# LEF Technology file generated by TechBuilder version 3.7.0_pr1
# Metal Stack Option = 1P8M_2TM_ALPA2
#
#     Copyright (c) 2017 ARM, Inc.
#
#     ALL RIGHTS RESERVED
#
#     The confidential and proprietary information contained in this file
#     may only be used by a person authorised under and to the extent
#     permitted by a subsisting licensing agreement from ARM Limited.
#
#     This entire notice must be reproduced on all copies of this file
#     and copies of this file may only be made by a person if such person
#     is permitted to do so under the terms of a subsisting license
#     agreement from ARM Limited.

VERSION 5.7 ;
BUSBITCHARS "[]" ;
DIVIDERCHAR "/" ;
CLEARANCEMEASURE EUCLIDEAN ;

UNITS
  DATABASE MICRONS 2000 ;
END UNITS

MANUFACTURINGGRID 0.0010 ;
USEMINSPACING OBS OFF ;

PROPERTYDEFINITIONS
  LAYER LEF58_ENCLOSUREEDGE STRING ;
  LAYER LEF58_ARRAYSPACING STRING ;
  LAYER LEF58_ARRAYSPACING STRING ; 
  LAYER LEF58_SPACING STRING ; 
END PROPERTYDEFINITIONS

LAYER GT
  TYPE MASTERSLICE ;
END GT

LAYER HVT
  TYPE IMPLANT ;
  SPACING 0.18 ;
  WIDTH 0.18 ;
END HVT

LAYER LVT
  TYPE IMPLANT ;
  SPACING 0.18 ;
  WIDTH 0.18 ;
END LVT

LAYER ULVT
  TYPE IMPLANT ;
  SPACING 0.33 ;
  WIDTH 0.33 ;
END ULVT

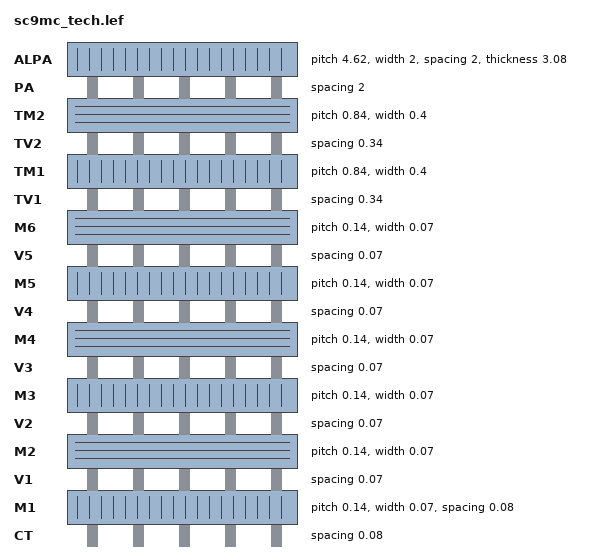
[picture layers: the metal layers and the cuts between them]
LAYER CT
  TYPE CUT ;
  SPACING 0.08 ;
  ENCLOSURE ABOVE 0.0 0.025 ;
  PROPERTY LEF58_ENCLOSUREEDGE "
  ENCLOSUREEDGE ABOVE 0.015 WIDTH 0.12 PARALLEL 0.27 WITHIN 0.081 EXCEPTEXTRACUT ;
  " ;
END CT

LAYER M1
  TYPE ROUTING ;
  DIRECTION VERTICAL ;
  PITCH 0.14 ;
  OFFSET 0.07 ;
  WIDTH 0.07 ;
  MINWIDTH 0.07 ;
  MAXWIDTH 4.5 ;
  AREA 0.0196 ;
  MINENCLOSEDAREA 0.2 ;
  MINSTEP 0.07 MAXEDGES 1 ;
  SPACINGTABLE TWOWIDTHS
    WIDTH 0.000        0.070 0.080 0.120 0.300
    WIDTH 0.224 PRL 0.299 0.080 0.080 0.140 0.300
    WIDTH 0.704 PRL 0.599 0.120 0.140 0.140 0.300
    WIDTH 1.504 PRL 1.499 0.300 0.300 0.300 0.300
    ;
  MINIMUMCUT 2 WIDTH 0.26 FROMABOVE ;
  MINIMUMCUT 3 WIDTH 0.52 FROMABOVE ;
  MINIMUMCUT 4 WIDTH 0.645 FROMABOVE ;
  MINIMUMCUT 2 WIDTH 0.24 WITHIN 0.16 FROMABOVE ;
  MINIMUMCUT 2 WIDTH 0.24 FROMABOVE LENGTH 0.24 WITHIN 1.1 ;
  MINIMUMCUT 2 WIDTH 1.4 FROMABOVE LENGTH 1.4 WITHIN 2.8 ;
  MINIMUMCUT 2 WIDTH 2.1 FROMABOVE LENGTH 7.0 WITHIN 7.1 ;
  ANTENNAMODEL OXIDE1 ;
  ANTENNACUMDIFFAREARATIO PWL (  ( 0.0 5000.0 ) ( 0.1 44050.0 ) ( 0.2 44100.0 ) ( 0.5 44250.0 ) ( 1.0 44500.0 ) ) ;
  DCCURRENTDENSITY AVERAGE 1.2 ;
  PROPERTY LEF58_SPACING "
SPACING .08 ENDOFLINE .09 WITHIN 0.02 PARALLELEDGE .081 WITHIN 0.1 MINLENGTH .07 TWOEDGES ; " ;
MINIMUMDENSITY      20 ;
    MAXIMUMDENSITY      80 ;
    DENSITYCHECKWINDOW 25 25 ;
    DENSITYCHECKSTEP    12.5 ;

END M1

LAYER V1
  TYPE CUT ;
  SPACING 0.07 SAMENET ;

  SPACING 0.1 PARALLELOVERLAP ;
  SPACING 0.09 ;
  PROPERTY LEF58_ARRAYSPACING "ARRAYSPACING  LONGARRAY CUTSPACING 0.09 ARRAYCUTS 3 SPACING 0.1 ;" ;
  ENCLOSURE  0.0 0.03 ;
  ENCLOSURE  0.02 0.01 ;
  ENCLOSURE  0.015 0.015 WIDTH 0.145 ;
  ANTENNAMODEL OXIDE1 ;
  ANTENNAAREARATIO 20.0 ;
  ANTENNACUMDIFFAREARATIO PWL (  ( 0.0 50.0 ) ( 0.1 1020.0 ) ( 0.2 1040.0 ) ( 0.5 1100.0 ) ( 1.0 1200.0 ) ) ;
  DCCURRENTDENSITY AVERAGE 0.07 ;
END V1

LAYER M2
  TYPE ROUTING ;
  DIRECTION HORIZONTAL ;
  PITCH 0.14 ;
  OFFSET 0.07 ;
  WIDTH 0.07 ;
  MINWIDTH 0.07 ;
  MAXWIDTH 4.5 ;
  AREA 0.0196 ;
  MINENCLOSEDAREA 0.2 ;
  MINSTEP 0.07 MAXEDGES 1 ;
  SPACINGTABLE TWOWIDTHS
    WIDTH 0.000        0.070 0.100 0.100 0.120 0.120 0.300
    WIDTH 0.219 PRL 0.299 0.100 0.100 0.100 0.120 0.120 0.300
    WIDTH 0.224 PRL 0.299 0.100 0.100 0.100 0.120 0.140 0.300
    WIDTH 0.699 PRL 0.599 0.120 0.120 0.120 0.120 0.140 0.300
    WIDTH 0.704 PRL 0.599 0.120 0.120 0.140 0.140 0.140 0.300
    WIDTH 1.504 PRL 1.504 0.300 0.300 0.300 0.300 0.300 0.300
    ;
  MINIMUMCUT 2 WIDTH 0.26 FROMBELOW ;
  MINIMUMCUT 3 WIDTH 0.52 FROMBELOW ;
  MINIMUMCUT 4 WIDTH 0.645 FROMBELOW ;
  MINIMUMCUT 2 WIDTH 0.24 WITHIN 0.16 FROMBELOW ;
  MINIMUMCUT 2 WIDTH 0.24 FROMBELOW LENGTH 0.24 WITHIN 1.1 ;
  MINIMUMCUT 2 WIDTH 1.4 FROMBELOW LENGTH 1.4 WITHIN 2.8 ;
  MINIMUMCUT 2 WIDTH 2.1 FROMBELOW LENGTH 7.0 WITHIN 7.1 ;
  MINIMUMCUT 2 WIDTH 0.26 FROMABOVE ;
  MINIMUMCUT 3 WIDTH 0.52 FROMABOVE ;
  MINIMUMCUT 4 WIDTH 0.645 FROMABOVE ;
  MINIMUMCUT 2 WIDTH 0.24 WITHIN 0.16 FROMABOVE ;
  MINIMUMCUT 2 WIDTH 0.24 FROMABOVE LENGTH 0.24 WITHIN 1.1 ;
  MINIMUMCUT 2 WIDTH 1.4 FROMABOVE LENGTH 1.4 WITHIN 2.8 ;
  MINIMUMCUT 2 WIDTH 2.1 FROMABOVE LENGTH 7.0 WITHIN 7.1 ;
  ANTENNAMODEL OXIDE1 ;
  ANTENNACUMDIFFAREARATIO PWL (  ( 0.0 5000.0 ) ( 0.1 44050.0 ) ( 0.2 44100.0 ) ( 0.5 44250.0 ) ( 1.0 44500.0 ) ) ;
  DCCURRENTDENSITY AVERAGE 1.3 ; 
  PROPERTY LEF58_SPACING "SPACING 0.12 ENDOFLINE 0.1 WITHIN 0.03 PARALLELEDGE 0.079 WITHIN 0.095  ENCLOSECUT BELOW 0.05 CUTSPACING 0.12 ;" ; 
  PROPERTY LEF58_SPACING "SPACING 0.1 ENDOFLINE 0.1 WITHIN 0.03 PARALLELEDGE 0.1 WITHIN 0.095 ;" ;
  PROPERTY LEF58_SPACING "SPACING 0.1 ENDOFLINE 0.1 WITHIN 0.03 ;" ;
MINIMUMDENSITY      20 ;
    MAXIMUMDENSITY      80 ;
    DENSITYCHECKWINDOW 25 25 ;
    DENSITYCHECKSTEP    12.5 ;

END M2

LAYER V2
  TYPE CUT ;
  SPACING 0.07 SAMENET ;
  SPACING 0.09 ;
  SPACING 0.1 PARALLELOVERLAP ;

  PROPERTY LEF58_ARRAYSPACING "ARRAYSPACING  LONGARRAY CUTSPACING 0.09 ARRAYCUTS 3 SPACING 0.1 ;" ;
  ENCLOSURE  0.0 0.03 ;
  ENCLOSURE  0.02 0.01 ;
  ENCLOSURE  0.015 0.015 WIDTH 0.145 ;
  ANTENNAMODEL OXIDE1 ;
  ANTENNAAREARATIO 20.0 ;
  ANTENNACUMDIFFAREARATIO PWL (  ( 0.0 50.0 ) ( 0.1 1020.0 ) ( 0.2 1040.0 ) ( 0.5 1100.0 ) ( 1.0 1200.0 ) ) ;
  DCCURRENTDENSITY AVERAGE 0.07 ;
END V2

LAYER M3
  TYPE ROUTING ;
  DIRECTION VERTICAL ;
  PITCH 0.14 ;
  OFFSET 0.07 ;
  WIDTH 0.07 ;
  MINWIDTH 0.07 ;
  MAXWIDTH 4.5 ;
  AREA 0.0196 ;
  MINENCLOSEDAREA 0.2 ;
  MINSTEP 0.07 MAXEDGES 1 ;
  SPACINGTABLE TWOWIDTHS
    WIDTH 0.000        0.070 0.100 0.100 0.120 0.120 0.300
    WIDTH 0.219 PRL 0.299 0.100 0.100 0.100 0.120 0.120 0.300
    WIDTH 0.224 PRL 0.299 0.100 0.100 0.100 0.120 0.140 0.300
    WIDTH 0.699 PRL 0.599 0.120 0.120 0.120 0.120 0.140 0.300
    WIDTH 0.704 PRL 0.599 0.120 0.120 0.140 0.140 0.140 0.300
    WIDTH 1.504 PRL 1.504 0.300 0.300 0.300 0.300 0.300 0.300
    ;
  MINIMUMCUT 2 WIDTH 0.26 FROMBELOW ;
  MINIMUMCUT 3 WIDTH 0.52 FROMBELOW ;
  MINIMUMCUT 4 WIDTH 0.645 FROMBELOW ;
  MINIMUMCUT 2 WIDTH 0.24 WITHIN 0.16 FROMBELOW ;
  MINIMUMCUT 2 WIDTH 0.24 FROMBELOW LENGTH 0.24 WITHIN 1.1 ;
  MINIMUMCUT 2 WIDTH 1.4 FROMBELOW LENGTH 1.4 WITHIN 2.8 ;
  MINIMUMCUT 2 WIDTH 2.1 FROMBELOW LENGTH 7.0 WITHIN 7.1 ;
  MINIMUMCUT 2 WIDTH 0.26 FROMABOVE ;
  MINIMUMCUT 3 WIDTH 0.52 FROMABOVE ;
  MINIMUMCUT 4 WIDTH 0.645 FROMABOVE ;
  MINIMUMCUT 2 WIDTH 0.24 WITHIN 0.16 FROMABOVE ;
  MINIMUMCUT 2 WIDTH 0.24 FROMABOVE LENGTH 0.24 WITHIN 1.1 ;
  MINIMUMCUT 2 WIDTH 1.4 FROMABOVE LENGTH 1.4 WITHIN 2.8 ;
  MINIMUMCUT 2 WIDTH 2.1 FROMABOVE LENGTH 7.0 WITHIN 7.1 ;
  ANTENNAMODEL OXIDE1 ;
  ANTENNACUMDIFFAREARATIO PWL (  ( 0.0 5000.0 ) ( 0.1 44050.0 ) ( 0.2 44100.0 ) ( 0.5 44250.0 ) ( 1.0 44500.0 ) ) ;
  DCCURRENTDENSITY AVERAGE 1.3 ; 
  PROPERTY LEF58_SPACING "SPACING 0.12 ENDOFLINE 0.1 WITHIN 0.03 PARALLELEDGE 0.079 WITHIN 0.095  ENCLOSECUT BELOW 0.05 CUTSPACING 0.12 ;" ; 
  PROPERTY LEF58_SPACING "SPACING 0.1 ENDOFLINE 0.1 WITHIN 0.03 PARALLELEDGE 0.1 WITHIN 0.095 ;" ;
  PROPERTY LEF58_SPACING "SPACING 0.1 ENDOFLINE 0.1 WITHIN 0.03 ;" ;
MINIMUMDENSITY      20 ;
    MAXIMUMDENSITY      80 ;
    DENSITYCHECKWINDOW 25 25 ;
    DENSITYCHECKSTEP    12.5 ;

END M3

LAYER V3
  TYPE CUT ;
  SPACING 0.07 SAMENET ;
  SPACING 0.09 ;
  SPACING 0.1 PARALLELOVERLAP ;

  PROPERTY LEF58_ARRAYSPACING "ARRAYSPACING  LONGARRAY CUTSPACING 0.09 ARRAYCUTS 3 SPACING 0.1 ;" ;
  ENCLOSURE  0.0 0.03 ;
  ENCLOSURE  0.02 0.01 ;
  ENCLOSURE  0.015 0.015 WIDTH 0.145 ;
  ANTENNAMODEL OXIDE1 ;
  ANTENNAAREARATIO 20.0 ;
  ANTENNACUMDIFFAREARATIO PWL (  ( 0.0 50.0 ) ( 0.1 1020.0 ) ( 0.2 1040.0 ) ( 0.5 1100.0 ) ( 1.0 1200.0 ) ) ;
  DCCURRENTDENSITY AVERAGE 0.07 ;
END V3

LAYER M4
  TYPE ROUTING ;
  DIRECTION HORIZONTAL ;
  PITCH 0.14 ;
  OFFSET 0.07 ;
  WIDTH 0.07 ;
  MINWIDTH 0.07 ;
  MAXWIDTH 4.5 ;
  AREA 0.0196 ;
  MINENCLOSEDAREA 0.2 ;
  MINSTEP 0.07 MAXEDGES 1 ;
  SPACINGTABLE TWOWIDTHS
    WIDTH 0.000        0.070 0.100 0.100 0.120 0.120 0.300
    WIDTH 0.219 PRL 0.299 0.100 0.100 0.100 0.120 0.120 0.300
    WIDTH 0.224 PRL 0.299 0.100 0.100 0.100 0.120 0.140 0.300
    WIDTH 0.699 PRL 0.599 0.120 0.120 0.120 0.120 0.140 0.300
    WIDTH 0.704 PRL 0.599 0.120 0.120 0.140 0.140 0.140 0.300
    WIDTH 1.504 PRL 1.504 0.300 0.300 0.300 0.300 0.300 0.300
    ;
  MINIMUMCUT 2 WIDTH 0.26 FROMBELOW ;
  MINIMUMCUT 3 WIDTH 0.52 FROMBELOW ;
  MINIMUMCUT 4 WIDTH 0.645 FROMBELOW ;
  MINIMUMCUT 2 WIDTH 0.24 WITHIN 0.16 FROMBELOW ;
  MINIMUMCUT 2 WIDTH 0.24 FROMBELOW LENGTH 0.24 WITHIN 1.1 ;
  MINIMUMCUT 2 WIDTH 1.4 FROMBELOW LENGTH 1.4 WITHIN 2.8 ;
  MINIMUMCUT 2 WIDTH 2.1 FROMBELOW LENGTH 7.0 WITHIN 7.1 ;
  MINIMUMCUT 2 WIDTH 0.26 FROMABOVE ;
  MINIMUMCUT 3 WIDTH 0.52 FROMABOVE ;
  MINIMUMCUT 4 WIDTH 0.645 FROMABOVE ;
  MINIMUMCUT 2 WIDTH 0.24 WITHIN 0.16 FROMABOVE ;
  MINIMUMCUT 2 WIDTH 0.24 FROMABOVE LENGTH 0.24 WITHIN 1.1 ;
  MINIMUMCUT 2 WIDTH 1.4 FROMABOVE LENGTH 1.4 WITHIN 2.8 ;
  MINIMUMCUT 2 WIDTH 2.1 FROMABOVE LENGTH 7.0 WITHIN 7.1 ;
  ANTENNAMODEL OXIDE1 ;
  ANTENNACUMDIFFAREARATIO PWL (  ( 0.0 5000.0 ) ( 0.1 44050.0 ) ( 0.2 44100.0 ) ( 0.5 44250.0 ) ( 1.0 44500.0 ) ) ;
  DCCURRENTDENSITY AVERAGE 1.3 ; 
  PROPERTY LEF58_SPACING "SPACING 0.12 ENDOFLINE 0.1 WITHIN 0.03 PARALLELEDGE 0.079 WITHIN 0.095  ENCLOSECUT BELOW 0.05 CUTSPACING 0.12 ;" ; 
  PROPERTY LEF58_SPACING "SPACING 0.1 ENDOFLINE 0.1 WITHIN 0.03 PARALLELEDGE 0.1 WITHIN 0.095 ;" ;
  PROPERTY LEF58_SPACING "SPACING 0.1 ENDOFLINE 0.1 WITHIN 0.03 ;" ;
MINIMUMDENSITY      20 ;
    MAXIMUMDENSITY      80 ;
    DENSITYCHECKWINDOW 25 25 ;
    DENSITYCHECKSTEP    12.5 ;

END M4

LAYER V4
  TYPE CUT ;
  SPACING 0.07 SAMENET ;
  SPACING 0.09 ;
  SPACING 0.1 PARALLELOVERLAP ;

  PROPERTY LEF58_ARRAYSPACING "ARRAYSPACING  LONGARRAY CUTSPACING 0.09 ARRAYCUTS 3 SPACING 0.1 ;" ;
  ENCLOSURE  0.0 0.03 ;
  ENCLOSURE  0.02 0.01 ;
  ENCLOSURE  0.015 0.015 WIDTH 0.145 ;
  ANTENNAMODEL OXIDE1 ;
  ANTENNAAREARATIO 20.0 ;
  ANTENNACUMDIFFAREARATIO PWL (  ( 0.0 50.0 ) ( 0.1 1020.0 ) ( 0.2 1040.0 ) ( 0.5 1100.0 ) ( 1.0 1200.0 ) ) ;
  DCCURRENTDENSITY AVERAGE 0.07 ;
END V4

LAYER M5
  TYPE ROUTING ;
  DIRECTION VERTICAL ;
  PITCH 0.14 ;
  OFFSET 0.07 ;
  WIDTH 0.07 ;
  MINWIDTH 0.07 ;
  MAXWIDTH 4.5 ;
  AREA 0.0196 ;
  MINENCLOSEDAREA 0.2 ;
  MINSTEP 0.07 MAXEDGES 1 ;
  SPACINGTABLE TWOWIDTHS
    WIDTH 0.000        0.070 0.100 0.100 0.120 0.120 0.300
    WIDTH 0.219 PRL 0.299 0.100 0.100 0.100 0.120 0.120 0.300
    WIDTH 0.224 PRL 0.299 0.100 0.100 0.100 0.120 0.140 0.300
    WIDTH 0.699 PRL 0.599 0.120 0.120 0.120 0.120 0.140 0.300
    WIDTH 0.704 PRL 0.599 0.120 0.120 0.140 0.140 0.140 0.300
    WIDTH 1.504 PRL 1.504 0.300 0.300 0.300 0.300 0.300 0.300
    ;
  MINIMUMCUT 2 WIDTH 0.26 FROMBELOW ;
  MINIMUMCUT 3 WIDTH 0.52 FROMBELOW ;
  MINIMUMCUT 4 WIDTH 0.645 FROMBELOW ;
  MINIMUMCUT 2 WIDTH 0.24 WITHIN 0.16 FROMBELOW ;
  MINIMUMCUT 2 WIDTH 0.24 FROMBELOW LENGTH 0.24 WITHIN 1.1 ;
  MINIMUMCUT 2 WIDTH 1.4 FROMBELOW LENGTH 1.4 WITHIN 2.8 ;
  MINIMUMCUT 2 WIDTH 2.1 FROMBELOW LENGTH 7.0 WITHIN 7.1 ;
  MINIMUMCUT 2 WIDTH 0.26 FROMABOVE ;
  MINIMUMCUT 3 WIDTH 0.52 FROMABOVE ;
  MINIMUMCUT 4 WIDTH 0.645 FROMABOVE ;
  MINIMUMCUT 2 WIDTH 0.24 WITHIN 0.16 FROMABOVE ;
  MINIMUMCUT 2 WIDTH 0.24 FROMABOVE LENGTH 0.24 WITHIN 1.1 ;
  MINIMUMCUT 2 WIDTH 1.4 FROMABOVE LENGTH 1.4 WITHIN 2.8 ;
  MINIMUMCUT 2 WIDTH 2.1 FROMABOVE LENGTH 7.0 WITHIN 7.1 ;
  ANTENNAMODEL OXIDE1 ;
  ANTENNACUMDIFFAREARATIO PWL (  ( 0.0 5000.0 ) ( 0.1 44050.0 ) ( 0.2 44100.0 ) ( 0.5 44250.0 ) ( 1.0 44500.0 ) ) ;
  DCCURRENTDENSITY AVERAGE 1.3 ; 
  PROPERTY LEF58_SPACING "SPACING 0.12 ENDOFLINE 0.1 WITHIN 0.03 PARALLELEDGE 0.079 WITHIN 0.095  ENCLOSECUT BELOW 0.05 CUTSPACING 0.12 ;" ; 
  PROPERTY LEF58_SPACING "SPACING 0.1 ENDOFLINE 0.1 WITHIN 0.03 PARALLELEDGE 0.1 WITHIN 0.095 ;" ;
  PROPERTY LEF58_SPACING "SPACING 0.1 ENDOFLINE 0.1 WITHIN 0.03 ;" ;
MINIMUMDENSITY      20 ;
    MAXIMUMDENSITY      80 ;
    DENSITYCHECKWINDOW 25 25 ;
    DENSITYCHECKSTEP    12.5 ;

END M5

LAYER V5
  TYPE CUT ;
  SPACING 0.07 SAMENET ;
  SPACING 0.09 ;
  SPACING 0.1 PARALLELOVERLAP ;

  PROPERTY LEF58_ARRAYSPACING "ARRAYSPACING  LONGARRAY CUTSPACING 0.09 ARRAYCUTS 3 SPACING 0.1 ;" ;
  ENCLOSURE  0.0 0.03 ;
  ENCLOSURE  0.02 0.01 ;
  ENCLOSURE  0.015 0.015 WIDTH 0.145 ;
  ANTENNAMODEL OXIDE1 ;
  ANTENNAAREARATIO 20.0 ;
  ANTENNACUMDIFFAREARATIO PWL (  ( 0.0 50.0 ) ( 0.1 1020.0 ) ( 0.2 1040.0 ) ( 0.5 1100.0 ) ( 1.0 1200.0 ) ) ;
  DCCURRENTDENSITY AVERAGE 0.07 ;
END V5

LAYER M6
  TYPE ROUTING ;
  DIRECTION HORIZONTAL ;
  PITCH 0.14 ;
  OFFSET 0.07 ;
  WIDTH 0.07 ;
  MINWIDTH 0.07 ;
  MAXWIDTH 4.5 ;
  AREA 0.0196 ;
  MINENCLOSEDAREA 0.2 ;
  MINSTEP 0.07 MAXEDGES 1 ;
  SPACINGTABLE TWOWIDTHS
    WIDTH 0.000        0.070 0.100 0.100 0.120 0.120 0.300
    WIDTH 0.219 PRL 0.299 0.100 0.100 0.100 0.120 0.120 0.300
    WIDTH 0.224 PRL 0.299 0.100 0.100 0.100 0.120 0.140 0.300
    WIDTH 0.699 PRL 0.599 0.120 0.120 0.120 0.120 0.140 0.300
    WIDTH 0.704 PRL 0.599 0.120 0.120 0.140 0.140 0.140 0.300
    WIDTH 1.504 PRL 1.504 0.300 0.300 0.300 0.300 0.300 0.300
    ;
  MINIMUMCUT 2 WIDTH 0.26 FROMBELOW ;
  MINIMUMCUT 3 WIDTH 0.52 FROMBELOW ;
  MINIMUMCUT 4 WIDTH 0.645 FROMBELOW ;
  MINIMUMCUT 2 WIDTH 0.24 WITHIN 0.16 FROMBELOW ;
  MINIMUMCUT 2 WIDTH 0.24 FROMBELOW LENGTH 0.24 WITHIN 1.1 ;
  MINIMUMCUT 2 WIDTH 1.4 FROMBELOW LENGTH 1.4 WITHIN 2.8 ;
  MINIMUMCUT 2 WIDTH 2.1 FROMBELOW LENGTH 7.0 WITHIN 7.1 ;
  MINIMUMCUT 2 WIDTH 1.8 FROMABOVE ;
  MINIMUMCUT 2 WIDTH 3.0 FROMABOVE LENGTH 10.0 WITHIN 5.0 ;
  ANTENNAMODEL OXIDE1 ;
  ANTENNACUMDIFFAREARATIO PWL (  ( 0.0 5000.0 ) ( 0.1 44050.0 ) ( 0.2 44100.0 ) ( 0.5 44250.0 ) ( 1.0 44500.0 ) ) ;
  DCCURRENTDENSITY AVERAGE 1.3 ; 
  PROPERTY LEF58_SPACING "SPACING 0.12 ENDOFLINE 0.1 WITHIN 0.03 PARALLELEDGE 0.079 WITHIN 0.095  ENCLOSECUT BELOW 0.05 CUTSPACING 0.12 ;" ; 
  PROPERTY LEF58_SPACING "SPACING 0.1 ENDOFLINE 0.1 WITHIN 0.03 PARALLELEDGE 0.1 WITHIN 0.095 ;" ;
  PROPERTY LEF58_SPACING "SPACING 0.1 ENDOFLINE 0.1 WITHIN 0.03 ;" ;
MINIMUMDENSITY      20 ;
    MAXIMUMDENSITY      80 ;
    DENSITYCHECKWINDOW 25 25 ;
    DENSITYCHECKSTEP    12.5 ;

END M6

LAYER TV1
  TYPE CUT ;
  SPACING 0.34 ;

  PROPERTY LEF58_ARRAYSPACING "ARRAYSPACING  LONGARRAY CUTSPACING 0.5 ARRAYCUTS 3 SPACING 0.56 ;" ;
  ENCLOSURE BELOW 0.01 0.05 ;
  ENCLOSURE ABOVE 0.02 0.03 ;
  ANTENNAMODEL OXIDE1 ;
  ANTENNAAREARATIO 20.0 ;
  ANTENNACUMDIFFAREARATIO PWL (  ( 0.0 50.0 ) ( 0.1 1020.0 ) ( 0.2 1040.0 ) ( 0.5 1100.0 ) ( 1.0 1200.0 ) ) ;
  DCCURRENTDENSITY AVERAGE 3.0 ;
END TV1

LAYER TM1
  TYPE ROUTING ;
  DIRECTION VERTICAL ;
  PITCH 0.84 ;
  OFFSET 0.42 ;
  WIDTH 0.4 ;
  MINWIDTH 0.4 ;
  MAXWIDTH 12.0 ;
  AREA 0.56 ;
  MINENCLOSEDAREA 0.78 ;
  MINSTEP 0.4 MAXEDGES 1 ;
  SPACINGTABLE TWOWIDTHS
    WIDTH 0.000        0.400 0.500 0.500
    WIDTH 2.004 PRL 1.504 0.500 0.500 0.500
    WIDTH 4.504 PRL 4.504 0.500 0.500 1.200
    ;
  MINIMUMCUT 2 WIDTH 1.8 FROMBELOW ;
  MINIMUMCUT 2 WIDTH 3.0 FROMBELOW LENGTH 10.0 WITHIN 5.0 ;
  MINIMUMCUT 2 WIDTH 1.8 FROMABOVE ;
  MINIMUMCUT 2 WIDTH 3.0 FROMABOVE LENGTH 10.0 WITHIN 5.0 ;
  ANTENNAMODEL OXIDE1 ;
  ANTENNADIFFAREARATIO PWL (  ( 0.01 55099.84 ) ( 0.05 55499.2 ) ( 0.1 55998.4 ) ( 0.5 59992.0 ) ) ;
  ANTENNACUMAREARATIO 5000.0 ;
  DCCURRENTDENSITY AVERAGE 8.8 ;
MINIMUMDENSITY      20 ;
    MAXIMUMDENSITY      85 ;
    DENSITYCHECKWINDOW 200 200 ;
    DENSITYCHECKSTEP    100 ;

END TM1

LAYER TV2
  TYPE CUT ;
  SPACING 0.34 ;

  PROPERTY LEF58_ARRAYSPACING "ARRAYSPACING  LONGARRAY CUTSPACING 0.5 ARRAYCUTS 3 SPACING 0.56 ;" ;
  ENCLOSURE BELOW 0.02 0.05 ;
  ENCLOSURE ABOVE 0.02 0.05 ;
  ANTENNAMODEL OXIDE1 ;
  ANTENNAAREARATIO 20.0 ;
  ANTENNACUMDIFFAREARATIO PWL (  ( 0.0 50.0 ) ( 0.1 1020.0 ) ( 0.2 1040.0 ) ( 0.5 1100.0 ) ( 1.0 1200.0 ) ) ;
  DCCURRENTDENSITY AVERAGE 3.0 ;
END TV2

LAYER TM2
  TYPE ROUTING ;
  DIRECTION HORIZONTAL ;
  PITCH 0.84 ;
  OFFSET 0.42 ;
  WIDTH 0.4 ;
  MINWIDTH 0.4 ;
  MAXWIDTH 12.0 ;
  AREA 0.56 ;
  MINENCLOSEDAREA 0.78 ;
  MINSTEP 0.4 MAXEDGES 1 ;
  SPACINGTABLE 
    PARALLELRUNLENGTH  0.000 1.504 4.504 
    WIDTH 0.000        0.400 0.400 0.400
    WIDTH 2.004        0.400 0.500 0.500
    WIDTH 4.504        0.400 0.500 1.200
    ;
  MINIMUMCUT 2 WIDTH 1.8 FROMBELOW ;
  MINIMUMCUT 2 WIDTH 3.0 FROMBELOW LENGTH 10.0 WITHIN 5.0 ;
  ANTENNAMODEL OXIDE1 ;
  ANTENNADIFFAREARATIO PWL (  ( 0.01 55099.84 ) ( 0.05 55499.2 ) ( 0.1 55998.4 ) ( 0.5 59992.0 ) ) ;
  ANTENNACUMAREARATIO 5000.0 ;
  DCCURRENTDENSITY AVERAGE 8.8 ;
MINIMUMDENSITY      20 ;
    MAXIMUMDENSITY      85 ;
    DENSITYCHECKWINDOW 200 200 ;
    DENSITYCHECKSTEP    100 ;

END TM2

LAYER PA
  TYPE CUT ;
  SPACING 2.0 ;
  ENCLOSURE  0.5 0.5 ;
  ANTENNAMODEL OXIDE1 ;
  ANTENNADIFFAREARATIO PWL (  ( 0.0 200.0 ) ( 0.1 410.0 ) ( 0.5 450.0 ) ( 1.0 500.0 ) ( 5.0 900.0 ) ) ;
END PA

LAYER ALPA
  TYPE ROUTING ;
  THICKNESS 3.08 ;
  DIRECTION VERTICAL ;
  PITCH 4.62 ;
  OFFSET 2.31 ;
  WIDTH 2.0 ;
  MINWIDTH 2.0 ;
  SPACING 2.0 ;
  ANTENNAMODEL OXIDE1 ;
  ANTENNADIFFSIDEAREARATIO PWL (  ( 0.0 2000.0 ) ( 0.1 30850.0 ) ( 0.2 31700.0 ) ( 0.5 34250.0 ) ( 1.0 38500.0 ) ( 5.0 72500.0 ) ) ;
MINIMUMDENSITY      10 ;
    MAXIMUMDENSITY      70 ;

END ALPA

LAYER OVERLAP
  TYPE OVERLAP ;
END OVERLAP

VIA V1_0_VH DEFAULT
  LAYER M1 ;
    RECT -0.035 -0.065 0.035 0.065 ;
  LAYER M2 ;
    RECT -0.065 -0.035 0.065 0.035 ;
  LAYER V1 ;
    RECT -0.035 -0.035 0.035 0.035 ;
END V1_0_VH

VIA V1_0_HH DEFAULT
  LAYER M1 ;
    RECT -0.065 -0.035 0.065 0.035 ;
  LAYER M2 ;
    RECT -0.065 -0.035 0.065 0.035 ;
  LAYER V1 ;
    RECT -0.035 -0.035 0.035 0.035 ;
END V1_0_HH

VIA V1_0_VV DEFAULT
  LAYER M1 ;
    RECT -0.035 -0.065 0.035 0.065 ;
  LAYER M2 ;
    RECT -0.035 -0.065 0.035 0.065 ;
  LAYER V1 ;
    RECT -0.035 -0.035 0.035 0.035 ;
END V1_0_VV

VIA V1_0_HV DEFAULT
  LAYER M1 ;
    RECT -0.065 -0.035 0.065 0.035 ;
  LAYER M2 ;
    RECT -0.035 -0.065 0.035 0.065 ;
  LAYER V1 ;
    RECT -0.035 -0.035 0.035 0.035 ;
END V1_0_HV

VIA V1_1_VH DEFAULT
  LAYER M1 ;
    RECT -0.035 -0.065 0.035 0.065 ;
  LAYER M2 ;
    RECT -0.055 -0.045 0.055 0.045 ;
  LAYER V1 ;
    RECT -0.035 -0.035 0.035 0.035 ;
END V1_1_VH

VIA V1_1_HH DEFAULT
  LAYER M1 ;
    RECT -0.065 -0.035 0.065 0.035 ;
  LAYER M2 ;
    RECT -0.055 -0.045 0.055 0.045 ;
  LAYER V1 ;
    RECT -0.035 -0.035 0.035 0.035 ;
END V1_1_HH

VIA V1_1_VV DEFAULT
  LAYER M1 ;
    RECT -0.035 -0.065 0.035 0.065 ;
  LAYER M2 ;
    RECT -0.045 -0.055 0.045 0.055 ;
  LAYER V1 ;
    RECT -0.035 -0.035 0.035 0.035 ;
END V1_1_VV

VIA V1_1_HV DEFAULT
  LAYER M1 ;
    RECT -0.065 -0.035 0.065 0.035 ;
  LAYER M2 ;
    RECT -0.045 -0.055 0.045 0.055 ;
  LAYER V1 ;
    RECT -0.035 -0.035 0.035 0.035 ;
END V1_1_HV

VIA V1_2_VX DEFAULT
  LAYER M1 ;
    RECT -0.035 -0.065 0.035 0.065 ;
  LAYER M2 ;
    RECT -0.05 -0.05 0.05 0.05 ;
  LAYER V1 ;
    RECT -0.035 -0.035 0.035 0.035 ;
END V1_2_VX

VIA V1_2_HX DEFAULT
  LAYER M1 ;
    RECT -0.065 -0.035 0.065 0.035 ;
  LAYER M2 ;
    RECT -0.05 -0.05 0.05 0.05 ;
  LAYER V1 ;
    RECT -0.035 -0.035 0.035 0.035 ;
END V1_2_HX

VIA V1_3_VH DEFAULT
  LAYER M1 ;
    RECT -0.045 -0.055 0.045 0.055 ;
  LAYER M2 ;
    RECT -0.065 -0.035 0.065 0.035 ;
  LAYER V1 ;
    RECT -0.035 -0.035 0.035 0.035 ;
END V1_3_VH

VIA V1_3_HH DEFAULT
  LAYER M1 ;
    RECT -0.055 -0.045 0.055 0.045 ;
  LAYER M2 ;
    RECT -0.065 -0.035 0.065 0.035 ;
  LAYER V1 ;
    RECT -0.035 -0.035 0.035 0.035 ;
END V1_3_HH

VIA V1_3_VV DEFAULT
  LAYER M1 ;
    RECT -0.045 -0.055 0.045 0.055 ;
  LAYER M2 ;
    RECT -0.035 -0.065 0.035 0.065 ;
  LAYER V1 ;
    RECT -0.035 -0.035 0.035 0.035 ;
END V1_3_VV

VIA V1_3_HV DEFAULT
  LAYER M1 ;
    RECT -0.055 -0.045 0.055 0.045 ;
  LAYER M2 ;
    RECT -0.035 -0.065 0.035 0.065 ;
  LAYER V1 ;
    RECT -0.035 -0.035 0.035 0.035 ;
END V1_3_HV

VIA V1_4_VH DEFAULT
  LAYER M1 ;
    RECT -0.045 -0.055 0.045 0.055 ;
  LAYER M2 ;
    RECT -0.055 -0.045 0.055 0.045 ;
  LAYER V1 ;
    RECT -0.035 -0.035 0.035 0.035 ;
END V1_4_VH

VIA V1_4_HH DEFAULT
  LAYER M1 ;
    RECT -0.055 -0.045 0.055 0.045 ;
  LAYER M2 ;
    RECT -0.055 -0.045 0.055 0.045 ;
  LAYER V1 ;
    RECT -0.035 -0.035 0.035 0.035 ;
END V1_4_HH

VIA V1_4_VV DEFAULT
  LAYER M1 ;
    RECT -0.045 -0.055 0.045 0.055 ;
  LAYER M2 ;
    RECT -0.045 -0.055 0.045 0.055 ;
  LAYER V1 ;
    RECT -0.035 -0.035 0.035 0.035 ;
END V1_4_VV

VIA V1_4_HV DEFAULT
  LAYER M1 ;
    RECT -0.055 -0.045 0.055 0.045 ;
  LAYER M2 ;
    RECT -0.045 -0.055 0.045 0.055 ;
  LAYER V1 ;
    RECT -0.035 -0.035 0.035 0.035 ;
END V1_4_HV

VIA V1_5_VX DEFAULT
  LAYER M1 ;
    RECT -0.045 -0.055 0.045 0.055 ;
  LAYER M2 ;
    RECT -0.05 -0.05 0.05 0.05 ;
  LAYER V1 ;
    RECT -0.035 -0.035 0.035 0.035 ;
END V1_5_VX

VIA V1_5_HX DEFAULT
  LAYER M1 ;
    RECT -0.055 -0.045 0.055 0.045 ;
  LAYER M2 ;
    RECT -0.05 -0.05 0.05 0.05 ;
  LAYER V1 ;
    RECT -0.035 -0.035 0.035 0.035 ;
END V1_5_HX

VIA V1_6_XH DEFAULT
  LAYER M1 ;
    RECT -0.05 -0.05 0.05 0.05 ;
  LAYER M2 ;
    RECT -0.065 -0.035 0.065 0.035 ;
  LAYER V1 ;
    RECT -0.035 -0.035 0.035 0.035 ;
END V1_6_XH

VIA V1_6_XV DEFAULT
  LAYER M1 ;
    RECT -0.05 -0.05 0.05 0.05 ;
  LAYER M2 ;
    RECT -0.035 -0.065 0.035 0.065 ;
  LAYER V1 ;
    RECT -0.035 -0.035 0.035 0.035 ;
END V1_6_XV

VIA V1_7_XH DEFAULT
  LAYER M1 ;
    RECT -0.05 -0.05 0.05 0.05 ;
  LAYER M2 ;
    RECT -0.055 -0.045 0.055 0.045 ;
  LAYER V1 ;
    RECT -0.035 -0.035 0.035 0.035 ;
END V1_7_XH

VIA V1_7_XV DEFAULT
  LAYER M1 ;
    RECT -0.05 -0.05 0.05 0.05 ;
  LAYER M2 ;
    RECT -0.045 -0.055 0.045 0.055 ;
  LAYER V1 ;
    RECT -0.035 -0.035 0.035 0.035 ;
END V1_7_XV

VIA V1_8_XX DEFAULT
  LAYER M1 ;
    RECT -0.05 -0.05 0.05 0.05 ;
  LAYER M2 ;
    RECT -0.05 -0.05 0.05 0.05 ;
  LAYER V1 ;
    RECT -0.035 -0.035 0.035 0.035 ;
END V1_8_XX

VIA V1_4_X2H_VH DEFAULT
  LAYER M1 ;
    RECT -0.115 -0.055 0.115 0.055 ;
  LAYER M2 ;
    RECT -0.125 -0.045 0.125 0.045 ;
  LAYER V1 ;
    RECT -0.105 -0.035 -0.035 0.035 ;
    RECT 0.035 -0.035 0.105 0.035 ;
END V1_4_X2H_VH

VIA V1_4_X2E_VH DEFAULT
  LAYER M1 ;
    RECT -0.045 -0.055 0.185 0.055 ;
  LAYER M2 ;
    RECT -0.055 -0.045 0.195 0.045 ;
  LAYER V1 ;
    RECT -0.035 -0.035 0.035 0.035 ;
    RECT 0.105 -0.035 0.175 0.035 ;
END V1_4_X2E_VH

VIA V1_4_X2W_VH DEFAULT
  LAYER M1 ;
    RECT -0.185 -0.055 0.045 0.055 ;
  LAYER M2 ;
    RECT -0.195 -0.045 0.055 0.045 ;
  LAYER V1 ;
    RECT -0.035 -0.035 0.035 0.035 ;
    RECT -0.175 -0.035 -0.105 0.035 ;
END V1_4_X2W_VH

VIA V1_4_X2V_VH DEFAULT
  LAYER M1 ;
    RECT -0.045 -0.125 0.045 0.125 ;
  LAYER M2 ;
    RECT -0.055 -0.115 0.055 0.115 ;
  LAYER V1 ;
    RECT -0.035 -0.105 0.035 -0.035 ;
    RECT -0.035 0.035 0.035 0.105 ;
END V1_4_X2V_VH

VIA V1_4_X2N_VH DEFAULT
  LAYER M1 ;
    RECT -0.045 -0.055 0.045 0.195 ;
  LAYER M2 ;
    RECT -0.055 -0.045 0.055 0.185 ;
  LAYER V1 ;
    RECT -0.035 -0.035 0.035 0.035 ;
    RECT -0.035 0.105 0.035 0.175 ;
END V1_4_X2N_VH

VIA V1_4_X2S_VH DEFAULT
  LAYER M1 ;
    RECT -0.045 -0.195 0.045 0.055 ;
  LAYER M2 ;
    RECT -0.055 -0.185 0.055 0.045 ;
  LAYER V1 ;
    RECT -0.035 -0.035 0.035 0.035 ;
    RECT -0.035 -0.175 0.035 -0.105 ;
END V1_4_X2S_VH

VIA V1_4_X3H_VH DEFAULT
  LAYER M1 ;
    RECT -0.185 -0.055 0.185 0.055 ;
  LAYER M2 ;
    RECT -0.195 -0.045 0.195 0.045 ;
  LAYER V1 ;
    RECT -0.175 -0.035 -0.105 0.035 ;
    RECT -0.035 -0.035 0.035 0.035 ;
    RECT 0.105 -0.035 0.175 0.035 ;
END V1_4_X3H_VH

VIA V1_4_X3E_VH DEFAULT
  LAYER M1 ;
    RECT -0.045 -0.055 0.325 0.055 ;
  LAYER M2 ;
    RECT -0.055 -0.045 0.335 0.045 ;
  LAYER V1 ;
    RECT -0.035 -0.035 0.035 0.035 ;
    RECT 0.105 -0.035 0.175 0.035 ;
    RECT 0.245 -0.035 0.315 0.035 ;
END V1_4_X3E_VH

VIA V1_4_X3W_VH DEFAULT
  LAYER M1 ;
    RECT -0.325 -0.055 0.045 0.055 ;
  LAYER M2 ;
    RECT -0.335 -0.045 0.055 0.045 ;
  LAYER V1 ;
    RECT -0.035 -0.035 0.035 0.035 ;
    RECT -0.175 -0.035 -0.105 0.035 ;
    RECT -0.315 -0.035 -0.245 0.035 ;
END V1_4_X3W_VH

VIA V1_4_X3V_VH DEFAULT
  LAYER M1 ;
    RECT -0.045 -0.195 0.045 0.195 ;
  LAYER M2 ;
    RECT -0.055 -0.185 0.055 0.185 ;
  LAYER V1 ;
    RECT -0.035 -0.175 0.035 -0.105 ;
    RECT -0.035 -0.035 0.035 0.035 ;
    RECT -0.035 0.105 0.035 0.175 ;
END V1_4_X3V_VH

VIA V1_4_X3N_VH DEFAULT
  LAYER M1 ;
    RECT -0.045 -0.055 0.045 0.335 ;
  LAYER M2 ;
    RECT -0.055 -0.045 0.055 0.325 ;
  LAYER V1 ;
    RECT -0.035 -0.035 0.035 0.035 ;
    RECT -0.035 0.105 0.035 0.175 ;
    RECT -0.035 0.245 0.035 0.315 ;
END V1_4_X3N_VH

VIA V1_4_X3S_VH DEFAULT
  LAYER M1 ;
    RECT -0.045 -0.335 0.045 0.055 ;
  LAYER M2 ;
    RECT -0.055 -0.325 0.055 0.045 ;
  LAYER V1 ;
    RECT -0.035 -0.035 0.035 0.035 ;
    RECT -0.035 -0.175 0.035 -0.105 ;
    RECT -0.035 -0.315 0.035 -0.245 ;
END V1_4_X3S_VH

VIA V1_4_X4H_VH DEFAULT
  LAYER M1 ;
    RECT -0.115 -0.125 0.115 0.125 ;
  LAYER M2 ;
    RECT -0.125 -0.115 0.125 0.115 ;
  LAYER V1 ;
    RECT -0.105 -0.105 -0.035 -0.035 ;
    RECT 0.035 -0.105 0.105 -0.035 ;
    RECT -0.105 0.035 -0.035 0.105 ;
    RECT 0.035 0.035 0.105 0.105 ;
END V1_4_X4H_VH

VIA V1_4_X4E_VH DEFAULT
  LAYER M1 ;
    RECT -0.045 -0.195 0.185 0.055 ;
  LAYER M2 ;
    RECT -0.055 -0.185 0.195 0.045 ;
  LAYER V1 ;
    RECT -0.035 -0.175 0.035 -0.105 ;
    RECT 0.105 -0.175 0.175 -0.105 ;
    RECT -0.035 -0.035 0.035 0.035 ;
    RECT 0.105 -0.035 0.175 0.035 ;
END V1_4_X4E_VH

VIA V1_4_X4W_VH DEFAULT
  LAYER M1 ;
    RECT -0.185 -0.055 0.045 0.195 ;
  LAYER M2 ;
    RECT -0.195 -0.045 0.055 0.185 ;
  LAYER V1 ;
    RECT -0.175 -0.035 -0.105 0.035 ;
    RECT -0.035 -0.035 0.035 0.035 ;
    RECT -0.175 0.105 -0.105 0.175 ;
    RECT -0.035 0.105 0.035 0.175 ;
END V1_4_X4W_VH

VIA V1_4_X4N_VH DEFAULT
  LAYER M1 ;
    RECT -0.045 -0.055 0.185 0.195 ;
  LAYER M2 ;
    RECT -0.055 -0.045 0.195 0.185 ;
  LAYER V1 ;
    RECT -0.035 -0.035 0.035 0.035 ;
    RECT 0.105 -0.035 0.175 0.035 ;
    RECT -0.035 0.105 0.035 0.175 ;
    RECT 0.105 0.105 0.175 0.175 ;
END V1_4_X4N_VH

VIA V1_4_X4S_VH DEFAULT
  LAYER M1 ;
    RECT -0.185 -0.195 0.045 0.055 ;
  LAYER M2 ;
    RECT -0.195 -0.185 0.055 0.045 ;
  LAYER V1 ;
    RECT -0.175 -0.175 -0.105 -0.105 ;
    RECT -0.035 -0.175 0.035 -0.105 ;
    RECT -0.175 -0.035 -0.105 0.035 ;
    RECT -0.035 -0.035 0.035 0.035 ;
END V1_4_X4S_VH

VIA V1_5_X2H_VX DEFAULT
  LAYER M1 ;
    RECT -0.115 -0.055 0.115 0.055 ;
  LAYER M2 ;
    RECT -0.12 -0.05 0.12 0.05 ;
  LAYER V1 ;
    RECT -0.105 -0.035 -0.035 0.035 ;
    RECT 0.035 -0.035 0.105 0.035 ;
END V1_5_X2H_VX

VIA V1_5_X2E_VX DEFAULT
  LAYER M1 ;
    RECT -0.045 -0.055 0.185 0.055 ;
  LAYER M2 ;
    RECT -0.05 -0.05 0.19 0.05 ;
  LAYER V1 ;
    RECT -0.035 -0.035 0.035 0.035 ;
    RECT 0.105 -0.035 0.175 0.035 ;
END V1_5_X2E_VX

VIA V1_5_X2W_VX DEFAULT
  LAYER M1 ;
    RECT -0.185 -0.055 0.045 0.055 ;
  LAYER M2 ;
    RECT -0.19 -0.05 0.05 0.05 ;
  LAYER V1 ;
    RECT -0.035 -0.035 0.035 0.035 ;
    RECT -0.175 -0.035 -0.105 0.035 ;
END V1_5_X2W_VX

VIA V1_5_X2V_VX DEFAULT
  LAYER M1 ;
    RECT -0.045 -0.125 0.045 0.125 ;
  LAYER M2 ;
    RECT -0.05 -0.12 0.05 0.12 ;
  LAYER V1 ;
    RECT -0.035 -0.105 0.035 -0.035 ;
    RECT -0.035 0.035 0.035 0.105 ;
END V1_5_X2V_VX

VIA V1_5_X2N_VX DEFAULT
  LAYER M1 ;
    RECT -0.045 -0.055 0.045 0.195 ;
  LAYER M2 ;
    RECT -0.05 -0.05 0.05 0.19 ;
  LAYER V1 ;
    RECT -0.035 -0.035 0.035 0.035 ;
    RECT -0.035 0.105 0.035 0.175 ;
END V1_5_X2N_VX

VIA V1_5_X2S_VX DEFAULT
  LAYER M1 ;
    RECT -0.045 -0.195 0.045 0.055 ;
  LAYER M2 ;
    RECT -0.05 -0.19 0.05 0.05 ;
  LAYER V1 ;
    RECT -0.035 -0.035 0.035 0.035 ;
    RECT -0.035 -0.175 0.035 -0.105 ;
END V1_5_X2S_VX

VIA V1_5_X3H_VX DEFAULT
  LAYER M1 ;
    RECT -0.185 -0.055 0.185 0.055 ;
  LAYER M2 ;
    RECT -0.19 -0.05 0.19 0.05 ;
  LAYER V1 ;
    RECT -0.175 -0.035 -0.105 0.035 ;
    RECT -0.035 -0.035 0.035 0.035 ;
    RECT 0.105 -0.035 0.175 0.035 ;
END V1_5_X3H_VX

VIA V1_5_X3E_VX DEFAULT
  LAYER M1 ;
    RECT -0.045 -0.055 0.325 0.055 ;
  LAYER M2 ;
    RECT -0.05 -0.05 0.33 0.05 ;
  LAYER V1 ;
    RECT -0.035 -0.035 0.035 0.035 ;
    RECT 0.105 -0.035 0.175 0.035 ;
    RECT 0.245 -0.035 0.315 0.035 ;
END V1_5_X3E_VX

VIA V1_5_X3W_VX DEFAULT
  LAYER M1 ;
    RECT -0.325 -0.055 0.045 0.055 ;
  LAYER M2 ;
    RECT -0.33 -0.05 0.05 0.05 ;
  LAYER V1 ;
    RECT -0.035 -0.035 0.035 0.035 ;
    RECT -0.175 -0.035 -0.105 0.035 ;
    RECT -0.315 -0.035 -0.245 0.035 ;
END V1_5_X3W_VX

VIA V1_5_X3V_VX DEFAULT
  LAYER M1 ;
    RECT -0.045 -0.195 0.045 0.195 ;
  LAYER M2 ;
    RECT -0.05 -0.19 0.05 0.19 ;
  LAYER V1 ;
    RECT -0.035 -0.175 0.035 -0.105 ;
    RECT -0.035 -0.035 0.035 0.035 ;
    RECT -0.035 0.105 0.035 0.175 ;
END V1_5_X3V_VX

VIA V1_5_X3N_VX DEFAULT
  LAYER M1 ;
    RECT -0.045 -0.055 0.045 0.335 ;
  LAYER M2 ;
    RECT -0.05 -0.05 0.05 0.33 ;
  LAYER V1 ;
    RECT -0.035 -0.035 0.035 0.035 ;
    RECT -0.035 0.105 0.035 0.175 ;
    RECT -0.035 0.245 0.035 0.315 ;
END V1_5_X3N_VX

VIA V1_5_X3S_VX DEFAULT
  LAYER M1 ;
    RECT -0.045 -0.335 0.045 0.055 ;
  LAYER M2 ;
    RECT -0.05 -0.33 0.05 0.05 ;
  LAYER V1 ;
    RECT -0.035 -0.035 0.035 0.035 ;
    RECT -0.035 -0.175 0.035 -0.105 ;
    RECT -0.035 -0.315 0.035 -0.245 ;
END V1_5_X3S_VX

VIA V1_5_X4H_VX DEFAULT
  LAYER M1 ;
    RECT -0.115 -0.125 0.115 0.125 ;
  LAYER M2 ;
    RECT -0.12 -0.12 0.12 0.12 ;
  LAYER V1 ;
    RECT -0.105 -0.105 -0.035 -0.035 ;
    RECT 0.035 -0.105 0.105 -0.035 ;
    RECT -0.105 0.035 -0.035 0.105 ;
    RECT 0.035 0.035 0.105 0.105 ;
END V1_5_X4H_VX

VIA V1_5_X4E_VX DEFAULT
  LAYER M1 ;
    RECT -0.045 -0.195 0.185 0.055 ;
  LAYER M2 ;
    RECT -0.05 -0.19 0.19 0.05 ;
  LAYER V1 ;
    RECT -0.035 -0.175 0.035 -0.105 ;
    RECT 0.105 -0.175 0.175 -0.105 ;
    RECT -0.035 -0.035 0.035 0.035 ;
    RECT 0.105 -0.035 0.175 0.035 ;
END V1_5_X4E_VX

VIA V1_5_X4W_VX DEFAULT
  LAYER M1 ;
    RECT -0.185 -0.055 0.045 0.195 ;
  LAYER M2 ;
    RECT -0.19 -0.05 0.05 0.19 ;
  LAYER V1 ;
    RECT -0.175 -0.035 -0.105 0.035 ;
    RECT -0.035 -0.035 0.035 0.035 ;
    RECT -0.175 0.105 -0.105 0.175 ;
    RECT -0.035 0.105 0.035 0.175 ;
END V1_5_X4W_VX

VIA V1_5_X4N_VX DEFAULT
  LAYER M1 ;
    RECT -0.045 -0.055 0.185 0.195 ;
  LAYER M2 ;
    RECT -0.05 -0.05 0.19 0.19 ;
  LAYER V1 ;
    RECT -0.035 -0.035 0.035 0.035 ;
    RECT 0.105 -0.035 0.175 0.035 ;
    RECT -0.035 0.105 0.035 0.175 ;
    RECT 0.105 0.105 0.175 0.175 ;
END V1_5_X4N_VX

VIA V1_5_X4S_VX DEFAULT
  LAYER M1 ;
    RECT -0.185 -0.195 0.045 0.055 ;
  LAYER M2 ;
    RECT -0.19 -0.19 0.05 0.05 ;
  LAYER V1 ;
    RECT -0.175 -0.175 -0.105 -0.105 ;
    RECT -0.035 -0.175 0.035 -0.105 ;
    RECT -0.175 -0.035 -0.105 0.035 ;
    RECT -0.035 -0.035 0.035 0.035 ;
END V1_5_X4S_VX

VIA V1_7_X2H_XH DEFAULT
  LAYER M1 ;
    RECT -0.12 -0.05 0.12 0.05 ;
  LAYER M2 ;
    RECT -0.125 -0.045 0.125 0.045 ;
  LAYER V1 ;
    RECT -0.105 -0.035 -0.035 0.035 ;
    RECT 0.035 -0.035 0.105 0.035 ;
END V1_7_X2H_XH

VIA V1_7_X2E_XH DEFAULT
  LAYER M1 ;
    RECT -0.05 -0.05 0.19 0.05 ;
  LAYER M2 ;
    RECT -0.055 -0.045 0.195 0.045 ;
  LAYER V1 ;
    RECT -0.035 -0.035 0.035 0.035 ;
    RECT 0.105 -0.035 0.175 0.035 ;
END V1_7_X2E_XH

VIA V1_7_X2W_XH DEFAULT
  LAYER M1 ;
    RECT -0.19 -0.05 0.05 0.05 ;
  LAYER M2 ;
    RECT -0.195 -0.045 0.055 0.045 ;
  LAYER V1 ;
    RECT -0.035 -0.035 0.035 0.035 ;
    RECT -0.175 -0.035 -0.105 0.035 ;
END V1_7_X2W_XH

VIA V1_7_X2V_XH DEFAULT
  LAYER M1 ;
    RECT -0.05 -0.12 0.05 0.12 ;
  LAYER M2 ;
    RECT -0.055 -0.115 0.055 0.115 ;
  LAYER V1 ;
    RECT -0.035 -0.105 0.035 -0.035 ;
    RECT -0.035 0.035 0.035 0.105 ;
END V1_7_X2V_XH

VIA V1_7_X2N_XH DEFAULT
  LAYER M1 ;
    RECT -0.05 -0.05 0.05 0.19 ;
  LAYER M2 ;
    RECT -0.055 -0.045 0.055 0.185 ;
  LAYER V1 ;
    RECT -0.035 -0.035 0.035 0.035 ;
    RECT -0.035 0.105 0.035 0.175 ;
END V1_7_X2N_XH

VIA V1_7_X2S_XH
  LAYER M1 ;
    RECT -0.05 -0.19 0.05 0.05 ;
  LAYER M2 ;
    RECT -0.055 -0.185 0.055 0.045 ;
  LAYER V1 ;
    RECT -0.035 -0.035 0.035 0.035 ;
    RECT -0.035 -0.175 0.035 -0.105 ;
END V1_7_X2S_XH

VIA V1_7_X3H_XH
  LAYER M1 ;
    RECT -0.19 -0.05 0.19 0.05 ;
  LAYER M2 ;
    RECT -0.195 -0.045 0.195 0.045 ;
  LAYER V1 ;
    RECT -0.175 -0.035 -0.105 0.035 ;
    RECT -0.035 -0.035 0.035 0.035 ;
    RECT 0.105 -0.035 0.175 0.035 ;
END V1_7_X3H_XH

VIA V1_7_X3E_XH
  LAYER M1 ;
    RECT -0.05 -0.05 0.33 0.05 ;
  LAYER M2 ;
    RECT -0.055 -0.045 0.335 0.045 ;
  LAYER V1 ;
    RECT -0.035 -0.035 0.035 0.035 ;
    RECT 0.105 -0.035 0.175 0.035 ;
    RECT 0.245 -0.035 0.315 0.035 ;
END V1_7_X3E_XH

VIA V1_7_X3W_XH
  LAYER M1 ;
    RECT -0.33 -0.05 0.05 0.05 ;
  LAYER M2 ;
    RECT -0.335 -0.045 0.055 0.045 ;
  LAYER V1 ;
    RECT -0.035 -0.035 0.035 0.035 ;
    RECT -0.175 -0.035 -0.105 0.035 ;
    RECT -0.315 -0.035 -0.245 0.035 ;
END V1_7_X3W_XH

VIA V1_7_X3V_XH
  LAYER M1 ;
    RECT -0.05 -0.19 0.05 0.19 ;
  LAYER M2 ;
    RECT -0.055 -0.185 0.055 0.185 ;
  LAYER V1 ;
    RECT -0.035 -0.175 0.035 -0.105 ;
    RECT -0.035 -0.035 0.035 0.035 ;
    RECT -0.035 0.105 0.035 0.175 ;
END V1_7_X3V_XH

VIA V1_7_X3N_XH
  LAYER M1 ;
    RECT -0.05 -0.05 0.05 0.33 ;
  LAYER M2 ;
    RECT -0.055 -0.045 0.055 0.325 ;
  LAYER V1 ;
    RECT -0.035 -0.035 0.035 0.035 ;
    RECT -0.035 0.105 0.035 0.175 ;
    RECT -0.035 0.245 0.035 0.315 ;
END V1_7_X3N_XH

VIA V1_7_X3S_XH
  LAYER M1 ;
    RECT -0.05 -0.33 0.05 0.05 ;
  LAYER M2 ;
    RECT -0.055 -0.325 0.055 0.045 ;
  LAYER V1 ;
    RECT -0.035 -0.035 0.035 0.035 ;
    RECT -0.035 -0.175 0.035 -0.105 ;
    RECT -0.035 -0.315 0.035 -0.245 ;
END V1_7_X3S_XH

VIA V1_7_X4H_XH
  LAYER M1 ;
    RECT -0.12 -0.12 0.12 0.12 ;
  LAYER M2 ;
    RECT -0.125 -0.115 0.125 0.115 ;
  LAYER V1 ;
    RECT -0.105 -0.105 -0.035 -0.035 ;
    RECT 0.035 -0.105 0.105 -0.035 ;
    RECT -0.105 0.035 -0.035 0.105 ;
    RECT 0.035 0.035 0.105 0.105 ;
END V1_7_X4H_XH

VIA V1_7_X4E_XH
  LAYER M1 ;
    RECT -0.05 -0.19 0.19 0.05 ;
  LAYER M2 ;
    RECT -0.055 -0.185 0.195 0.045 ;
  LAYER V1 ;
    RECT -0.035 -0.175 0.035 -0.105 ;
    RECT 0.105 -0.175 0.175 -0.105 ;
    RECT -0.035 -0.035 0.035 0.035 ;
    RECT 0.105 -0.035 0.175 0.035 ;
END V1_7_X4E_XH

VIA V1_7_X4W_XH
  LAYER M1 ;
    RECT -0.19 -0.05 0.05 0.19 ;
  LAYER M2 ;
    RECT -0.195 -0.045 0.055 0.185 ;
  LAYER V1 ;
    RECT -0.175 -0.035 -0.105 0.035 ;
    RECT -0.035 -0.035 0.035 0.035 ;
    RECT -0.175 0.105 -0.105 0.175 ;
    RECT -0.035 0.105 0.035 0.175 ;
END V1_7_X4W_XH

VIA V1_7_X4N_XH
  LAYER M1 ;
    RECT -0.05 -0.05 0.19 0.19 ;
  LAYER M2 ;
    RECT -0.055 -0.045 0.195 0.185 ;
  LAYER V1 ;
    RECT -0.035 -0.035 0.035 0.035 ;
    RECT 0.105 -0.035 0.175 0.035 ;
    RECT -0.035 0.105 0.035 0.175 ;
    RECT 0.105 0.105 0.175 0.175 ;
END V1_7_X4N_XH

VIA V1_7_X4S_XH
  LAYER M1 ;
    RECT -0.19 -0.19 0.05 0.05 ;
  LAYER M2 ;
    RECT -0.195 -0.185 0.055 0.045 ;
  LAYER V1 ;
    RECT -0.175 -0.175 -0.105 -0.105 ;
    RECT -0.035 -0.175 0.035 -0.105 ;
    RECT -0.175 -0.035 -0.105 0.035 ;
    RECT -0.035 -0.035 0.035 0.035 ;
END V1_7_X4S_XH

VIA V1_8_X2H_XX
  LAYER M1 ;
    RECT -0.12 -0.05 0.12 0.05 ;
  LAYER M2 ;
    RECT -0.12 -0.05 0.12 0.05 ;
  LAYER V1 ;
    RECT -0.105 -0.035 -0.035 0.035 ;
    RECT 0.035 -0.035 0.105 0.035 ;
END V1_8_X2H_XX

VIA V1_8_X2E_XX
  LAYER M1 ;
    RECT -0.05 -0.05 0.19 0.05 ;
  LAYER M2 ;
    RECT -0.05 -0.05 0.19 0.05 ;
  LAYER V1 ;
    RECT -0.035 -0.035 0.035 0.035 ;
    RECT 0.105 -0.035 0.175 0.035 ;
END V1_8_X2E_XX

VIA V1_8_X2W_XX
  LAYER M1 ;
    RECT -0.19 -0.05 0.05 0.05 ;
  LAYER M2 ;
    RECT -0.19 -0.05 0.05 0.05 ;
  LAYER V1 ;
    RECT -0.035 -0.035 0.035 0.035 ;
    RECT -0.175 -0.035 -0.105 0.035 ;
END V1_8_X2W_XX

VIA V1_8_X2V_XX
  LAYER M1 ;
    RECT -0.05 -0.12 0.05 0.12 ;
  LAYER M2 ;
    RECT -0.05 -0.12 0.05 0.12 ;
  LAYER V1 ;
    RECT -0.035 -0.105 0.035 -0.035 ;
    RECT -0.035 0.035 0.035 0.105 ;
END V1_8_X2V_XX

VIA V1_8_X2N_XX
  LAYER M1 ;
    RECT -0.05 -0.05 0.05 0.19 ;
  LAYER M2 ;
    RECT -0.05 -0.05 0.05 0.19 ;
  LAYER V1 ;
    RECT -0.035 -0.035 0.035 0.035 ;
    RECT -0.035 0.105 0.035 0.175 ;
END V1_8_X2N_XX

VIA V1_8_X2S_XX
  LAYER M1 ;
    RECT -0.05 -0.19 0.05 0.05 ;
  LAYER M2 ;
    RECT -0.05 -0.19 0.05 0.05 ;
  LAYER V1 ;
    RECT -0.035 -0.035 0.035 0.035 ;
    RECT -0.035 -0.175 0.035 -0.105 ;
END V1_8_X2S_XX

VIA V1_8_X3H_XX
  LAYER M1 ;
    RECT -0.19 -0.05 0.19 0.05 ;
  LAYER M2 ;
    RECT -0.19 -0.05 0.19 0.05 ;
  LAYER V1 ;
    RECT -0.175 -0.035 -0.105 0.035 ;
    RECT -0.035 -0.035 0.035 0.035 ;
    RECT 0.105 -0.035 0.175 0.035 ;
END V1_8_X3H_XX

VIA V1_8_X3E_XX
  LAYER M1 ;
    RECT -0.05 -0.05 0.33 0.05 ;
  LAYER M2 ;
    RECT -0.05 -0.05 0.33 0.05 ;
  LAYER V1 ;
    RECT -0.035 -0.035 0.035 0.035 ;
    RECT 0.105 -0.035 0.175 0.035 ;
    RECT 0.245 -0.035 0.315 0.035 ;
END V1_8_X3E_XX

VIA V1_8_X3W_XX
  LAYER M1 ;
    RECT -0.33 -0.05 0.05 0.05 ;
  LAYER M2 ;
    RECT -0.33 -0.05 0.05 0.05 ;
  LAYER V1 ;
    RECT -0.035 -0.035 0.035 0.035 ;
    RECT -0.175 -0.035 -0.105 0.035 ;
    RECT -0.315 -0.035 -0.245 0.035 ;
END V1_8_X3W_XX

VIA V1_8_X3V_XX
  LAYER M1 ;
    RECT -0.05 -0.19 0.05 0.19 ;
  LAYER M2 ;
    RECT -0.05 -0.19 0.05 0.19 ;
  LAYER V1 ;
    RECT -0.035 -0.175 0.035 -0.105 ;
    RECT -0.035 -0.035 0.035 0.035 ;
    RECT -0.035 0.105 0.035 0.175 ;
END V1_8_X3V_XX

VIA V1_8_X3N_XX
  LAYER M1 ;
    RECT -0.05 -0.05 0.05 0.33 ;
  LAYER M2 ;
    RECT -0.05 -0.05 0.05 0.33 ;
  LAYER V1 ;
    RECT -0.035 -0.035 0.035 0.035 ;
    RECT -0.035 0.105 0.035 0.175 ;
    RECT -0.035 0.245 0.035 0.315 ;
END V1_8_X3N_XX

VIA V1_8_X3S_XX
  LAYER M1 ;
    RECT -0.05 -0.33 0.05 0.05 ;
  LAYER M2 ;
    RECT -0.05 -0.33 0.05 0.05 ;
  LAYER V1 ;
    RECT -0.035 -0.035 0.035 0.035 ;
    RECT -0.035 -0.175 0.035 -0.105 ;
    RECT -0.035 -0.315 0.035 -0.245 ;
END V1_8_X3S_XX

VIA V1_8_X4H_XX
  LAYER M1 ;
    RECT -0.12 -0.12 0.12 0.12 ;
  LAYER M2 ;
    RECT -0.12 -0.12 0.12 0.12 ;
  LAYER V1 ;
    RECT -0.105 -0.105 -0.035 -0.035 ;
    RECT 0.035 -0.105 0.105 -0.035 ;
    RECT -0.105 0.035 -0.035 0.105 ;
    RECT 0.035 0.035 0.105 0.105 ;
END V1_8_X4H_XX

VIA V1_8_X4E_XX
  LAYER M1 ;
    RECT -0.05 -0.19 0.19 0.05 ;
  LAYER M2 ;
    RECT -0.05 -0.19 0.19 0.05 ;
  LAYER V1 ;
    RECT -0.035 -0.175 0.035 -0.105 ;
    RECT 0.105 -0.175 0.175 -0.105 ;
    RECT -0.035 -0.035 0.035 0.035 ;
    RECT 0.105 -0.035 0.175 0.035 ;
END V1_8_X4E_XX

VIA V1_8_X4W_XX
  LAYER M1 ;
    RECT -0.19 -0.05 0.05 0.19 ;
  LAYER M2 ;
    RECT -0.19 -0.05 0.05 0.19 ;
  LAYER V1 ;
    RECT -0.175 -0.035 -0.105 0.035 ;
    RECT -0.035 -0.035 0.035 0.035 ;
    RECT -0.175 0.105 -0.105 0.175 ;
    RECT -0.035 0.105 0.035 0.175 ;
END V1_8_X4W_XX

VIA V1_8_X4N_XX
  LAYER M1 ;
    RECT -0.05 -0.05 0.19 0.19 ;
  LAYER M2 ;
    RECT -0.05 -0.05 0.19 0.19 ;
  LAYER V1 ;
    RECT -0.035 -0.035 0.035 0.035 ;
    RECT 0.105 -0.035 0.175 0.035 ;
    RECT -0.035 0.105 0.035 0.175 ;
    RECT 0.105 0.105 0.175 0.175 ;
END V1_8_X4N_XX

VIA V1_8_X4S_XX
  LAYER M1 ;
    RECT -0.19 -0.19 0.05 0.05 ;
  LAYER M2 ;
    RECT -0.19 -0.19 0.05 0.05 ;
  LAYER V1 ;
    RECT -0.175 -0.175 -0.105 -0.105 ;
    RECT -0.035 -0.175 0.035 -0.105 ;
    RECT -0.175 -0.035 -0.105 0.035 ;
    RECT -0.035 -0.035 0.035 0.035 ;
END V1_8_X4S_XX

VIA V2_0_HV DEFAULT
  LAYER M2 ;
    RECT -0.065 -0.035 0.065 0.035 ;
  LAYER M3 ;
    RECT -0.035 -0.065 0.035 0.065 ;
  LAYER V2 ;
    RECT -0.035 -0.035 0.035 0.035 ;
END V2_0_HV

VIA V2_0_HV_S1 DEFAULT
  LAYER M2 ;
    RECT -0.065 -0.035 0.215 0.035 ;
  LAYER M3 ;
    RECT -0.035 -0.065 0.035 0.065 ;
  LAYER V2 ;
    RECT -0.035 -0.035 0.035 0.035 ;
END V2_0_HV_S1

VIA V2_0_HV_S2 DEFAULT
  LAYER M2 ;
    RECT -0.215 -0.035 0.065 0.035 ;
  LAYER M3 ;
    RECT -0.035 -0.065 0.035 0.065 ;
  LAYER V2 ;
    RECT -0.035 -0.035 0.035 0.035 ;
END V2_0_HV_S2

VIA V2_0_VV DEFAULT
  LAYER M2 ;
    RECT -0.035 -0.065 0.035 0.065 ;
  LAYER M3 ;
    RECT -0.035 -0.065 0.035 0.065 ;
  LAYER V2 ;
    RECT -0.035 -0.035 0.035 0.035 ;
END V2_0_VV

VIA V2_0_HH DEFAULT
  LAYER M2 ;
    RECT -0.065 -0.035 0.065 0.035 ;
  LAYER M3 ;
    RECT -0.065 -0.035 0.065 0.035 ;
  LAYER V2 ;
    RECT -0.035 -0.035 0.035 0.035 ;
END V2_0_HH

VIA V2_0_VH DEFAULT
  LAYER M2 ;
    RECT -0.035 -0.065 0.035 0.065 ;
  LAYER M3 ;
    RECT -0.065 -0.035 0.065 0.035 ;
  LAYER V2 ;
    RECT -0.035 -0.035 0.035 0.035 ;
END V2_0_VH

VIA V2_1_HV DEFAULT
  LAYER M2 ;
    RECT -0.065 -0.035 0.065 0.035 ;
  LAYER M3 ;
    RECT -0.045 -0.055 0.045 0.055 ;
  LAYER V2 ;
    RECT -0.035 -0.035 0.035 0.035 ;
END V2_1_HV

VIA V2_1_HV_S1 DEFAULT
  LAYER M2 ;
    RECT -0.065 -0.035 0.215 0.035 ;
  LAYER M3 ;
    RECT -0.045 -0.055 0.045 0.055 ;
  LAYER V2 ;
    RECT -0.035 -0.035 0.035 0.035 ;
END V2_1_HV_S1

VIA V2_1_HV_S2 DEFAULT
  LAYER M2 ;
    RECT -0.215 -0.035 0.065 0.035 ;
  LAYER M3 ;
    RECT -0.045 -0.055 0.045 0.055 ;
  LAYER V2 ;
    RECT -0.035 -0.035 0.035 0.035 ;
END V2_1_HV_S2

VIA V2_1_VV DEFAULT
  LAYER M2 ;
    RECT -0.035 -0.065 0.035 0.065 ;
  LAYER M3 ;
    RECT -0.045 -0.055 0.045 0.055 ;
  LAYER V2 ;
    RECT -0.035 -0.035 0.035 0.035 ;
END V2_1_VV

VIA V2_1_HH DEFAULT
  LAYER M2 ;
    RECT -0.065 -0.035 0.065 0.035 ;
  LAYER M3 ;
    RECT -0.055 -0.045 0.055 0.045 ;
  LAYER V2 ;
    RECT -0.035 -0.035 0.035 0.035 ;
END V2_1_HH

VIA V2_1_VH DEFAULT
  LAYER M2 ;
    RECT -0.035 -0.065 0.035 0.065 ;
  LAYER M3 ;
    RECT -0.055 -0.045 0.055 0.045 ;
  LAYER V2 ;
    RECT -0.035 -0.035 0.035 0.035 ;
END V2_1_VH

VIA V2_2_HX DEFAULT
  LAYER M2 ;
    RECT -0.065 -0.035 0.065 0.035 ;
  LAYER M3 ;
    RECT -0.05 -0.05 0.05 0.05 ;
  LAYER V2 ;
    RECT -0.035 -0.035 0.035 0.035 ;
END V2_2_HX

VIA V2_2_HX_S1 DEFAULT
  LAYER M2 ;
    RECT -0.065 -0.035 0.215 0.035 ;
  LAYER M3 ;
    RECT -0.05 -0.05 0.05 0.05 ;
  LAYER V2 ;
    RECT -0.035 -0.035 0.035 0.035 ;
END V2_2_HX_S1

VIA V2_2_HX_S2 DEFAULT
  LAYER M2 ;
    RECT -0.215 -0.035 0.065 0.035 ;
  LAYER M3 ;
    RECT -0.05 -0.05 0.05 0.05 ;
  LAYER V2 ;
    RECT -0.035 -0.035 0.035 0.035 ;
END V2_2_HX_S2

VIA V2_2_VX DEFAULT
  LAYER M2 ;
    RECT -0.035 -0.065 0.035 0.065 ;
  LAYER M3 ;
    RECT -0.05 -0.05 0.05 0.05 ;
  LAYER V2 ;
    RECT -0.035 -0.035 0.035 0.035 ;
END V2_2_VX

VIA V2_3_HV DEFAULT
  LAYER M2 ;
    RECT -0.055 -0.045 0.055 0.045 ;
  LAYER M3 ;
    RECT -0.035 -0.065 0.035 0.065 ;
  LAYER V2 ;
    RECT -0.035 -0.035 0.035 0.035 ;
END V2_3_HV

VIA V2_3_HV_S1 DEFAULT
  LAYER M2 ;
    RECT -0.055 -0.045 0.163 0.045 ;
  LAYER M3 ;
    RECT -0.035 -0.065 0.035 0.065 ;
  LAYER V2 ;
    RECT -0.035 -0.035 0.035 0.035 ;
END V2_3_HV_S1

VIA V2_3_HV_S2 DEFAULT
  LAYER M2 ;
    RECT -0.163 -0.045 0.055 0.045 ;
  LAYER M3 ;
    RECT -0.035 -0.065 0.035 0.065 ;
  LAYER V2 ;
    RECT -0.035 -0.035 0.035 0.035 ;
END V2_3_HV_S2

VIA V2_3_VV DEFAULT
  LAYER M2 ;
    RECT -0.045 -0.055 0.045 0.055 ;
  LAYER M3 ;
    RECT -0.035 -0.065 0.035 0.065 ;
  LAYER V2 ;
    RECT -0.035 -0.035 0.035 0.035 ;
END V2_3_VV

VIA V2_3_HH DEFAULT
  LAYER M2 ;
    RECT -0.055 -0.045 0.055 0.045 ;
  LAYER M3 ;
    RECT -0.065 -0.035 0.065 0.035 ;
  LAYER V2 ;
    RECT -0.035 -0.035 0.035 0.035 ;
END V2_3_HH

VIA V2_3_VH DEFAULT
  LAYER M2 ;
    RECT -0.045 -0.055 0.045 0.055 ;
  LAYER M3 ;
    RECT -0.065 -0.035 0.065 0.035 ;
  LAYER V2 ;
    RECT -0.035 -0.035 0.035 0.035 ;
END V2_3_VH

VIA V2_4_HV DEFAULT
  LAYER M2 ;
    RECT -0.055 -0.045 0.055 0.045 ;
  LAYER M3 ;
    RECT -0.045 -0.055 0.045 0.055 ;
  LAYER V2 ;
    RECT -0.035 -0.035 0.035 0.035 ;
END V2_4_HV

VIA V2_4_HV_S1 DEFAULT
  LAYER M2 ;
    RECT -0.055 -0.045 0.163 0.045 ;
  LAYER M3 ;
    RECT -0.045 -0.055 0.045 0.055 ;
  LAYER V2 ;
    RECT -0.035 -0.035 0.035 0.035 ;
END V2_4_HV_S1

VIA V2_4_HV_S2 DEFAULT
  LAYER M2 ;
    RECT -0.163 -0.045 0.055 0.045 ;
  LAYER M3 ;
    RECT -0.045 -0.055 0.045 0.055 ;
  LAYER V2 ;
    RECT -0.035 -0.035 0.035 0.035 ;
END V2_4_HV_S2

VIA V2_4_VV DEFAULT
  LAYER M2 ;
    RECT -0.045 -0.055 0.045 0.055 ;
  LAYER M3 ;
    RECT -0.045 -0.055 0.045 0.055 ;
  LAYER V2 ;
    RECT -0.035 -0.035 0.035 0.035 ;
END V2_4_VV

VIA V2_4_HH DEFAULT
  LAYER M2 ;
    RECT -0.055 -0.045 0.055 0.045 ;
  LAYER M3 ;
    RECT -0.055 -0.045 0.055 0.045 ;
  LAYER V2 ;
    RECT -0.035 -0.035 0.035 0.035 ;
END V2_4_HH

VIA V2_4_VH DEFAULT
  LAYER M2 ;
    RECT -0.045 -0.055 0.045 0.055 ;
  LAYER M3 ;
    RECT -0.055 -0.045 0.055 0.045 ;
  LAYER V2 ;
    RECT -0.035 -0.035 0.035 0.035 ;
END V2_4_VH

VIA V2_5_HX DEFAULT
  LAYER M2 ;
    RECT -0.055 -0.045 0.055 0.045 ;
  LAYER M3 ;
    RECT -0.05 -0.05 0.05 0.05 ;
  LAYER V2 ;
    RECT -0.035 -0.035 0.035 0.035 ;
END V2_5_HX

VIA V2_5_HX_S1 DEFAULT
  LAYER M2 ;
    RECT -0.055 -0.045 0.163 0.045 ;
  LAYER M3 ;
    RECT -0.05 -0.05 0.05 0.05 ;
  LAYER V2 ;
    RECT -0.035 -0.035 0.035 0.035 ;
END V2_5_HX_S1

VIA V2_5_HX_S2 DEFAULT
  LAYER M2 ;
    RECT -0.163 -0.045 0.055 0.045 ;
  LAYER M3 ;
    RECT -0.05 -0.05 0.05 0.05 ;
  LAYER V2 ;
    RECT -0.035 -0.035 0.035 0.035 ;
END V2_5_HX_S2

VIA V2_5_VX DEFAULT
  LAYER M2 ;
    RECT -0.045 -0.055 0.045 0.055 ;
  LAYER M3 ;
    RECT -0.05 -0.05 0.05 0.05 ;
  LAYER V2 ;
    RECT -0.035 -0.035 0.035 0.035 ;
END V2_5_VX

VIA V2_6_XV DEFAULT
  LAYER M2 ;
    RECT -0.05 -0.05 0.05 0.05 ;
  LAYER M3 ;
    RECT -0.035 -0.065 0.035 0.065 ;
  LAYER V2 ;
    RECT -0.035 -0.035 0.035 0.035 ;
END V2_6_XV

VIA V2_6_XV_S1 DEFAULT
  LAYER M2 ;
    RECT -0.05 -0.05 0.146 0.05 ;
  LAYER M3 ;
    RECT -0.035 -0.065 0.035 0.065 ;
  LAYER V2 ;
    RECT -0.035 -0.035 0.035 0.035 ;
END V2_6_XV_S1

VIA V2_6_XV_S2 DEFAULT
  LAYER M2 ;
    RECT -0.146 -0.05 0.05 0.05 ;
  LAYER M3 ;
    RECT -0.035 -0.065 0.035 0.065 ;
  LAYER V2 ;
    RECT -0.035 -0.035 0.035 0.035 ;
END V2_6_XV_S2

VIA V2_6_XH DEFAULT
  LAYER M2 ;
    RECT -0.05 -0.05 0.05 0.05 ;
  LAYER M3 ;
    RECT -0.065 -0.035 0.065 0.035 ;
  LAYER V2 ;
    RECT -0.035 -0.035 0.035 0.035 ;
END V2_6_XH

VIA V2_7_XV DEFAULT
  LAYER M2 ;
    RECT -0.05 -0.05 0.05 0.05 ;
  LAYER M3 ;
    RECT -0.045 -0.055 0.045 0.055 ;
  LAYER V2 ;
    RECT -0.035 -0.035 0.035 0.035 ;
END V2_7_XV

VIA V2_7_XV_S1 DEFAULT
  LAYER M2 ;
    RECT -0.05 -0.05 0.146 0.05 ;
  LAYER M3 ;
    RECT -0.045 -0.055 0.045 0.055 ;
  LAYER V2 ;
    RECT -0.035 -0.035 0.035 0.035 ;
END V2_7_XV_S1

VIA V2_7_XV_S2 DEFAULT
  LAYER M2 ;
    RECT -0.146 -0.05 0.05 0.05 ;
  LAYER M3 ;
    RECT -0.045 -0.055 0.045 0.055 ;
  LAYER V2 ;
    RECT -0.035 -0.035 0.035 0.035 ;
END V2_7_XV_S2

VIA V2_7_XH DEFAULT
  LAYER M2 ;
    RECT -0.05 -0.05 0.05 0.05 ;
  LAYER M3 ;
    RECT -0.055 -0.045 0.055 0.045 ;
  LAYER V2 ;
    RECT -0.035 -0.035 0.035 0.035 ;
END V2_7_XH

VIA V2_8_XX DEFAULT
  LAYER M2 ;
    RECT -0.05 -0.05 0.05 0.05 ;
  LAYER M3 ;
    RECT -0.05 -0.05 0.05 0.05 ;
  LAYER V2 ;
    RECT -0.035 -0.035 0.035 0.035 ;
END V2_8_XX

VIA V2_8_XX_S1 DEFAULT
  LAYER M2 ;
    RECT -0.05 -0.05 0.146 0.05 ;
  LAYER M3 ;
    RECT -0.05 -0.05 0.05 0.05 ;
  LAYER V2 ;
    RECT -0.035 -0.035 0.035 0.035 ;
END V2_8_XX_S1

VIA V2_8_XX_S2 DEFAULT
  LAYER M2 ;
    RECT -0.146 -0.05 0.05 0.05 ;
  LAYER M3 ;
    RECT -0.05 -0.05 0.05 0.05 ;
  LAYER V2 ;
    RECT -0.035 -0.035 0.035 0.035 ;
END V2_8_XX_S2

VIA V2_4_X2H_HV DEFAULT
  LAYER M2 ;
    RECT -0.125 -0.045 0.125 0.045 ;
  LAYER M3 ;
    RECT -0.115 -0.055 0.115 0.055 ;
  LAYER V2 ;
    RECT -0.105 -0.035 -0.035 0.035 ;
    RECT 0.035 -0.035 0.105 0.035 ;
END V2_4_X2H_HV

VIA V2_4_X2E_HV DEFAULT
  LAYER M2 ;
    RECT -0.055 -0.045 0.195 0.045 ;
  LAYER M3 ;
    RECT -0.045 -0.055 0.185 0.055 ;
  LAYER V2 ;
    RECT -0.035 -0.035 0.035 0.035 ;
    RECT 0.105 -0.035 0.175 0.035 ;
END V2_4_X2E_HV

VIA V2_4_X2W_HV DEFAULT
  LAYER M2 ;
    RECT -0.195 -0.045 0.055 0.045 ;
  LAYER M3 ;
    RECT -0.185 -0.055 0.045 0.055 ;
  LAYER V2 ;
    RECT -0.035 -0.035 0.035 0.035 ;
    RECT -0.175 -0.035 -0.105 0.035 ;
END V2_4_X2W_HV

VIA V2_4_X2V_HV DEFAULT
  LAYER M2 ;
    RECT -0.055 -0.115 0.055 0.115 ;
  LAYER M3 ;
    RECT -0.045 -0.125 0.045 0.125 ;
  LAYER V2 ;
    RECT -0.035 -0.105 0.035 -0.035 ;
    RECT -0.035 0.035 0.035 0.105 ;
END V2_4_X2V_HV

VIA V2_4_X2N_HV DEFAULT
  LAYER M2 ;
    RECT -0.055 -0.045 0.055 0.185 ;
  LAYER M3 ;
    RECT -0.045 -0.055 0.045 0.195 ;
  LAYER V2 ;
    RECT -0.035 -0.035 0.035 0.035 ;
    RECT -0.035 0.105 0.035 0.175 ;
END V2_4_X2N_HV

VIA V2_4_X2S_HV DEFAULT
  LAYER M2 ;
    RECT -0.055 -0.185 0.055 0.045 ;
  LAYER M3 ;
    RECT -0.045 -0.195 0.045 0.055 ;
  LAYER V2 ;
    RECT -0.035 -0.035 0.035 0.035 ;
    RECT -0.035 -0.175 0.035 -0.105 ;
END V2_4_X2S_HV

VIA V2_4_X3H_HV DEFAULT
  LAYER M2 ;
    RECT -0.195 -0.045 0.195 0.045 ;
  LAYER M3 ;
    RECT -0.185 -0.055 0.185 0.055 ;
  LAYER V2 ;
    RECT -0.175 -0.035 -0.105 0.035 ;
    RECT -0.035 -0.035 0.035 0.035 ;
    RECT 0.105 -0.035 0.175 0.035 ;
END V2_4_X3H_HV

VIA V2_4_X3E_HV DEFAULT
  LAYER M2 ;
    RECT -0.055 -0.045 0.335 0.045 ;
  LAYER M3 ;
    RECT -0.045 -0.055 0.325 0.055 ;
  LAYER V2 ;
    RECT -0.035 -0.035 0.035 0.035 ;
    RECT 0.105 -0.035 0.175 0.035 ;
    RECT 0.245 -0.035 0.315 0.035 ;
END V2_4_X3E_HV

VIA V2_4_X3W_HV DEFAULT
  LAYER M2 ;
    RECT -0.335 -0.045 0.055 0.045 ;
  LAYER M3 ;
    RECT -0.325 -0.055 0.045 0.055 ;
  LAYER V2 ;
    RECT -0.035 -0.035 0.035 0.035 ;
    RECT -0.175 -0.035 -0.105 0.035 ;
    RECT -0.315 -0.035 -0.245 0.035 ;
END V2_4_X3W_HV

VIA V2_4_X3V_HV DEFAULT
  LAYER M2 ;
    RECT -0.055 -0.185 0.055 0.185 ;
  LAYER M3 ;
    RECT -0.045 -0.195 0.045 0.195 ;
  LAYER V2 ;
    RECT -0.035 -0.175 0.035 -0.105 ;
    RECT -0.035 -0.035 0.035 0.035 ;
    RECT -0.035 0.105 0.035 0.175 ;
END V2_4_X3V_HV

VIA V2_4_X3N_HV DEFAULT
  LAYER M2 ;
    RECT -0.055 -0.045 0.055 0.325 ;
  LAYER M3 ;
    RECT -0.045 -0.055 0.045 0.335 ;
  LAYER V2 ;
    RECT -0.035 -0.035 0.035 0.035 ;
    RECT -0.035 0.105 0.035 0.175 ;
    RECT -0.035 0.245 0.035 0.315 ;
END V2_4_X3N_HV

VIA V2_4_X3S_HV DEFAULT
  LAYER M2 ;
    RECT -0.055 -0.325 0.055 0.045 ;
  LAYER M3 ;
    RECT -0.045 -0.335 0.045 0.055 ;
  LAYER V2 ;
    RECT -0.035 -0.035 0.035 0.035 ;
    RECT -0.035 -0.175 0.035 -0.105 ;
    RECT -0.035 -0.315 0.035 -0.245 ;
END V2_4_X3S_HV

VIA V2_4_X4H_HV DEFAULT
  LAYER M2 ;
    RECT -0.125 -0.115 0.125 0.115 ;
  LAYER M3 ;
    RECT -0.115 -0.125 0.115 0.125 ;
  LAYER V2 ;
    RECT -0.105 -0.105 -0.035 -0.035 ;
    RECT 0.035 -0.105 0.105 -0.035 ;
    RECT -0.105 0.035 -0.035 0.105 ;
    RECT 0.035 0.035 0.105 0.105 ;
END V2_4_X4H_HV

VIA V2_4_X4E_HV DEFAULT
  LAYER M2 ;
    RECT -0.055 -0.185 0.195 0.045 ;
  LAYER M3 ;
    RECT -0.045 -0.195 0.185 0.055 ;
  LAYER V2 ;
    RECT -0.035 -0.175 0.035 -0.105 ;
    RECT 0.105 -0.175 0.175 -0.105 ;
    RECT -0.035 -0.035 0.035 0.035 ;
    RECT 0.105 -0.035 0.175 0.035 ;
END V2_4_X4E_HV

VIA V2_4_X4W_HV DEFAULT
  LAYER M2 ;
    RECT -0.195 -0.045 0.055 0.185 ;
  LAYER M3 ;
    RECT -0.185 -0.055 0.045 0.195 ;
  LAYER V2 ;
    RECT -0.175 -0.035 -0.105 0.035 ;
    RECT -0.035 -0.035 0.035 0.035 ;
    RECT -0.175 0.105 -0.105 0.175 ;
    RECT -0.035 0.105 0.035 0.175 ;
END V2_4_X4W_HV

VIA V2_4_X4N_HV DEFAULT
  LAYER M2 ;
    RECT -0.055 -0.045 0.195 0.185 ;
  LAYER M3 ;
    RECT -0.045 -0.055 0.185 0.195 ;
  LAYER V2 ;
    RECT -0.035 -0.035 0.035 0.035 ;
    RECT 0.105 -0.035 0.175 0.035 ;
    RECT -0.035 0.105 0.035 0.175 ;
    RECT 0.105 0.105 0.175 0.175 ;
END V2_4_X4N_HV

VIA V2_4_X4S_HV DEFAULT
  LAYER M2 ;
    RECT -0.195 -0.185 0.055 0.045 ;
  LAYER M3 ;
    RECT -0.185 -0.195 0.045 0.055 ;
  LAYER V2 ;
    RECT -0.175 -0.175 -0.105 -0.105 ;
    RECT -0.035 -0.175 0.035 -0.105 ;
    RECT -0.175 -0.035 -0.105 0.035 ;
    RECT -0.035 -0.035 0.035 0.035 ;
END V2_4_X4S_HV

VIA V2_5_X2H_HX DEFAULT
  LAYER M2 ;
    RECT -0.125 -0.045 0.125 0.045 ;
  LAYER M3 ;
    RECT -0.12 -0.05 0.12 0.05 ;
  LAYER V2 ;
    RECT -0.105 -0.035 -0.035 0.035 ;
    RECT 0.035 -0.035 0.105 0.035 ;
END V2_5_X2H_HX

VIA V2_5_X2E_HX DEFAULT
  LAYER M2 ;
    RECT -0.055 -0.045 0.195 0.045 ;
  LAYER M3 ;
    RECT -0.05 -0.05 0.19 0.05 ;
  LAYER V2 ;
    RECT -0.035 -0.035 0.035 0.035 ;
    RECT 0.105 -0.035 0.175 0.035 ;
END V2_5_X2E_HX

VIA V2_5_X2W_HX DEFAULT
  LAYER M2 ;
    RECT -0.195 -0.045 0.055 0.045 ;
  LAYER M3 ;
    RECT -0.19 -0.05 0.05 0.05 ;
  LAYER V2 ;
    RECT -0.035 -0.035 0.035 0.035 ;
    RECT -0.175 -0.035 -0.105 0.035 ;
END V2_5_X2W_HX

VIA V2_5_X2V_HX DEFAULT
  LAYER M2 ;
    RECT -0.055 -0.115 0.055 0.115 ;
  LAYER M3 ;
    RECT -0.05 -0.12 0.05 0.12 ;
  LAYER V2 ;
    RECT -0.035 -0.105 0.035 -0.035 ;
    RECT -0.035 0.035 0.035 0.105 ;
END V2_5_X2V_HX

VIA V2_5_X2N_HX
  LAYER M2 ;
    RECT -0.055 -0.045 0.055 0.185 ;
  LAYER M3 ;
    RECT -0.05 -0.05 0.05 0.19 ;
  LAYER V2 ;
    RECT -0.035 -0.035 0.035 0.035 ;
    RECT -0.035 0.105 0.035 0.175 ;
END V2_5_X2N_HX

VIA V2_5_X2S_HX
  LAYER M2 ;
    RECT -0.055 -0.185 0.055 0.045 ;
  LAYER M3 ;
    RECT -0.05 -0.19 0.05 0.05 ;
  LAYER V2 ;
    RECT -0.035 -0.035 0.035 0.035 ;
    RECT -0.035 -0.175 0.035 -0.105 ;
END V2_5_X2S_HX

VIA V2_5_X3H_HX
  LAYER M2 ;
    RECT -0.195 -0.045 0.195 0.045 ;
  LAYER M3 ;
    RECT -0.19 -0.05 0.19 0.05 ;
  LAYER V2 ;
    RECT -0.175 -0.035 -0.105 0.035 ;
    RECT -0.035 -0.035 0.035 0.035 ;
    RECT 0.105 -0.035 0.175 0.035 ;
END V2_5_X3H_HX

VIA V2_5_X3E_HX
  LAYER M2 ;
    RECT -0.055 -0.045 0.335 0.045 ;
  LAYER M3 ;
    RECT -0.05 -0.05 0.33 0.05 ;
  LAYER V2 ;
    RECT -0.035 -0.035 0.035 0.035 ;
    RECT 0.105 -0.035 0.175 0.035 ;
    RECT 0.245 -0.035 0.315 0.035 ;
END V2_5_X3E_HX

VIA V2_5_X3W_HX
  LAYER M2 ;
    RECT -0.335 -0.045 0.055 0.045 ;
  LAYER M3 ;
    RECT -0.33 -0.05 0.05 0.05 ;
  LAYER V2 ;
    RECT -0.035 -0.035 0.035 0.035 ;
    RECT -0.175 -0.035 -0.105 0.035 ;
    RECT -0.315 -0.035 -0.245 0.035 ;
END V2_5_X3W_HX

VIA V2_5_X3V_HX
  LAYER M2 ;
    RECT -0.055 -0.185 0.055 0.185 ;
  LAYER M3 ;
    RECT -0.05 -0.19 0.05 0.19 ;
  LAYER V2 ;
    RECT -0.035 -0.175 0.035 -0.105 ;
    RECT -0.035 -0.035 0.035 0.035 ;
    RECT -0.035 0.105 0.035 0.175 ;
END V2_5_X3V_HX

VIA V2_5_X3N_HX
  LAYER M2 ;
    RECT -0.055 -0.045 0.055 0.325 ;
  LAYER M3 ;
    RECT -0.05 -0.05 0.05 0.33 ;
  LAYER V2 ;
    RECT -0.035 -0.035 0.035 0.035 ;
    RECT -0.035 0.105 0.035 0.175 ;
    RECT -0.035 0.245 0.035 0.315 ;
END V2_5_X3N_HX

VIA V2_5_X3S_HX
  LAYER M2 ;
    RECT -0.055 -0.325 0.055 0.045 ;
  LAYER M3 ;
    RECT -0.05 -0.33 0.05 0.05 ;
  LAYER V2 ;
    RECT -0.035 -0.035 0.035 0.035 ;
    RECT -0.035 -0.175 0.035 -0.105 ;
    RECT -0.035 -0.315 0.035 -0.245 ;
END V2_5_X3S_HX

VIA V2_5_X4H_HX
  LAYER M2 ;
    RECT -0.125 -0.115 0.125 0.115 ;
  LAYER M3 ;
    RECT -0.12 -0.12 0.12 0.12 ;
  LAYER V2 ;
    RECT -0.105 -0.105 -0.035 -0.035 ;
    RECT 0.035 -0.105 0.105 -0.035 ;
    RECT -0.105 0.035 -0.035 0.105 ;
    RECT 0.035 0.035 0.105 0.105 ;
END V2_5_X4H_HX

VIA V2_5_X4E_HX
  LAYER M2 ;
    RECT -0.055 -0.185 0.195 0.045 ;
  LAYER M3 ;
    RECT -0.05 -0.19 0.19 0.05 ;
  LAYER V2 ;
    RECT -0.035 -0.175 0.035 -0.105 ;
    RECT 0.105 -0.175 0.175 -0.105 ;
    RECT -0.035 -0.035 0.035 0.035 ;
    RECT 0.105 -0.035 0.175 0.035 ;
END V2_5_X4E_HX

VIA V2_5_X4W_HX
  LAYER M2 ;
    RECT -0.195 -0.045 0.055 0.185 ;
  LAYER M3 ;
    RECT -0.19 -0.05 0.05 0.19 ;
  LAYER V2 ;
    RECT -0.175 -0.035 -0.105 0.035 ;
    RECT -0.035 -0.035 0.035 0.035 ;
    RECT -0.175 0.105 -0.105 0.175 ;
    RECT -0.035 0.105 0.035 0.175 ;
END V2_5_X4W_HX

VIA V2_5_X4N_HX
  LAYER M2 ;
    RECT -0.055 -0.045 0.195 0.185 ;
  LAYER M3 ;
    RECT -0.05 -0.05 0.19 0.19 ;
  LAYER V2 ;
    RECT -0.035 -0.035 0.035 0.035 ;
    RECT 0.105 -0.035 0.175 0.035 ;
    RECT -0.035 0.105 0.035 0.175 ;
    RECT 0.105 0.105 0.175 0.175 ;
END V2_5_X4N_HX

VIA V2_5_X4S_HX
  LAYER M2 ;
    RECT -0.195 -0.185 0.055 0.045 ;
  LAYER M3 ;
    RECT -0.19 -0.19 0.05 0.05 ;
  LAYER V2 ;
    RECT -0.175 -0.175 -0.105 -0.105 ;
    RECT -0.035 -0.175 0.035 -0.105 ;
    RECT -0.175 -0.035 -0.105 0.035 ;
    RECT -0.035 -0.035 0.035 0.035 ;
END V2_5_X4S_HX

VIA V2_7_X2H_XV
  LAYER M2 ;
    RECT -0.12 -0.05 0.12 0.05 ;
  LAYER M3 ;
    RECT -0.115 -0.055 0.115 0.055 ;
  LAYER V2 ;
    RECT -0.105 -0.035 -0.035 0.035 ;
    RECT 0.035 -0.035 0.105 0.035 ;
END V2_7_X2H_XV

VIA V2_7_X2E_XV
  LAYER M2 ;
    RECT -0.05 -0.05 0.19 0.05 ;
  LAYER M3 ;
    RECT -0.045 -0.055 0.185 0.055 ;
  LAYER V2 ;
    RECT -0.035 -0.035 0.035 0.035 ;
    RECT 0.105 -0.035 0.175 0.035 ;
END V2_7_X2E_XV

VIA V2_7_X2W_XV
  LAYER M2 ;
    RECT -0.19 -0.05 0.05 0.05 ;
  LAYER M3 ;
    RECT -0.185 -0.055 0.045 0.055 ;
  LAYER V2 ;
    RECT -0.035 -0.035 0.035 0.035 ;
    RECT -0.175 -0.035 -0.105 0.035 ;
END V2_7_X2W_XV

VIA V2_7_X2V_XV
  LAYER M2 ;
    RECT -0.05 -0.12 0.05 0.12 ;
  LAYER M3 ;
    RECT -0.045 -0.125 0.045 0.125 ;
  LAYER V2 ;
    RECT -0.035 -0.105 0.035 -0.035 ;
    RECT -0.035 0.035 0.035 0.105 ;
END V2_7_X2V_XV

VIA V2_7_X2N_XV
  LAYER M2 ;
    RECT -0.05 -0.05 0.05 0.19 ;
  LAYER M3 ;
    RECT -0.045 -0.055 0.045 0.195 ;
  LAYER V2 ;
    RECT -0.035 -0.035 0.035 0.035 ;
    RECT -0.035 0.105 0.035 0.175 ;
END V2_7_X2N_XV

VIA V2_7_X2S_XV
  LAYER M2 ;
    RECT -0.05 -0.19 0.05 0.05 ;
  LAYER M3 ;
    RECT -0.045 -0.195 0.045 0.055 ;
  LAYER V2 ;
    RECT -0.035 -0.035 0.035 0.035 ;
    RECT -0.035 -0.175 0.035 -0.105 ;
END V2_7_X2S_XV

VIA V2_7_X3H_XV
  LAYER M2 ;
    RECT -0.19 -0.05 0.19 0.05 ;
  LAYER M3 ;
    RECT -0.185 -0.055 0.185 0.055 ;
  LAYER V2 ;
    RECT -0.175 -0.035 -0.105 0.035 ;
    RECT -0.035 -0.035 0.035 0.035 ;
    RECT 0.105 -0.035 0.175 0.035 ;
END V2_7_X3H_XV

VIA V2_7_X3E_XV
  LAYER M2 ;
    RECT -0.05 -0.05 0.33 0.05 ;
  LAYER M3 ;
    RECT -0.045 -0.055 0.325 0.055 ;
  LAYER V2 ;
    RECT -0.035 -0.035 0.035 0.035 ;
    RECT 0.105 -0.035 0.175 0.035 ;
    RECT 0.245 -0.035 0.315 0.035 ;
END V2_7_X3E_XV

VIA V2_7_X3W_XV
  LAYER M2 ;
    RECT -0.33 -0.05 0.05 0.05 ;
  LAYER M3 ;
    RECT -0.325 -0.055 0.045 0.055 ;
  LAYER V2 ;
    RECT -0.035 -0.035 0.035 0.035 ;
    RECT -0.175 -0.035 -0.105 0.035 ;
    RECT -0.315 -0.035 -0.245 0.035 ;
END V2_7_X3W_XV

VIA V2_7_X3V_XV
  LAYER M2 ;
    RECT -0.05 -0.19 0.05 0.19 ;
  LAYER M3 ;
    RECT -0.045 -0.195 0.045 0.195 ;
  LAYER V2 ;
    RECT -0.035 -0.175 0.035 -0.105 ;
    RECT -0.035 -0.035 0.035 0.035 ;
    RECT -0.035 0.105 0.035 0.175 ;
END V2_7_X3V_XV

VIA V2_7_X3N_XV
  LAYER M2 ;
    RECT -0.05 -0.05 0.05 0.33 ;
  LAYER M3 ;
    RECT -0.045 -0.055 0.045 0.335 ;
  LAYER V2 ;
    RECT -0.035 -0.035 0.035 0.035 ;
    RECT -0.035 0.105 0.035 0.175 ;
    RECT -0.035 0.245 0.035 0.315 ;
END V2_7_X3N_XV

VIA V2_7_X3S_XV
  LAYER M2 ;
    RECT -0.05 -0.33 0.05 0.05 ;
  LAYER M3 ;
    RECT -0.045 -0.335 0.045 0.055 ;
  LAYER V2 ;
    RECT -0.035 -0.035 0.035 0.035 ;
    RECT -0.035 -0.175 0.035 -0.105 ;
    RECT -0.035 -0.315 0.035 -0.245 ;
END V2_7_X3S_XV

VIA V2_7_X4H_XV
  LAYER M2 ;
    RECT -0.12 -0.12 0.12 0.12 ;
  LAYER M3 ;
    RECT -0.115 -0.125 0.115 0.125 ;
  LAYER V2 ;
    RECT -0.105 -0.105 -0.035 -0.035 ;
    RECT 0.035 -0.105 0.105 -0.035 ;
    RECT -0.105 0.035 -0.035 0.105 ;
    RECT 0.035 0.035 0.105 0.105 ;
END V2_7_X4H_XV

VIA V2_7_X4E_XV
  LAYER M2 ;
    RECT -0.05 -0.19 0.19 0.05 ;
  LAYER M3 ;
    RECT -0.045 -0.195 0.185 0.055 ;
  LAYER V2 ;
    RECT -0.035 -0.175 0.035 -0.105 ;
    RECT 0.105 -0.175 0.175 -0.105 ;
    RECT -0.035 -0.035 0.035 0.035 ;
    RECT 0.105 -0.035 0.175 0.035 ;
END V2_7_X4E_XV

VIA V2_7_X4W_XV
  LAYER M2 ;
    RECT -0.19 -0.05 0.05 0.19 ;
  LAYER M3 ;
    RECT -0.185 -0.055 0.045 0.195 ;
  LAYER V2 ;
    RECT -0.175 -0.035 -0.105 0.035 ;
    RECT -0.035 -0.035 0.035 0.035 ;
    RECT -0.175 0.105 -0.105 0.175 ;
    RECT -0.035 0.105 0.035 0.175 ;
END V2_7_X4W_XV

VIA V2_7_X4N_XV
  LAYER M2 ;
    RECT -0.05 -0.05 0.19 0.19 ;
  LAYER M3 ;
    RECT -0.045 -0.055 0.185 0.195 ;
  LAYER V2 ;
    RECT -0.035 -0.035 0.035 0.035 ;
    RECT 0.105 -0.035 0.175 0.035 ;
    RECT -0.035 0.105 0.035 0.175 ;
    RECT 0.105 0.105 0.175 0.175 ;
END V2_7_X4N_XV

VIA V2_7_X4S_XV
  LAYER M2 ;
    RECT -0.19 -0.19 0.05 0.05 ;
  LAYER M3 ;
    RECT -0.185 -0.195 0.045 0.055 ;
  LAYER V2 ;
    RECT -0.175 -0.175 -0.105 -0.105 ;
    RECT -0.035 -0.175 0.035 -0.105 ;
    RECT -0.175 -0.035 -0.105 0.035 ;
    RECT -0.035 -0.035 0.035 0.035 ;
END V2_7_X4S_XV

VIA V2_8_X2H_XX
  LAYER M2 ;
    RECT -0.12 -0.05 0.12 0.05 ;
  LAYER M3 ;
    RECT -0.12 -0.05 0.12 0.05 ;
  LAYER V2 ;
    RECT -0.105 -0.035 -0.035 0.035 ;
    RECT 0.035 -0.035 0.105 0.035 ;
END V2_8_X2H_XX

VIA V2_8_X2E_XX
  LAYER M2 ;
    RECT -0.05 -0.05 0.19 0.05 ;
  LAYER M3 ;
    RECT -0.05 -0.05 0.19 0.05 ;
  LAYER V2 ;
    RECT -0.035 -0.035 0.035 0.035 ;
    RECT 0.105 -0.035 0.175 0.035 ;
END V2_8_X2E_XX

VIA V2_8_X2W_XX
  LAYER M2 ;
    RECT -0.19 -0.05 0.05 0.05 ;
  LAYER M3 ;
    RECT -0.19 -0.05 0.05 0.05 ;
  LAYER V2 ;
    RECT -0.035 -0.035 0.035 0.035 ;
    RECT -0.175 -0.035 -0.105 0.035 ;
END V2_8_X2W_XX

VIA V2_8_X2V_XX
  LAYER M2 ;
    RECT -0.05 -0.12 0.05 0.12 ;
  LAYER M3 ;
    RECT -0.05 -0.12 0.05 0.12 ;
  LAYER V2 ;
    RECT -0.035 -0.105 0.035 -0.035 ;
    RECT -0.035 0.035 0.035 0.105 ;
END V2_8_X2V_XX

VIA V2_8_X2N_XX
  LAYER M2 ;
    RECT -0.05 -0.05 0.05 0.19 ;
  LAYER M3 ;
    RECT -0.05 -0.05 0.05 0.19 ;
  LAYER V2 ;
    RECT -0.035 -0.035 0.035 0.035 ;
    RECT -0.035 0.105 0.035 0.175 ;
END V2_8_X2N_XX

VIA V2_8_X2S_XX
  LAYER M2 ;
    RECT -0.05 -0.19 0.05 0.05 ;
  LAYER M3 ;
    RECT -0.05 -0.19 0.05 0.05 ;
  LAYER V2 ;
    RECT -0.035 -0.035 0.035 0.035 ;
    RECT -0.035 -0.175 0.035 -0.105 ;
END V2_8_X2S_XX

VIA V2_8_X3H_XX
  LAYER M2 ;
    RECT -0.19 -0.05 0.19 0.05 ;
  LAYER M3 ;
    RECT -0.19 -0.05 0.19 0.05 ;
  LAYER V2 ;
    RECT -0.175 -0.035 -0.105 0.035 ;
    RECT -0.035 -0.035 0.035 0.035 ;
    RECT 0.105 -0.035 0.175 0.035 ;
END V2_8_X3H_XX

VIA V2_8_X3E_XX
  LAYER M2 ;
    RECT -0.05 -0.05 0.33 0.05 ;
  LAYER M3 ;
    RECT -0.05 -0.05 0.33 0.05 ;
  LAYER V2 ;
    RECT -0.035 -0.035 0.035 0.035 ;
    RECT 0.105 -0.035 0.175 0.035 ;
    RECT 0.245 -0.035 0.315 0.035 ;
END V2_8_X3E_XX

VIA V2_8_X3W_XX
  LAYER M2 ;
    RECT -0.33 -0.05 0.05 0.05 ;
  LAYER M3 ;
    RECT -0.33 -0.05 0.05 0.05 ;
  LAYER V2 ;
    RECT -0.035 -0.035 0.035 0.035 ;
    RECT -0.175 -0.035 -0.105 0.035 ;
    RECT -0.315 -0.035 -0.245 0.035 ;
END V2_8_X3W_XX

VIA V2_8_X3V_XX
  LAYER M2 ;
    RECT -0.05 -0.19 0.05 0.19 ;
  LAYER M3 ;
    RECT -0.05 -0.19 0.05 0.19 ;
  LAYER V2 ;
    RECT -0.035 -0.175 0.035 -0.105 ;
    RECT -0.035 -0.035 0.035 0.035 ;
    RECT -0.035 0.105 0.035 0.175 ;
END V2_8_X3V_XX

VIA V2_8_X3N_XX
  LAYER M2 ;
    RECT -0.05 -0.05 0.05 0.33 ;
  LAYER M3 ;
    RECT -0.05 -0.05 0.05 0.33 ;
  LAYER V2 ;
    RECT -0.035 -0.035 0.035 0.035 ;
    RECT -0.035 0.105 0.035 0.175 ;
    RECT -0.035 0.245 0.035 0.315 ;
END V2_8_X3N_XX

VIA V2_8_X3S_XX
  LAYER M2 ;
    RECT -0.05 -0.33 0.05 0.05 ;
  LAYER M3 ;
    RECT -0.05 -0.33 0.05 0.05 ;
  LAYER V2 ;
    RECT -0.035 -0.035 0.035 0.035 ;
    RECT -0.035 -0.175 0.035 -0.105 ;
    RECT -0.035 -0.315 0.035 -0.245 ;
END V2_8_X3S_XX

VIA V2_8_X4H_XX
  LAYER M2 ;
    RECT -0.12 -0.12 0.12 0.12 ;
  LAYER M3 ;
    RECT -0.12 -0.12 0.12 0.12 ;
  LAYER V2 ;
    RECT -0.105 -0.105 -0.035 -0.035 ;
    RECT 0.035 -0.105 0.105 -0.035 ;
    RECT -0.105 0.035 -0.035 0.105 ;
    RECT 0.035 0.035 0.105 0.105 ;
END V2_8_X4H_XX

VIA V2_8_X4E_XX
  LAYER M2 ;
    RECT -0.05 -0.19 0.19 0.05 ;
  LAYER M3 ;
    RECT -0.05 -0.19 0.19 0.05 ;
  LAYER V2 ;
    RECT -0.035 -0.175 0.035 -0.105 ;
    RECT 0.105 -0.175 0.175 -0.105 ;
    RECT -0.035 -0.035 0.035 0.035 ;
    RECT 0.105 -0.035 0.175 0.035 ;
END V2_8_X4E_XX

VIA V2_8_X4W_XX
  LAYER M2 ;
    RECT -0.19 -0.05 0.05 0.19 ;
  LAYER M3 ;
    RECT -0.19 -0.05 0.05 0.19 ;
  LAYER V2 ;
    RECT -0.175 -0.035 -0.105 0.035 ;
    RECT -0.035 -0.035 0.035 0.035 ;
    RECT -0.175 0.105 -0.105 0.175 ;
    RECT -0.035 0.105 0.035 0.175 ;
END V2_8_X4W_XX

VIA V2_8_X4N_XX
  LAYER M2 ;
    RECT -0.05 -0.05 0.19 0.19 ;
  LAYER M3 ;
    RECT -0.05 -0.05 0.19 0.19 ;
  LAYER V2 ;
    RECT -0.035 -0.035 0.035 0.035 ;
    RECT 0.105 -0.035 0.175 0.035 ;
    RECT -0.035 0.105 0.035 0.175 ;
    RECT 0.105 0.105 0.175 0.175 ;
END V2_8_X4N_XX

VIA V2_8_X4S_XX
  LAYER M2 ;
    RECT -0.19 -0.19 0.05 0.05 ;
  LAYER M3 ;
    RECT -0.19 -0.19 0.05 0.05 ;
  LAYER V2 ;
    RECT -0.175 -0.175 -0.105 -0.105 ;
    RECT -0.035 -0.175 0.035 -0.105 ;
    RECT -0.175 -0.035 -0.105 0.035 ;
    RECT -0.035 -0.035 0.035 0.035 ;
END V2_8_X4S_XX

VIA V3_0_VH DEFAULT
  LAYER M3 ;
    RECT -0.035 -0.065 0.035 0.065 ;
  LAYER M4 ;
    RECT -0.065 -0.035 0.065 0.035 ;
  LAYER V3 ;
    RECT -0.035 -0.035 0.035 0.035 ;
END V3_0_VH

VIA V3_0_VH_S1 DEFAULT
  LAYER M3 ;
    RECT -0.035 -0.065 0.035 0.215 ;
  LAYER M4 ;
    RECT -0.065 -0.035 0.065 0.035 ;
  LAYER V3 ;
    RECT -0.035 -0.035 0.035 0.035 ;
END V3_0_VH_S1

VIA V3_0_VH_S2 DEFAULT
  LAYER M3 ;
    RECT -0.035 -0.215 0.035 0.065 ;
  LAYER M4 ;
    RECT -0.065 -0.035 0.065 0.035 ;
  LAYER V3 ;
    RECT -0.035 -0.035 0.035 0.035 ;
END V3_0_VH_S2

VIA V3_0_HH DEFAULT
  LAYER M3 ;
    RECT -0.065 -0.035 0.065 0.035 ;
  LAYER M4 ;
    RECT -0.065 -0.035 0.065 0.035 ;
  LAYER V3 ;
    RECT -0.035 -0.035 0.035 0.035 ;
END V3_0_HH

VIA V3_0_VV DEFAULT
  LAYER M3 ;
    RECT -0.035 -0.065 0.035 0.065 ;
  LAYER M4 ;
    RECT -0.035 -0.065 0.035 0.065 ;
  LAYER V3 ;
    RECT -0.035 -0.035 0.035 0.035 ;
END V3_0_VV

VIA V3_0_HV DEFAULT
  LAYER M3 ;
    RECT -0.065 -0.035 0.065 0.035 ;
  LAYER M4 ;
    RECT -0.035 -0.065 0.035 0.065 ;
  LAYER V3 ;
    RECT -0.035 -0.035 0.035 0.035 ;
END V3_0_HV

VIA V3_1_VH DEFAULT
  LAYER M3 ;
    RECT -0.035 -0.065 0.035 0.065 ;
  LAYER M4 ;
    RECT -0.055 -0.045 0.055 0.045 ;
  LAYER V3 ;
    RECT -0.035 -0.035 0.035 0.035 ;
END V3_1_VH

VIA V3_1_VH_S1 DEFAULT
  LAYER M3 ;
    RECT -0.035 -0.065 0.035 0.215 ;
  LAYER M4 ;
    RECT -0.055 -0.045 0.055 0.045 ;
  LAYER V3 ;
    RECT -0.035 -0.035 0.035 0.035 ;
END V3_1_VH_S1

VIA V3_1_VH_S2 DEFAULT
  LAYER M3 ;
    RECT -0.035 -0.215 0.035 0.065 ;
  LAYER M4 ;
    RECT -0.055 -0.045 0.055 0.045 ;
  LAYER V3 ;
    RECT -0.035 -0.035 0.035 0.035 ;
END V3_1_VH_S2

VIA V3_1_HH DEFAULT
  LAYER M3 ;
    RECT -0.065 -0.035 0.065 0.035 ;
  LAYER M4 ;
    RECT -0.055 -0.045 0.055 0.045 ;
  LAYER V3 ;
    RECT -0.035 -0.035 0.035 0.035 ;
END V3_1_HH

VIA V3_1_VV DEFAULT
  LAYER M3 ;
    RECT -0.035 -0.065 0.035 0.065 ;
  LAYER M4 ;
    RECT -0.045 -0.055 0.045 0.055 ;
  LAYER V3 ;
    RECT -0.035 -0.035 0.035 0.035 ;
END V3_1_VV

VIA V3_1_HV DEFAULT
  LAYER M3 ;
    RECT -0.065 -0.035 0.065 0.035 ;
  LAYER M4 ;
    RECT -0.045 -0.055 0.045 0.055 ;
  LAYER V3 ;
    RECT -0.035 -0.035 0.035 0.035 ;
END V3_1_HV

VIA V3_2_VX DEFAULT
  LAYER M3 ;
    RECT -0.035 -0.065 0.035 0.065 ;
  LAYER M4 ;
    RECT -0.05 -0.05 0.05 0.05 ;
  LAYER V3 ;
    RECT -0.035 -0.035 0.035 0.035 ;
END V3_2_VX

VIA V3_2_VX_S1 DEFAULT
  LAYER M3 ;
    RECT -0.035 -0.065 0.035 0.215 ;
  LAYER M4 ;
    RECT -0.05 -0.05 0.05 0.05 ;
  LAYER V3 ;
    RECT -0.035 -0.035 0.035 0.035 ;
END V3_2_VX_S1

VIA V3_2_VX_S2 DEFAULT
  LAYER M3 ;
    RECT -0.035 -0.215 0.035 0.065 ;
  LAYER M4 ;
    RECT -0.05 -0.05 0.05 0.05 ;
  LAYER V3 ;
    RECT -0.035 -0.035 0.035 0.035 ;
END V3_2_VX_S2

VIA V3_2_HX DEFAULT
  LAYER M3 ;
    RECT -0.065 -0.035 0.065 0.035 ;
  LAYER M4 ;
    RECT -0.05 -0.05 0.05 0.05 ;
  LAYER V3 ;
    RECT -0.035 -0.035 0.035 0.035 ;
END V3_2_HX

VIA V3_3_VH DEFAULT
  LAYER M3 ;
    RECT -0.045 -0.055 0.045 0.055 ;
  LAYER M4 ;
    RECT -0.065 -0.035 0.065 0.035 ;
  LAYER V3 ;
    RECT -0.035 -0.035 0.035 0.035 ;
END V3_3_VH

VIA V3_3_VH_S1 DEFAULT
  LAYER M3 ;
    RECT -0.045 -0.055 0.045 0.163 ;
  LAYER M4 ;
    RECT -0.065 -0.035 0.065 0.035 ;
  LAYER V3 ;
    RECT -0.035 -0.035 0.035 0.035 ;
END V3_3_VH_S1

VIA V3_3_VH_S2 DEFAULT
  LAYER M3 ;
    RECT -0.045 -0.163 0.045 0.055 ;
  LAYER M4 ;
    RECT -0.065 -0.035 0.065 0.035 ;
  LAYER V3 ;
    RECT -0.035 -0.035 0.035 0.035 ;
END V3_3_VH_S2

VIA V3_3_HH DEFAULT
  LAYER M3 ;
    RECT -0.055 -0.045 0.055 0.045 ;
  LAYER M4 ;
    RECT -0.065 -0.035 0.065 0.035 ;
  LAYER V3 ;
    RECT -0.035 -0.035 0.035 0.035 ;
END V3_3_HH

VIA V3_3_VV DEFAULT
  LAYER M3 ;
    RECT -0.045 -0.055 0.045 0.055 ;
  LAYER M4 ;
    RECT -0.035 -0.065 0.035 0.065 ;
  LAYER V3 ;
    RECT -0.035 -0.035 0.035 0.035 ;
END V3_3_VV

VIA V3_3_HV DEFAULT
  LAYER M3 ;
    RECT -0.055 -0.045 0.055 0.045 ;
  LAYER M4 ;
    RECT -0.035 -0.065 0.035 0.065 ;
  LAYER V3 ;
    RECT -0.035 -0.035 0.035 0.035 ;
END V3_3_HV

VIA V3_4_VH DEFAULT
  LAYER M3 ;
    RECT -0.045 -0.055 0.045 0.055 ;
  LAYER M4 ;
    RECT -0.055 -0.045 0.055 0.045 ;
  LAYER V3 ;
    RECT -0.035 -0.035 0.035 0.035 ;
END V3_4_VH

VIA V3_4_VH_S1 DEFAULT
  LAYER M3 ;
    RECT -0.045 -0.055 0.045 0.163 ;
  LAYER M4 ;
    RECT -0.055 -0.045 0.055 0.045 ;
  LAYER V3 ;
    RECT -0.035 -0.035 0.035 0.035 ;
END V3_4_VH_S1

VIA V3_4_VH_S2 DEFAULT
  LAYER M3 ;
    RECT -0.045 -0.163 0.045 0.055 ;
  LAYER M4 ;
    RECT -0.055 -0.045 0.055 0.045 ;
  LAYER V3 ;
    RECT -0.035 -0.035 0.035 0.035 ;
END V3_4_VH_S2

VIA V3_4_HH DEFAULT
  LAYER M3 ;
    RECT -0.055 -0.045 0.055 0.045 ;
  LAYER M4 ;
    RECT -0.055 -0.045 0.055 0.045 ;
  LAYER V3 ;
    RECT -0.035 -0.035 0.035 0.035 ;
END V3_4_HH

VIA V3_4_VV DEFAULT
  LAYER M3 ;
    RECT -0.045 -0.055 0.045 0.055 ;
  LAYER M4 ;
    RECT -0.045 -0.055 0.045 0.055 ;
  LAYER V3 ;
    RECT -0.035 -0.035 0.035 0.035 ;
END V3_4_VV

VIA V3_4_HV DEFAULT
  LAYER M3 ;
    RECT -0.055 -0.045 0.055 0.045 ;
  LAYER M4 ;
    RECT -0.045 -0.055 0.045 0.055 ;
  LAYER V3 ;
    RECT -0.035 -0.035 0.035 0.035 ;
END V3_4_HV

VIA V3_5_VX DEFAULT
  LAYER M3 ;
    RECT -0.045 -0.055 0.045 0.055 ;
  LAYER M4 ;
    RECT -0.05 -0.05 0.05 0.05 ;
  LAYER V3 ;
    RECT -0.035 -0.035 0.035 0.035 ;
END V3_5_VX

VIA V3_5_VX_S1 DEFAULT
  LAYER M3 ;
    RECT -0.045 -0.055 0.045 0.163 ;
  LAYER M4 ;
    RECT -0.05 -0.05 0.05 0.05 ;
  LAYER V3 ;
    RECT -0.035 -0.035 0.035 0.035 ;
END V3_5_VX_S1

VIA V3_5_VX_S2 DEFAULT
  LAYER M3 ;
    RECT -0.045 -0.163 0.045 0.055 ;
  LAYER M4 ;
    RECT -0.05 -0.05 0.05 0.05 ;
  LAYER V3 ;
    RECT -0.035 -0.035 0.035 0.035 ;
END V3_5_VX_S2

VIA V3_5_HX DEFAULT
  LAYER M3 ;
    RECT -0.055 -0.045 0.055 0.045 ;
  LAYER M4 ;
    RECT -0.05 -0.05 0.05 0.05 ;
  LAYER V3 ;
    RECT -0.035 -0.035 0.035 0.035 ;
END V3_5_HX

VIA V3_6_XH DEFAULT
  LAYER M3 ;
    RECT -0.05 -0.05 0.05 0.05 ;
  LAYER M4 ;
    RECT -0.065 -0.035 0.065 0.035 ;
  LAYER V3 ;
    RECT -0.035 -0.035 0.035 0.035 ;
END V3_6_XH

VIA V3_6_XH_S1 DEFAULT
  LAYER M3 ;
    RECT -0.05 -0.05 0.05 0.146 ;
  LAYER M4 ;
    RECT -0.065 -0.035 0.065 0.035 ;
  LAYER V3 ;
    RECT -0.035 -0.035 0.035 0.035 ;
END V3_6_XH_S1

VIA V3_6_XH_S2 DEFAULT
  LAYER M3 ;
    RECT -0.05 -0.146 0.05 0.05 ;
  LAYER M4 ;
    RECT -0.065 -0.035 0.065 0.035 ;
  LAYER V3 ;
    RECT -0.035 -0.035 0.035 0.035 ;
END V3_6_XH_S2

VIA V3_6_XV DEFAULT
  LAYER M3 ;
    RECT -0.05 -0.05 0.05 0.05 ;
  LAYER M4 ;
    RECT -0.035 -0.065 0.035 0.065 ;
  LAYER V3 ;
    RECT -0.035 -0.035 0.035 0.035 ;
END V3_6_XV

VIA V3_7_XH DEFAULT
  LAYER M3 ;
    RECT -0.05 -0.05 0.05 0.05 ;
  LAYER M4 ;
    RECT -0.055 -0.045 0.055 0.045 ;
  LAYER V3 ;
    RECT -0.035 -0.035 0.035 0.035 ;
END V3_7_XH

VIA V3_7_XH_S1 DEFAULT
  LAYER M3 ;
    RECT -0.05 -0.05 0.05 0.146 ;
  LAYER M4 ;
    RECT -0.055 -0.045 0.055 0.045 ;
  LAYER V3 ;
    RECT -0.035 -0.035 0.035 0.035 ;
END V3_7_XH_S1

VIA V3_7_XH_S2 DEFAULT
  LAYER M3 ;
    RECT -0.05 -0.146 0.05 0.05 ;
  LAYER M4 ;
    RECT -0.055 -0.045 0.055 0.045 ;
  LAYER V3 ;
    RECT -0.035 -0.035 0.035 0.035 ;
END V3_7_XH_S2

VIA V3_7_XV DEFAULT
  LAYER M3 ;
    RECT -0.05 -0.05 0.05 0.05 ;
  LAYER M4 ;
    RECT -0.045 -0.055 0.045 0.055 ;
  LAYER V3 ;
    RECT -0.035 -0.035 0.035 0.035 ;
END V3_7_XV

VIA V3_8_XX DEFAULT
  LAYER M3 ;
    RECT -0.05 -0.05 0.05 0.05 ;
  LAYER M4 ;
    RECT -0.05 -0.05 0.05 0.05 ;
  LAYER V3 ;
    RECT -0.035 -0.035 0.035 0.035 ;
END V3_8_XX

VIA V3_8_XX_S1 DEFAULT
  LAYER M3 ;
    RECT -0.05 -0.05 0.05 0.146 ;
  LAYER M4 ;
    RECT -0.05 -0.05 0.05 0.05 ;
  LAYER V3 ;
    RECT -0.035 -0.035 0.035 0.035 ;
END V3_8_XX_S1

VIA V3_8_XX_S2 DEFAULT
  LAYER M3 ;
    RECT -0.05 -0.146 0.05 0.05 ;
  LAYER M4 ;
    RECT -0.05 -0.05 0.05 0.05 ;
  LAYER V3 ;
    RECT -0.035 -0.035 0.035 0.035 ;
END V3_8_XX_S2

VIA V3_4_X2H_VH DEFAULT
  LAYER M3 ;
    RECT -0.115 -0.055 0.115 0.055 ;
  LAYER M4 ;
    RECT -0.125 -0.045 0.125 0.045 ;
  LAYER V3 ;
    RECT -0.105 -0.035 -0.035 0.035 ;
    RECT 0.035 -0.035 0.105 0.035 ;
END V3_4_X2H_VH

VIA V3_4_X2E_VH DEFAULT
  LAYER M3 ;
    RECT -0.045 -0.055 0.185 0.055 ;
  LAYER M4 ;
    RECT -0.055 -0.045 0.195 0.045 ;
  LAYER V3 ;
    RECT -0.035 -0.035 0.035 0.035 ;
    RECT 0.105 -0.035 0.175 0.035 ;
END V3_4_X2E_VH

VIA V3_4_X2W_VH DEFAULT
  LAYER M3 ;
    RECT -0.185 -0.055 0.045 0.055 ;
  LAYER M4 ;
    RECT -0.195 -0.045 0.055 0.045 ;
  LAYER V3 ;
    RECT -0.035 -0.035 0.035 0.035 ;
    RECT -0.175 -0.035 -0.105 0.035 ;
END V3_4_X2W_VH

VIA V3_4_X2V_VH DEFAULT
  LAYER M3 ;
    RECT -0.045 -0.125 0.045 0.125 ;
  LAYER M4 ;
    RECT -0.055 -0.115 0.055 0.115 ;
  LAYER V3 ;
    RECT -0.035 -0.105 0.035 -0.035 ;
    RECT -0.035 0.035 0.035 0.105 ;
END V3_4_X2V_VH

VIA V3_4_X2N_VH DEFAULT
  LAYER M3 ;
    RECT -0.045 -0.055 0.045 0.195 ;
  LAYER M4 ;
    RECT -0.055 -0.045 0.055 0.185 ;
  LAYER V3 ;
    RECT -0.035 -0.035 0.035 0.035 ;
    RECT -0.035 0.105 0.035 0.175 ;
END V3_4_X2N_VH

VIA V3_4_X2S_VH DEFAULT
  LAYER M3 ;
    RECT -0.045 -0.195 0.045 0.055 ;
  LAYER M4 ;
    RECT -0.055 -0.185 0.055 0.045 ;
  LAYER V3 ;
    RECT -0.035 -0.035 0.035 0.035 ;
    RECT -0.035 -0.175 0.035 -0.105 ;
END V3_4_X2S_VH

VIA V3_4_X3H_VH DEFAULT
  LAYER M3 ;
    RECT -0.185 -0.055 0.185 0.055 ;
  LAYER M4 ;
    RECT -0.195 -0.045 0.195 0.045 ;
  LAYER V3 ;
    RECT -0.175 -0.035 -0.105 0.035 ;
    RECT -0.035 -0.035 0.035 0.035 ;
    RECT 0.105 -0.035 0.175 0.035 ;
END V3_4_X3H_VH

VIA V3_4_X3E_VH DEFAULT
  LAYER M3 ;
    RECT -0.045 -0.055 0.325 0.055 ;
  LAYER M4 ;
    RECT -0.055 -0.045 0.335 0.045 ;
  LAYER V3 ;
    RECT -0.035 -0.035 0.035 0.035 ;
    RECT 0.105 -0.035 0.175 0.035 ;
    RECT 0.245 -0.035 0.315 0.035 ;
END V3_4_X3E_VH

VIA V3_4_X3W_VH DEFAULT
  LAYER M3 ;
    RECT -0.325 -0.055 0.045 0.055 ;
  LAYER M4 ;
    RECT -0.335 -0.045 0.055 0.045 ;
  LAYER V3 ;
    RECT -0.035 -0.035 0.035 0.035 ;
    RECT -0.175 -0.035 -0.105 0.035 ;
    RECT -0.315 -0.035 -0.245 0.035 ;
END V3_4_X3W_VH

VIA V3_4_X3V_VH DEFAULT
  LAYER M3 ;
    RECT -0.045 -0.195 0.045 0.195 ;
  LAYER M4 ;
    RECT -0.055 -0.185 0.055 0.185 ;
  LAYER V3 ;
    RECT -0.035 -0.175 0.035 -0.105 ;
    RECT -0.035 -0.035 0.035 0.035 ;
    RECT -0.035 0.105 0.035 0.175 ;
END V3_4_X3V_VH

VIA V3_4_X3N_VH DEFAULT
  LAYER M3 ;
    RECT -0.045 -0.055 0.045 0.335 ;
  LAYER M4 ;
    RECT -0.055 -0.045 0.055 0.325 ;
  LAYER V3 ;
    RECT -0.035 -0.035 0.035 0.035 ;
    RECT -0.035 0.105 0.035 0.175 ;
    RECT -0.035 0.245 0.035 0.315 ;
END V3_4_X3N_VH

VIA V3_4_X3S_VH DEFAULT
  LAYER M3 ;
    RECT -0.045 -0.335 0.045 0.055 ;
  LAYER M4 ;
    RECT -0.055 -0.325 0.055 0.045 ;
  LAYER V3 ;
    RECT -0.035 -0.035 0.035 0.035 ;
    RECT -0.035 -0.175 0.035 -0.105 ;
    RECT -0.035 -0.315 0.035 -0.245 ;
END V3_4_X3S_VH

VIA V3_4_X4H_VH DEFAULT
  LAYER M3 ;
    RECT -0.115 -0.125 0.115 0.125 ;
  LAYER M4 ;
    RECT -0.125 -0.115 0.125 0.115 ;
  LAYER V3 ;
    RECT -0.105 -0.105 -0.035 -0.035 ;
    RECT 0.035 -0.105 0.105 -0.035 ;
    RECT -0.105 0.035 -0.035 0.105 ;
    RECT 0.035 0.035 0.105 0.105 ;
END V3_4_X4H_VH

VIA V3_4_X4E_VH DEFAULT
  LAYER M3 ;
    RECT -0.045 -0.195 0.185 0.055 ;
  LAYER M4 ;
    RECT -0.055 -0.185 0.195 0.045 ;
  LAYER V3 ;
    RECT -0.035 -0.175 0.035 -0.105 ;
    RECT 0.105 -0.175 0.175 -0.105 ;
    RECT -0.035 -0.035 0.035 0.035 ;
    RECT 0.105 -0.035 0.175 0.035 ;
END V3_4_X4E_VH

VIA V3_4_X4W_VH DEFAULT
  LAYER M3 ;
    RECT -0.185 -0.055 0.045 0.195 ;
  LAYER M4 ;
    RECT -0.195 -0.045 0.055 0.185 ;
  LAYER V3 ;
    RECT -0.175 -0.035 -0.105 0.035 ;
    RECT -0.035 -0.035 0.035 0.035 ;
    RECT -0.175 0.105 -0.105 0.175 ;
    RECT -0.035 0.105 0.035 0.175 ;
END V3_4_X4W_VH

VIA V3_4_X4N_VH DEFAULT
  LAYER M3 ;
    RECT -0.045 -0.055 0.185 0.195 ;
  LAYER M4 ;
    RECT -0.055 -0.045 0.195 0.185 ;
  LAYER V3 ;
    RECT -0.035 -0.035 0.035 0.035 ;
    RECT 0.105 -0.035 0.175 0.035 ;
    RECT -0.035 0.105 0.035 0.175 ;
    RECT 0.105 0.105 0.175 0.175 ;
END V3_4_X4N_VH

VIA V3_4_X4S_VH DEFAULT
  LAYER M3 ;
    RECT -0.185 -0.195 0.045 0.055 ;
  LAYER M4 ;
    RECT -0.195 -0.185 0.055 0.045 ;
  LAYER V3 ;
    RECT -0.175 -0.175 -0.105 -0.105 ;
    RECT -0.035 -0.175 0.035 -0.105 ;
    RECT -0.175 -0.035 -0.105 0.035 ;
    RECT -0.035 -0.035 0.035 0.035 ;
END V3_4_X4S_VH

VIA V3_5_X2H_VX DEFAULT
  LAYER M3 ;
    RECT -0.115 -0.055 0.115 0.055 ;
  LAYER M4 ;
    RECT -0.12 -0.05 0.12 0.05 ;
  LAYER V3 ;
    RECT -0.105 -0.035 -0.035 0.035 ;
    RECT 0.035 -0.035 0.105 0.035 ;
END V3_5_X2H_VX

VIA V3_5_X2E_VX DEFAULT
  LAYER M3 ;
    RECT -0.045 -0.055 0.185 0.055 ;
  LAYER M4 ;
    RECT -0.05 -0.05 0.19 0.05 ;
  LAYER V3 ;
    RECT -0.035 -0.035 0.035 0.035 ;
    RECT 0.105 -0.035 0.175 0.035 ;
END V3_5_X2E_VX

VIA V3_5_X2W_VX DEFAULT
  LAYER M3 ;
    RECT -0.185 -0.055 0.045 0.055 ;
  LAYER M4 ;
    RECT -0.19 -0.05 0.05 0.05 ;
  LAYER V3 ;
    RECT -0.035 -0.035 0.035 0.035 ;
    RECT -0.175 -0.035 -0.105 0.035 ;
END V3_5_X2W_VX

VIA V3_5_X2V_VX DEFAULT
  LAYER M3 ;
    RECT -0.045 -0.125 0.045 0.125 ;
  LAYER M4 ;
    RECT -0.05 -0.12 0.05 0.12 ;
  LAYER V3 ;
    RECT -0.035 -0.105 0.035 -0.035 ;
    RECT -0.035 0.035 0.035 0.105 ;
END V3_5_X2V_VX

VIA V3_5_X2N_VX
  LAYER M3 ;
    RECT -0.045 -0.055 0.045 0.195 ;
  LAYER M4 ;
    RECT -0.05 -0.05 0.05 0.19 ;
  LAYER V3 ;
    RECT -0.035 -0.035 0.035 0.035 ;
    RECT -0.035 0.105 0.035 0.175 ;
END V3_5_X2N_VX

VIA V3_5_X2S_VX
  LAYER M3 ;
    RECT -0.045 -0.195 0.045 0.055 ;
  LAYER M4 ;
    RECT -0.05 -0.19 0.05 0.05 ;
  LAYER V3 ;
    RECT -0.035 -0.035 0.035 0.035 ;
    RECT -0.035 -0.175 0.035 -0.105 ;
END V3_5_X2S_VX

VIA V3_5_X3H_VX
  LAYER M3 ;
    RECT -0.185 -0.055 0.185 0.055 ;
  LAYER M4 ;
    RECT -0.19 -0.05 0.19 0.05 ;
  LAYER V3 ;
    RECT -0.175 -0.035 -0.105 0.035 ;
    RECT -0.035 -0.035 0.035 0.035 ;
    RECT 0.105 -0.035 0.175 0.035 ;
END V3_5_X3H_VX

VIA V3_5_X3E_VX
  LAYER M3 ;
    RECT -0.045 -0.055 0.325 0.055 ;
  LAYER M4 ;
    RECT -0.05 -0.05 0.33 0.05 ;
  LAYER V3 ;
    RECT -0.035 -0.035 0.035 0.035 ;
    RECT 0.105 -0.035 0.175 0.035 ;
    RECT 0.245 -0.035 0.315 0.035 ;
END V3_5_X3E_VX

VIA V3_5_X3W_VX
  LAYER M3 ;
    RECT -0.325 -0.055 0.045 0.055 ;
  LAYER M4 ;
    RECT -0.33 -0.05 0.05 0.05 ;
  LAYER V3 ;
    RECT -0.035 -0.035 0.035 0.035 ;
    RECT -0.175 -0.035 -0.105 0.035 ;
    RECT -0.315 -0.035 -0.245 0.035 ;
END V3_5_X3W_VX

VIA V3_5_X3V_VX
  LAYER M3 ;
    RECT -0.045 -0.195 0.045 0.195 ;
  LAYER M4 ;
    RECT -0.05 -0.19 0.05 0.19 ;
  LAYER V3 ;
    RECT -0.035 -0.175 0.035 -0.105 ;
    RECT -0.035 -0.035 0.035 0.035 ;
    RECT -0.035 0.105 0.035 0.175 ;
END V3_5_X3V_VX

VIA V3_5_X3N_VX
  LAYER M3 ;
    RECT -0.045 -0.055 0.045 0.335 ;
  LAYER M4 ;
    RECT -0.05 -0.05 0.05 0.33 ;
  LAYER V3 ;
    RECT -0.035 -0.035 0.035 0.035 ;
    RECT -0.035 0.105 0.035 0.175 ;
    RECT -0.035 0.245 0.035 0.315 ;
END V3_5_X3N_VX

VIA V3_5_X3S_VX
  LAYER M3 ;
    RECT -0.045 -0.335 0.045 0.055 ;
  LAYER M4 ;
    RECT -0.05 -0.33 0.05 0.05 ;
  LAYER V3 ;
    RECT -0.035 -0.035 0.035 0.035 ;
    RECT -0.035 -0.175 0.035 -0.105 ;
    RECT -0.035 -0.315 0.035 -0.245 ;
END V3_5_X3S_VX

VIA V3_5_X4H_VX
  LAYER M3 ;
    RECT -0.115 -0.125 0.115 0.125 ;
  LAYER M4 ;
    RECT -0.12 -0.12 0.12 0.12 ;
  LAYER V3 ;
    RECT -0.105 -0.105 -0.035 -0.035 ;
    RECT 0.035 -0.105 0.105 -0.035 ;
    RECT -0.105 0.035 -0.035 0.105 ;
    RECT 0.035 0.035 0.105 0.105 ;
END V3_5_X4H_VX

VIA V3_5_X4E_VX
  LAYER M3 ;
    RECT -0.045 -0.195 0.185 0.055 ;
  LAYER M4 ;
    RECT -0.05 -0.19 0.19 0.05 ;
  LAYER V3 ;
    RECT -0.035 -0.175 0.035 -0.105 ;
    RECT 0.105 -0.175 0.175 -0.105 ;
    RECT -0.035 -0.035 0.035 0.035 ;
    RECT 0.105 -0.035 0.175 0.035 ;
END V3_5_X4E_VX

VIA V3_5_X4W_VX
  LAYER M3 ;
    RECT -0.185 -0.055 0.045 0.195 ;
  LAYER M4 ;
    RECT -0.19 -0.05 0.05 0.19 ;
  LAYER V3 ;
    RECT -0.175 -0.035 -0.105 0.035 ;
    RECT -0.035 -0.035 0.035 0.035 ;
    RECT -0.175 0.105 -0.105 0.175 ;
    RECT -0.035 0.105 0.035 0.175 ;
END V3_5_X4W_VX

VIA V3_5_X4N_VX
  LAYER M3 ;
    RECT -0.045 -0.055 0.185 0.195 ;
  LAYER M4 ;
    RECT -0.05 -0.05 0.19 0.19 ;
  LAYER V3 ;
    RECT -0.035 -0.035 0.035 0.035 ;
    RECT 0.105 -0.035 0.175 0.035 ;
    RECT -0.035 0.105 0.035 0.175 ;
    RECT 0.105 0.105 0.175 0.175 ;
END V3_5_X4N_VX

VIA V3_5_X4S_VX
  LAYER M3 ;
    RECT -0.185 -0.195 0.045 0.055 ;
  LAYER M4 ;
    RECT -0.19 -0.19 0.05 0.05 ;
  LAYER V3 ;
    RECT -0.175 -0.175 -0.105 -0.105 ;
    RECT -0.035 -0.175 0.035 -0.105 ;
    RECT -0.175 -0.035 -0.105 0.035 ;
    RECT -0.035 -0.035 0.035 0.035 ;
END V3_5_X4S_VX

VIA V3_7_X2H_XH
  LAYER M3 ;
    RECT -0.12 -0.05 0.12 0.05 ;
  LAYER M4 ;
    RECT -0.125 -0.045 0.125 0.045 ;
  LAYER V3 ;
    RECT -0.105 -0.035 -0.035 0.035 ;
    RECT 0.035 -0.035 0.105 0.035 ;
END V3_7_X2H_XH

VIA V3_7_X2E_XH
  LAYER M3 ;
    RECT -0.05 -0.05 0.19 0.05 ;
  LAYER M4 ;
    RECT -0.055 -0.045 0.195 0.045 ;
  LAYER V3 ;
    RECT -0.035 -0.035 0.035 0.035 ;
    RECT 0.105 -0.035 0.175 0.035 ;
END V3_7_X2E_XH

VIA V3_7_X2W_XH
  LAYER M3 ;
    RECT -0.19 -0.05 0.05 0.05 ;
  LAYER M4 ;
    RECT -0.195 -0.045 0.055 0.045 ;
  LAYER V3 ;
    RECT -0.035 -0.035 0.035 0.035 ;
    RECT -0.175 -0.035 -0.105 0.035 ;
END V3_7_X2W_XH

VIA V3_7_X2V_XH
  LAYER M3 ;
    RECT -0.05 -0.12 0.05 0.12 ;
  LAYER M4 ;
    RECT -0.055 -0.115 0.055 0.115 ;
  LAYER V3 ;
    RECT -0.035 -0.105 0.035 -0.035 ;
    RECT -0.035 0.035 0.035 0.105 ;
END V3_7_X2V_XH

VIA V3_7_X2N_XH
  LAYER M3 ;
    RECT -0.05 -0.05 0.05 0.19 ;
  LAYER M4 ;
    RECT -0.055 -0.045 0.055 0.185 ;
  LAYER V3 ;
    RECT -0.035 -0.035 0.035 0.035 ;
    RECT -0.035 0.105 0.035 0.175 ;
END V3_7_X2N_XH

VIA V3_7_X2S_XH
  LAYER M3 ;
    RECT -0.05 -0.19 0.05 0.05 ;
  LAYER M4 ;
    RECT -0.055 -0.185 0.055 0.045 ;
  LAYER V3 ;
    RECT -0.035 -0.035 0.035 0.035 ;
    RECT -0.035 -0.175 0.035 -0.105 ;
END V3_7_X2S_XH

VIA V3_7_X3H_XH
  LAYER M3 ;
    RECT -0.19 -0.05 0.19 0.05 ;
  LAYER M4 ;
    RECT -0.195 -0.045 0.195 0.045 ;
  LAYER V3 ;
    RECT -0.175 -0.035 -0.105 0.035 ;
    RECT -0.035 -0.035 0.035 0.035 ;
    RECT 0.105 -0.035 0.175 0.035 ;
END V3_7_X3H_XH

VIA V3_7_X3E_XH
  LAYER M3 ;
    RECT -0.05 -0.05 0.33 0.05 ;
  LAYER M4 ;
    RECT -0.055 -0.045 0.335 0.045 ;
  LAYER V3 ;
    RECT -0.035 -0.035 0.035 0.035 ;
    RECT 0.105 -0.035 0.175 0.035 ;
    RECT 0.245 -0.035 0.315 0.035 ;
END V3_7_X3E_XH

VIA V3_7_X3W_XH
  LAYER M3 ;
    RECT -0.33 -0.05 0.05 0.05 ;
  LAYER M4 ;
    RECT -0.335 -0.045 0.055 0.045 ;
  LAYER V3 ;
    RECT -0.035 -0.035 0.035 0.035 ;
    RECT -0.175 -0.035 -0.105 0.035 ;
    RECT -0.315 -0.035 -0.245 0.035 ;
END V3_7_X3W_XH

VIA V3_7_X3V_XH
  LAYER M3 ;
    RECT -0.05 -0.19 0.05 0.19 ;
  LAYER M4 ;
    RECT -0.055 -0.185 0.055 0.185 ;
  LAYER V3 ;
    RECT -0.035 -0.175 0.035 -0.105 ;
    RECT -0.035 -0.035 0.035 0.035 ;
    RECT -0.035 0.105 0.035 0.175 ;
END V3_7_X3V_XH

VIA V3_7_X3N_XH
  LAYER M3 ;
    RECT -0.05 -0.05 0.05 0.33 ;
  LAYER M4 ;
    RECT -0.055 -0.045 0.055 0.325 ;
  LAYER V3 ;
    RECT -0.035 -0.035 0.035 0.035 ;
    RECT -0.035 0.105 0.035 0.175 ;
    RECT -0.035 0.245 0.035 0.315 ;
END V3_7_X3N_XH

VIA V3_7_X3S_XH
  LAYER M3 ;
    RECT -0.05 -0.33 0.05 0.05 ;
  LAYER M4 ;
    RECT -0.055 -0.325 0.055 0.045 ;
  LAYER V3 ;
    RECT -0.035 -0.035 0.035 0.035 ;
    RECT -0.035 -0.175 0.035 -0.105 ;
    RECT -0.035 -0.315 0.035 -0.245 ;
END V3_7_X3S_XH

VIA V3_7_X4H_XH
  LAYER M3 ;
    RECT -0.12 -0.12 0.12 0.12 ;
  LAYER M4 ;
    RECT -0.125 -0.115 0.125 0.115 ;
  LAYER V3 ;
    RECT -0.105 -0.105 -0.035 -0.035 ;
    RECT 0.035 -0.105 0.105 -0.035 ;
    RECT -0.105 0.035 -0.035 0.105 ;
    RECT 0.035 0.035 0.105 0.105 ;
END V3_7_X4H_XH

VIA V3_7_X4E_XH
  LAYER M3 ;
    RECT -0.05 -0.19 0.19 0.05 ;
  LAYER M4 ;
    RECT -0.055 -0.185 0.195 0.045 ;
  LAYER V3 ;
    RECT -0.035 -0.175 0.035 -0.105 ;
    RECT 0.105 -0.175 0.175 -0.105 ;
    RECT -0.035 -0.035 0.035 0.035 ;
    RECT 0.105 -0.035 0.175 0.035 ;
END V3_7_X4E_XH

VIA V3_7_X4W_XH
  LAYER M3 ;
    RECT -0.19 -0.05 0.05 0.19 ;
  LAYER M4 ;
    RECT -0.195 -0.045 0.055 0.185 ;
  LAYER V3 ;
    RECT -0.175 -0.035 -0.105 0.035 ;
    RECT -0.035 -0.035 0.035 0.035 ;
    RECT -0.175 0.105 -0.105 0.175 ;
    RECT -0.035 0.105 0.035 0.175 ;
END V3_7_X4W_XH

VIA V3_7_X4N_XH
  LAYER M3 ;
    RECT -0.05 -0.05 0.19 0.19 ;
  LAYER M4 ;
    RECT -0.055 -0.045 0.195 0.185 ;
  LAYER V3 ;
    RECT -0.035 -0.035 0.035 0.035 ;
    RECT 0.105 -0.035 0.175 0.035 ;
    RECT -0.035 0.105 0.035 0.175 ;
    RECT 0.105 0.105 0.175 0.175 ;
END V3_7_X4N_XH

VIA V3_7_X4S_XH
  LAYER M3 ;
    RECT -0.19 -0.19 0.05 0.05 ;
  LAYER M4 ;
    RECT -0.195 -0.185 0.055 0.045 ;
  LAYER V3 ;
    RECT -0.175 -0.175 -0.105 -0.105 ;
    RECT -0.035 -0.175 0.035 -0.105 ;
    RECT -0.175 -0.035 -0.105 0.035 ;
    RECT -0.035 -0.035 0.035 0.035 ;
END V3_7_X4S_XH

VIA V3_8_X2H_XX
  LAYER M3 ;
    RECT -0.12 -0.05 0.12 0.05 ;
  LAYER M4 ;
    RECT -0.12 -0.05 0.12 0.05 ;
  LAYER V3 ;
    RECT -0.105 -0.035 -0.035 0.035 ;
    RECT 0.035 -0.035 0.105 0.035 ;
END V3_8_X2H_XX

VIA V3_8_X2E_XX
  LAYER M3 ;
    RECT -0.05 -0.05 0.19 0.05 ;
  LAYER M4 ;
    RECT -0.05 -0.05 0.19 0.05 ;
  LAYER V3 ;
    RECT -0.035 -0.035 0.035 0.035 ;
    RECT 0.105 -0.035 0.175 0.035 ;
END V3_8_X2E_XX

VIA V3_8_X2W_XX
  LAYER M3 ;
    RECT -0.19 -0.05 0.05 0.05 ;
  LAYER M4 ;
    RECT -0.19 -0.05 0.05 0.05 ;
  LAYER V3 ;
    RECT -0.035 -0.035 0.035 0.035 ;
    RECT -0.175 -0.035 -0.105 0.035 ;
END V3_8_X2W_XX

VIA V3_8_X2V_XX
  LAYER M3 ;
    RECT -0.05 -0.12 0.05 0.12 ;
  LAYER M4 ;
    RECT -0.05 -0.12 0.05 0.12 ;
  LAYER V3 ;
    RECT -0.035 -0.105 0.035 -0.035 ;
    RECT -0.035 0.035 0.035 0.105 ;
END V3_8_X2V_XX

VIA V3_8_X2N_XX
  LAYER M3 ;
    RECT -0.05 -0.05 0.05 0.19 ;
  LAYER M4 ;
    RECT -0.05 -0.05 0.05 0.19 ;
  LAYER V3 ;
    RECT -0.035 -0.035 0.035 0.035 ;
    RECT -0.035 0.105 0.035 0.175 ;
END V3_8_X2N_XX

VIA V3_8_X2S_XX
  LAYER M3 ;
    RECT -0.05 -0.19 0.05 0.05 ;
  LAYER M4 ;
    RECT -0.05 -0.19 0.05 0.05 ;
  LAYER V3 ;
    RECT -0.035 -0.035 0.035 0.035 ;
    RECT -0.035 -0.175 0.035 -0.105 ;
END V3_8_X2S_XX

VIA V3_8_X3H_XX
  LAYER M3 ;
    RECT -0.19 -0.05 0.19 0.05 ;
  LAYER M4 ;
    RECT -0.19 -0.05 0.19 0.05 ;
  LAYER V3 ;
    RECT -0.175 -0.035 -0.105 0.035 ;
    RECT -0.035 -0.035 0.035 0.035 ;
    RECT 0.105 -0.035 0.175 0.035 ;
END V3_8_X3H_XX

VIA V3_8_X3E_XX
  LAYER M3 ;
    RECT -0.05 -0.05 0.33 0.05 ;
  LAYER M4 ;
    RECT -0.05 -0.05 0.33 0.05 ;
  LAYER V3 ;
    RECT -0.035 -0.035 0.035 0.035 ;
    RECT 0.105 -0.035 0.175 0.035 ;
    RECT 0.245 -0.035 0.315 0.035 ;
END V3_8_X3E_XX

VIA V3_8_X3W_XX
  LAYER M3 ;
    RECT -0.33 -0.05 0.05 0.05 ;
  LAYER M4 ;
    RECT -0.33 -0.05 0.05 0.05 ;
  LAYER V3 ;
    RECT -0.035 -0.035 0.035 0.035 ;
    RECT -0.175 -0.035 -0.105 0.035 ;
    RECT -0.315 -0.035 -0.245 0.035 ;
END V3_8_X3W_XX

VIA V3_8_X3V_XX
  LAYER M3 ;
    RECT -0.05 -0.19 0.05 0.19 ;
  LAYER M4 ;
    RECT -0.05 -0.19 0.05 0.19 ;
  LAYER V3 ;
    RECT -0.035 -0.175 0.035 -0.105 ;
    RECT -0.035 -0.035 0.035 0.035 ;
    RECT -0.035 0.105 0.035 0.175 ;
END V3_8_X3V_XX

VIA V3_8_X3N_XX
  LAYER M3 ;
    RECT -0.05 -0.05 0.05 0.33 ;
  LAYER M4 ;
    RECT -0.05 -0.05 0.05 0.33 ;
  LAYER V3 ;
    RECT -0.035 -0.035 0.035 0.035 ;
    RECT -0.035 0.105 0.035 0.175 ;
    RECT -0.035 0.245 0.035 0.315 ;
END V3_8_X3N_XX

VIA V3_8_X3S_XX
  LAYER M3 ;
    RECT -0.05 -0.33 0.05 0.05 ;
  LAYER M4 ;
    RECT -0.05 -0.33 0.05 0.05 ;
  LAYER V3 ;
    RECT -0.035 -0.035 0.035 0.035 ;
    RECT -0.035 -0.175 0.035 -0.105 ;
    RECT -0.035 -0.315 0.035 -0.245 ;
END V3_8_X3S_XX

VIA V3_8_X4H_XX
  LAYER M3 ;
    RECT -0.12 -0.12 0.12 0.12 ;
  LAYER M4 ;
    RECT -0.12 -0.12 0.12 0.12 ;
  LAYER V3 ;
    RECT -0.105 -0.105 -0.035 -0.035 ;
    RECT 0.035 -0.105 0.105 -0.035 ;
    RECT -0.105 0.035 -0.035 0.105 ;
    RECT 0.035 0.035 0.105 0.105 ;
END V3_8_X4H_XX

VIA V3_8_X4E_XX
  LAYER M3 ;
    RECT -0.05 -0.19 0.19 0.05 ;
  LAYER M4 ;
    RECT -0.05 -0.19 0.19 0.05 ;
  LAYER V3 ;
    RECT -0.035 -0.175 0.035 -0.105 ;
    RECT 0.105 -0.175 0.175 -0.105 ;
    RECT -0.035 -0.035 0.035 0.035 ;
    RECT 0.105 -0.035 0.175 0.035 ;
END V3_8_X4E_XX

VIA V3_8_X4W_XX
  LAYER M3 ;
    RECT -0.19 -0.05 0.05 0.19 ;
  LAYER M4 ;
    RECT -0.19 -0.05 0.05 0.19 ;
  LAYER V3 ;
    RECT -0.175 -0.035 -0.105 0.035 ;
    RECT -0.035 -0.035 0.035 0.035 ;
    RECT -0.175 0.105 -0.105 0.175 ;
    RECT -0.035 0.105 0.035 0.175 ;
END V3_8_X4W_XX

VIA V3_8_X4N_XX
  LAYER M3 ;
    RECT -0.05 -0.05 0.19 0.19 ;
  LAYER M4 ;
    RECT -0.05 -0.05 0.19 0.19 ;
  LAYER V3 ;
    RECT -0.035 -0.035 0.035 0.035 ;
    RECT 0.105 -0.035 0.175 0.035 ;
    RECT -0.035 0.105 0.035 0.175 ;
    RECT 0.105 0.105 0.175 0.175 ;
END V3_8_X4N_XX

VIA V3_8_X4S_XX
  LAYER M3 ;
    RECT -0.19 -0.19 0.05 0.05 ;
  LAYER M4 ;
    RECT -0.19 -0.19 0.05 0.05 ;
  LAYER V3 ;
    RECT -0.175 -0.175 -0.105 -0.105 ;
    RECT -0.035 -0.175 0.035 -0.105 ;
    RECT -0.175 -0.035 -0.105 0.035 ;
    RECT -0.035 -0.035 0.035 0.035 ;
END V3_8_X4S_XX

VIA V4_0_HV DEFAULT
  LAYER M4 ;
    RECT -0.065 -0.035 0.065 0.035 ;
  LAYER M5 ;
    RECT -0.035 -0.065 0.035 0.065 ;
  LAYER V4 ;
    RECT -0.035 -0.035 0.035 0.035 ;
END V4_0_HV

VIA V4_0_HV_S1 DEFAULT
  LAYER M4 ;
    RECT -0.065 -0.035 0.215 0.035 ;
  LAYER M5 ;
    RECT -0.035 -0.065 0.035 0.065 ;
  LAYER V4 ;
    RECT -0.035 -0.035 0.035 0.035 ;
END V4_0_HV_S1

VIA V4_0_HV_S2 DEFAULT
  LAYER M4 ;
    RECT -0.215 -0.035 0.065 0.035 ;
  LAYER M5 ;
    RECT -0.035 -0.065 0.035 0.065 ;
  LAYER V4 ;
    RECT -0.035 -0.035 0.035 0.035 ;
END V4_0_HV_S2

VIA V4_0_VV DEFAULT
  LAYER M4 ;
    RECT -0.035 -0.065 0.035 0.065 ;
  LAYER M5 ;
    RECT -0.035 -0.065 0.035 0.065 ;
  LAYER V4 ;
    RECT -0.035 -0.035 0.035 0.035 ;
END V4_0_VV

VIA V4_0_HH DEFAULT
  LAYER M4 ;
    RECT -0.065 -0.035 0.065 0.035 ;
  LAYER M5 ;
    RECT -0.065 -0.035 0.065 0.035 ;
  LAYER V4 ;
    RECT -0.035 -0.035 0.035 0.035 ;
END V4_0_HH

VIA V4_0_VH DEFAULT
  LAYER M4 ;
    RECT -0.035 -0.065 0.035 0.065 ;
  LAYER M5 ;
    RECT -0.065 -0.035 0.065 0.035 ;
  LAYER V4 ;
    RECT -0.035 -0.035 0.035 0.035 ;
END V4_0_VH

VIA V4_1_HV DEFAULT
  LAYER M4 ;
    RECT -0.065 -0.035 0.065 0.035 ;
  LAYER M5 ;
    RECT -0.045 -0.055 0.045 0.055 ;
  LAYER V4 ;
    RECT -0.035 -0.035 0.035 0.035 ;
END V4_1_HV

VIA V4_1_HV_S1 DEFAULT
  LAYER M4 ;
    RECT -0.065 -0.035 0.215 0.035 ;
  LAYER M5 ;
    RECT -0.045 -0.055 0.045 0.055 ;
  LAYER V4 ;
    RECT -0.035 -0.035 0.035 0.035 ;
END V4_1_HV_S1

VIA V4_1_HV_S2 DEFAULT
  LAYER M4 ;
    RECT -0.215 -0.035 0.065 0.035 ;
  LAYER M5 ;
    RECT -0.045 -0.055 0.045 0.055 ;
  LAYER V4 ;
    RECT -0.035 -0.035 0.035 0.035 ;
END V4_1_HV_S2

VIA V4_1_VV DEFAULT
  LAYER M4 ;
    RECT -0.035 -0.065 0.035 0.065 ;
  LAYER M5 ;
    RECT -0.045 -0.055 0.045 0.055 ;
  LAYER V4 ;
    RECT -0.035 -0.035 0.035 0.035 ;
END V4_1_VV

VIA V4_1_HH DEFAULT
  LAYER M4 ;
    RECT -0.065 -0.035 0.065 0.035 ;
  LAYER M5 ;
    RECT -0.055 -0.045 0.055 0.045 ;
  LAYER V4 ;
    RECT -0.035 -0.035 0.035 0.035 ;
END V4_1_HH

VIA V4_1_VH DEFAULT
  LAYER M4 ;
    RECT -0.035 -0.065 0.035 0.065 ;
  LAYER M5 ;
    RECT -0.055 -0.045 0.055 0.045 ;
  LAYER V4 ;
    RECT -0.035 -0.035 0.035 0.035 ;
END V4_1_VH

VIA V4_2_HX DEFAULT
  LAYER M4 ;
    RECT -0.065 -0.035 0.065 0.035 ;
  LAYER M5 ;
    RECT -0.05 -0.05 0.05 0.05 ;
  LAYER V4 ;
    RECT -0.035 -0.035 0.035 0.035 ;
END V4_2_HX

VIA V4_2_HX_S1 DEFAULT
  LAYER M4 ;
    RECT -0.065 -0.035 0.215 0.035 ;
  LAYER M5 ;
    RECT -0.05 -0.05 0.05 0.05 ;
  LAYER V4 ;
    RECT -0.035 -0.035 0.035 0.035 ;
END V4_2_HX_S1

VIA V4_2_HX_S2 DEFAULT
  LAYER M4 ;
    RECT -0.215 -0.035 0.065 0.035 ;
  LAYER M5 ;
    RECT -0.05 -0.05 0.05 0.05 ;
  LAYER V4 ;
    RECT -0.035 -0.035 0.035 0.035 ;
END V4_2_HX_S2

VIA V4_2_VX DEFAULT
  LAYER M4 ;
    RECT -0.035 -0.065 0.035 0.065 ;
  LAYER M5 ;
    RECT -0.05 -0.05 0.05 0.05 ;
  LAYER V4 ;
    RECT -0.035 -0.035 0.035 0.035 ;
END V4_2_VX

VIA V4_3_HV DEFAULT
  LAYER M4 ;
    RECT -0.055 -0.045 0.055 0.045 ;
  LAYER M5 ;
    RECT -0.035 -0.065 0.035 0.065 ;
  LAYER V4 ;
    RECT -0.035 -0.035 0.035 0.035 ;
END V4_3_HV

VIA V4_3_HV_S1 DEFAULT
  LAYER M4 ;
    RECT -0.055 -0.045 0.163 0.045 ;
  LAYER M5 ;
    RECT -0.035 -0.065 0.035 0.065 ;
  LAYER V4 ;
    RECT -0.035 -0.035 0.035 0.035 ;
END V4_3_HV_S1

VIA V4_3_HV_S2 DEFAULT
  LAYER M4 ;
    RECT -0.163 -0.045 0.055 0.045 ;
  LAYER M5 ;
    RECT -0.035 -0.065 0.035 0.065 ;
  LAYER V4 ;
    RECT -0.035 -0.035 0.035 0.035 ;
END V4_3_HV_S2

VIA V4_3_VV DEFAULT
  LAYER M4 ;
    RECT -0.045 -0.055 0.045 0.055 ;
  LAYER M5 ;
    RECT -0.035 -0.065 0.035 0.065 ;
  LAYER V4 ;
    RECT -0.035 -0.035 0.035 0.035 ;
END V4_3_VV

VIA V4_3_HH DEFAULT
  LAYER M4 ;
    RECT -0.055 -0.045 0.055 0.045 ;
  LAYER M5 ;
    RECT -0.065 -0.035 0.065 0.035 ;
  LAYER V4 ;
    RECT -0.035 -0.035 0.035 0.035 ;
END V4_3_HH

VIA V4_3_VH DEFAULT
  LAYER M4 ;
    RECT -0.045 -0.055 0.045 0.055 ;
  LAYER M5 ;
    RECT -0.065 -0.035 0.065 0.035 ;
  LAYER V4 ;
    RECT -0.035 -0.035 0.035 0.035 ;
END V4_3_VH

VIA V4_4_HV DEFAULT
  LAYER M4 ;
    RECT -0.055 -0.045 0.055 0.045 ;
  LAYER M5 ;
    RECT -0.045 -0.055 0.045 0.055 ;
  LAYER V4 ;
    RECT -0.035 -0.035 0.035 0.035 ;
END V4_4_HV

VIA V4_4_HV_S1 DEFAULT
  LAYER M4 ;
    RECT -0.055 -0.045 0.163 0.045 ;
  LAYER M5 ;
    RECT -0.045 -0.055 0.045 0.055 ;
  LAYER V4 ;
    RECT -0.035 -0.035 0.035 0.035 ;
END V4_4_HV_S1

VIA V4_4_HV_S2 DEFAULT
  LAYER M4 ;
    RECT -0.163 -0.045 0.055 0.045 ;
  LAYER M5 ;
    RECT -0.045 -0.055 0.045 0.055 ;
  LAYER V4 ;
    RECT -0.035 -0.035 0.035 0.035 ;
END V4_4_HV_S2

VIA V4_4_VV DEFAULT
  LAYER M4 ;
    RECT -0.045 -0.055 0.045 0.055 ;
  LAYER M5 ;
    RECT -0.045 -0.055 0.045 0.055 ;
  LAYER V4 ;
    RECT -0.035 -0.035 0.035 0.035 ;
END V4_4_VV

VIA V4_4_HH DEFAULT
  LAYER M4 ;
    RECT -0.055 -0.045 0.055 0.045 ;
  LAYER M5 ;
    RECT -0.055 -0.045 0.055 0.045 ;
  LAYER V4 ;
    RECT -0.035 -0.035 0.035 0.035 ;
END V4_4_HH

VIA V4_4_VH DEFAULT
  LAYER M4 ;
    RECT -0.045 -0.055 0.045 0.055 ;
  LAYER M5 ;
    RECT -0.055 -0.045 0.055 0.045 ;
  LAYER V4 ;
    RECT -0.035 -0.035 0.035 0.035 ;
END V4_4_VH

VIA V4_5_HX DEFAULT
  LAYER M4 ;
    RECT -0.055 -0.045 0.055 0.045 ;
  LAYER M5 ;
    RECT -0.05 -0.05 0.05 0.05 ;
  LAYER V4 ;
    RECT -0.035 -0.035 0.035 0.035 ;
END V4_5_HX

VIA V4_5_HX_S1 DEFAULT
  LAYER M4 ;
    RECT -0.055 -0.045 0.163 0.045 ;
  LAYER M5 ;
    RECT -0.05 -0.05 0.05 0.05 ;
  LAYER V4 ;
    RECT -0.035 -0.035 0.035 0.035 ;
END V4_5_HX_S1

VIA V4_5_HX_S2 DEFAULT
  LAYER M4 ;
    RECT -0.163 -0.045 0.055 0.045 ;
  LAYER M5 ;
    RECT -0.05 -0.05 0.05 0.05 ;
  LAYER V4 ;
    RECT -0.035 -0.035 0.035 0.035 ;
END V4_5_HX_S2

VIA V4_5_VX DEFAULT
  LAYER M4 ;
    RECT -0.045 -0.055 0.045 0.055 ;
  LAYER M5 ;
    RECT -0.05 -0.05 0.05 0.05 ;
  LAYER V4 ;
    RECT -0.035 -0.035 0.035 0.035 ;
END V4_5_VX

VIA V4_6_XV DEFAULT
  LAYER M4 ;
    RECT -0.05 -0.05 0.05 0.05 ;
  LAYER M5 ;
    RECT -0.035 -0.065 0.035 0.065 ;
  LAYER V4 ;
    RECT -0.035 -0.035 0.035 0.035 ;
END V4_6_XV

VIA V4_6_XV_S1 DEFAULT
  LAYER M4 ;
    RECT -0.05 -0.05 0.146 0.05 ;
  LAYER M5 ;
    RECT -0.035 -0.065 0.035 0.065 ;
  LAYER V4 ;
    RECT -0.035 -0.035 0.035 0.035 ;
END V4_6_XV_S1

VIA V4_6_XV_S2 DEFAULT
  LAYER M4 ;
    RECT -0.146 -0.05 0.05 0.05 ;
  LAYER M5 ;
    RECT -0.035 -0.065 0.035 0.065 ;
  LAYER V4 ;
    RECT -0.035 -0.035 0.035 0.035 ;
END V4_6_XV_S2

VIA V4_6_XH DEFAULT
  LAYER M4 ;
    RECT -0.05 -0.05 0.05 0.05 ;
  LAYER M5 ;
    RECT -0.065 -0.035 0.065 0.035 ;
  LAYER V4 ;
    RECT -0.035 -0.035 0.035 0.035 ;
END V4_6_XH

VIA V4_7_XV DEFAULT
  LAYER M4 ;
    RECT -0.05 -0.05 0.05 0.05 ;
  LAYER M5 ;
    RECT -0.045 -0.055 0.045 0.055 ;
  LAYER V4 ;
    RECT -0.035 -0.035 0.035 0.035 ;
END V4_7_XV

VIA V4_7_XV_S1 DEFAULT
  LAYER M4 ;
    RECT -0.05 -0.05 0.146 0.05 ;
  LAYER M5 ;
    RECT -0.045 -0.055 0.045 0.055 ;
  LAYER V4 ;
    RECT -0.035 -0.035 0.035 0.035 ;
END V4_7_XV_S1

VIA V4_7_XV_S2 DEFAULT
  LAYER M4 ;
    RECT -0.146 -0.05 0.05 0.05 ;
  LAYER M5 ;
    RECT -0.045 -0.055 0.045 0.055 ;
  LAYER V4 ;
    RECT -0.035 -0.035 0.035 0.035 ;
END V4_7_XV_S2

VIA V4_7_XH DEFAULT
  LAYER M4 ;
    RECT -0.05 -0.05 0.05 0.05 ;
  LAYER M5 ;
    RECT -0.055 -0.045 0.055 0.045 ;
  LAYER V4 ;
    RECT -0.035 -0.035 0.035 0.035 ;
END V4_7_XH

VIA V4_8_XX DEFAULT
  LAYER M4 ;
    RECT -0.05 -0.05 0.05 0.05 ;
  LAYER M5 ;
    RECT -0.05 -0.05 0.05 0.05 ;
  LAYER V4 ;
    RECT -0.035 -0.035 0.035 0.035 ;
END V4_8_XX

VIA V4_8_XX_S1 DEFAULT
  LAYER M4 ;
    RECT -0.05 -0.05 0.146 0.05 ;
  LAYER M5 ;
    RECT -0.05 -0.05 0.05 0.05 ;
  LAYER V4 ;
    RECT -0.035 -0.035 0.035 0.035 ;
END V4_8_XX_S1

VIA V4_8_XX_S2 DEFAULT
  LAYER M4 ;
    RECT -0.146 -0.05 0.05 0.05 ;
  LAYER M5 ;
    RECT -0.05 -0.05 0.05 0.05 ;
  LAYER V4 ;
    RECT -0.035 -0.035 0.035 0.035 ;
END V4_8_XX_S2

VIA V4_4_X2H_HV DEFAULT
  LAYER M4 ;
    RECT -0.125 -0.045 0.125 0.045 ;
  LAYER M5 ;
    RECT -0.115 -0.055 0.115 0.055 ;
  LAYER V4 ;
    RECT -0.105 -0.035 -0.035 0.035 ;
    RECT 0.035 -0.035 0.105 0.035 ;
END V4_4_X2H_HV

VIA V4_4_X2E_HV DEFAULT
  LAYER M4 ;
    RECT -0.055 -0.045 0.195 0.045 ;
  LAYER M5 ;
    RECT -0.045 -0.055 0.185 0.055 ;
  LAYER V4 ;
    RECT -0.035 -0.035 0.035 0.035 ;
    RECT 0.105 -0.035 0.175 0.035 ;
END V4_4_X2E_HV

VIA V4_4_X2W_HV DEFAULT
  LAYER M4 ;
    RECT -0.195 -0.045 0.055 0.045 ;
  LAYER M5 ;
    RECT -0.185 -0.055 0.045 0.055 ;
  LAYER V4 ;
    RECT -0.035 -0.035 0.035 0.035 ;
    RECT -0.175 -0.035 -0.105 0.035 ;
END V4_4_X2W_HV

VIA V4_4_X2V_HV DEFAULT
  LAYER M4 ;
    RECT -0.055 -0.115 0.055 0.115 ;
  LAYER M5 ;
    RECT -0.045 -0.125 0.045 0.125 ;
  LAYER V4 ;
    RECT -0.035 -0.105 0.035 -0.035 ;
    RECT -0.035 0.035 0.035 0.105 ;
END V4_4_X2V_HV

VIA V4_4_X2N_HV DEFAULT
  LAYER M4 ;
    RECT -0.055 -0.045 0.055 0.185 ;
  LAYER M5 ;
    RECT -0.045 -0.055 0.045 0.195 ;
  LAYER V4 ;
    RECT -0.035 -0.035 0.035 0.035 ;
    RECT -0.035 0.105 0.035 0.175 ;
END V4_4_X2N_HV

VIA V4_4_X2S_HV DEFAULT
  LAYER M4 ;
    RECT -0.055 -0.185 0.055 0.045 ;
  LAYER M5 ;
    RECT -0.045 -0.195 0.045 0.055 ;
  LAYER V4 ;
    RECT -0.035 -0.035 0.035 0.035 ;
    RECT -0.035 -0.175 0.035 -0.105 ;
END V4_4_X2S_HV

VIA V4_4_X3H_HV DEFAULT
  LAYER M4 ;
    RECT -0.195 -0.045 0.195 0.045 ;
  LAYER M5 ;
    RECT -0.185 -0.055 0.185 0.055 ;
  LAYER V4 ;
    RECT -0.175 -0.035 -0.105 0.035 ;
    RECT -0.035 -0.035 0.035 0.035 ;
    RECT 0.105 -0.035 0.175 0.035 ;
END V4_4_X3H_HV

VIA V4_4_X3E_HV DEFAULT
  LAYER M4 ;
    RECT -0.055 -0.045 0.335 0.045 ;
  LAYER M5 ;
    RECT -0.045 -0.055 0.325 0.055 ;
  LAYER V4 ;
    RECT -0.035 -0.035 0.035 0.035 ;
    RECT 0.105 -0.035 0.175 0.035 ;
    RECT 0.245 -0.035 0.315 0.035 ;
END V4_4_X3E_HV

VIA V4_4_X3W_HV DEFAULT
  LAYER M4 ;
    RECT -0.335 -0.045 0.055 0.045 ;
  LAYER M5 ;
    RECT -0.325 -0.055 0.045 0.055 ;
  LAYER V4 ;
    RECT -0.035 -0.035 0.035 0.035 ;
    RECT -0.175 -0.035 -0.105 0.035 ;
    RECT -0.315 -0.035 -0.245 0.035 ;
END V4_4_X3W_HV

VIA V4_4_X3V_HV DEFAULT
  LAYER M4 ;
    RECT -0.055 -0.185 0.055 0.185 ;
  LAYER M5 ;
    RECT -0.045 -0.195 0.045 0.195 ;
  LAYER V4 ;
    RECT -0.035 -0.175 0.035 -0.105 ;
    RECT -0.035 -0.035 0.035 0.035 ;
    RECT -0.035 0.105 0.035 0.175 ;
END V4_4_X3V_HV

VIA V4_4_X3N_HV DEFAULT
  LAYER M4 ;
    RECT -0.055 -0.045 0.055 0.325 ;
  LAYER M5 ;
    RECT -0.045 -0.055 0.045 0.335 ;
  LAYER V4 ;
    RECT -0.035 -0.035 0.035 0.035 ;
    RECT -0.035 0.105 0.035 0.175 ;
    RECT -0.035 0.245 0.035 0.315 ;
END V4_4_X3N_HV

VIA V4_4_X3S_HV DEFAULT
  LAYER M4 ;
    RECT -0.055 -0.325 0.055 0.045 ;
  LAYER M5 ;
    RECT -0.045 -0.335 0.045 0.055 ;
  LAYER V4 ;
    RECT -0.035 -0.035 0.035 0.035 ;
    RECT -0.035 -0.175 0.035 -0.105 ;
    RECT -0.035 -0.315 0.035 -0.245 ;
END V4_4_X3S_HV

VIA V4_4_X4H_HV DEFAULT
  LAYER M4 ;
    RECT -0.125 -0.115 0.125 0.115 ;
  LAYER M5 ;
    RECT -0.115 -0.125 0.115 0.125 ;
  LAYER V4 ;
    RECT -0.105 -0.105 -0.035 -0.035 ;
    RECT 0.035 -0.105 0.105 -0.035 ;
    RECT -0.105 0.035 -0.035 0.105 ;
    RECT 0.035 0.035 0.105 0.105 ;
END V4_4_X4H_HV

VIA V4_4_X4E_HV DEFAULT
  LAYER M4 ;
    RECT -0.055 -0.185 0.195 0.045 ;
  LAYER M5 ;
    RECT -0.045 -0.195 0.185 0.055 ;
  LAYER V4 ;
    RECT -0.035 -0.175 0.035 -0.105 ;
    RECT 0.105 -0.175 0.175 -0.105 ;
    RECT -0.035 -0.035 0.035 0.035 ;
    RECT 0.105 -0.035 0.175 0.035 ;
END V4_4_X4E_HV

VIA V4_4_X4W_HV DEFAULT
  LAYER M4 ;
    RECT -0.195 -0.045 0.055 0.185 ;
  LAYER M5 ;
    RECT -0.185 -0.055 0.045 0.195 ;
  LAYER V4 ;
    RECT -0.175 -0.035 -0.105 0.035 ;
    RECT -0.035 -0.035 0.035 0.035 ;
    RECT -0.175 0.105 -0.105 0.175 ;
    RECT -0.035 0.105 0.035 0.175 ;
END V4_4_X4W_HV

VIA V4_4_X4N_HV DEFAULT
  LAYER M4 ;
    RECT -0.055 -0.045 0.195 0.185 ;
  LAYER M5 ;
    RECT -0.045 -0.055 0.185 0.195 ;
  LAYER V4 ;
    RECT -0.035 -0.035 0.035 0.035 ;
    RECT 0.105 -0.035 0.175 0.035 ;
    RECT -0.035 0.105 0.035 0.175 ;
    RECT 0.105 0.105 0.175 0.175 ;
END V4_4_X4N_HV

VIA V4_4_X4S_HV DEFAULT
  LAYER M4 ;
    RECT -0.195 -0.185 0.055 0.045 ;
  LAYER M5 ;
    RECT -0.185 -0.195 0.045 0.055 ;
  LAYER V4 ;
    RECT -0.175 -0.175 -0.105 -0.105 ;
    RECT -0.035 -0.175 0.035 -0.105 ;
    RECT -0.175 -0.035 -0.105 0.035 ;
    RECT -0.035 -0.035 0.035 0.035 ;
END V4_4_X4S_HV

VIA V4_5_X2H_HX DEFAULT
  LAYER M4 ;
    RECT -0.125 -0.045 0.125 0.045 ;
  LAYER M5 ;
    RECT -0.12 -0.05 0.12 0.05 ;
  LAYER V4 ;
    RECT -0.105 -0.035 -0.035 0.035 ;
    RECT 0.035 -0.035 0.105 0.035 ;
END V4_5_X2H_HX

VIA V4_5_X2E_HX DEFAULT
  LAYER M4 ;
    RECT -0.055 -0.045 0.195 0.045 ;
  LAYER M5 ;
    RECT -0.05 -0.05 0.19 0.05 ;
  LAYER V4 ;
    RECT -0.035 -0.035 0.035 0.035 ;
    RECT 0.105 -0.035 0.175 0.035 ;
END V4_5_X2E_HX

VIA V4_5_X2W_HX DEFAULT
  LAYER M4 ;
    RECT -0.195 -0.045 0.055 0.045 ;
  LAYER M5 ;
    RECT -0.19 -0.05 0.05 0.05 ;
  LAYER V4 ;
    RECT -0.035 -0.035 0.035 0.035 ;
    RECT -0.175 -0.035 -0.105 0.035 ;
END V4_5_X2W_HX

VIA V4_5_X2V_HX DEFAULT
  LAYER M4 ;
    RECT -0.055 -0.115 0.055 0.115 ;
  LAYER M5 ;
    RECT -0.05 -0.12 0.05 0.12 ;
  LAYER V4 ;
    RECT -0.035 -0.105 0.035 -0.035 ;
    RECT -0.035 0.035 0.035 0.105 ;
END V4_5_X2V_HX

VIA V4_5_X2N_HX
  LAYER M4 ;
    RECT -0.055 -0.045 0.055 0.185 ;
  LAYER M5 ;
    RECT -0.05 -0.05 0.05 0.19 ;
  LAYER V4 ;
    RECT -0.035 -0.035 0.035 0.035 ;
    RECT -0.035 0.105 0.035 0.175 ;
END V4_5_X2N_HX

VIA V4_5_X2S_HX
  LAYER M4 ;
    RECT -0.055 -0.185 0.055 0.045 ;
  LAYER M5 ;
    RECT -0.05 -0.19 0.05 0.05 ;
  LAYER V4 ;
    RECT -0.035 -0.035 0.035 0.035 ;
    RECT -0.035 -0.175 0.035 -0.105 ;
END V4_5_X2S_HX

VIA V4_5_X3H_HX
  LAYER M4 ;
    RECT -0.195 -0.045 0.195 0.045 ;
  LAYER M5 ;
    RECT -0.19 -0.05 0.19 0.05 ;
  LAYER V4 ;
    RECT -0.175 -0.035 -0.105 0.035 ;
    RECT -0.035 -0.035 0.035 0.035 ;
    RECT 0.105 -0.035 0.175 0.035 ;
END V4_5_X3H_HX

VIA V4_5_X3E_HX
  LAYER M4 ;
    RECT -0.055 -0.045 0.335 0.045 ;
  LAYER M5 ;
    RECT -0.05 -0.05 0.33 0.05 ;
  LAYER V4 ;
    RECT -0.035 -0.035 0.035 0.035 ;
    RECT 0.105 -0.035 0.175 0.035 ;
    RECT 0.245 -0.035 0.315 0.035 ;
END V4_5_X3E_HX

VIA V4_5_X3W_HX
  LAYER M4 ;
    RECT -0.335 -0.045 0.055 0.045 ;
  LAYER M5 ;
    RECT -0.33 -0.05 0.05 0.05 ;
  LAYER V4 ;
    RECT -0.035 -0.035 0.035 0.035 ;
    RECT -0.175 -0.035 -0.105 0.035 ;
    RECT -0.315 -0.035 -0.245 0.035 ;
END V4_5_X3W_HX

VIA V4_5_X3V_HX
  LAYER M4 ;
    RECT -0.055 -0.185 0.055 0.185 ;
  LAYER M5 ;
    RECT -0.05 -0.19 0.05 0.19 ;
  LAYER V4 ;
    RECT -0.035 -0.175 0.035 -0.105 ;
    RECT -0.035 -0.035 0.035 0.035 ;
    RECT -0.035 0.105 0.035 0.175 ;
END V4_5_X3V_HX

VIA V4_5_X3N_HX
  LAYER M4 ;
    RECT -0.055 -0.045 0.055 0.325 ;
  LAYER M5 ;
    RECT -0.05 -0.05 0.05 0.33 ;
  LAYER V4 ;
    RECT -0.035 -0.035 0.035 0.035 ;
    RECT -0.035 0.105 0.035 0.175 ;
    RECT -0.035 0.245 0.035 0.315 ;
END V4_5_X3N_HX

VIA V4_5_X3S_HX
  LAYER M4 ;
    RECT -0.055 -0.325 0.055 0.045 ;
  LAYER M5 ;
    RECT -0.05 -0.33 0.05 0.05 ;
  LAYER V4 ;
    RECT -0.035 -0.035 0.035 0.035 ;
    RECT -0.035 -0.175 0.035 -0.105 ;
    RECT -0.035 -0.315 0.035 -0.245 ;
END V4_5_X3S_HX

VIA V4_5_X4H_HX
  LAYER M4 ;
    RECT -0.125 -0.115 0.125 0.115 ;
  LAYER M5 ;
    RECT -0.12 -0.12 0.12 0.12 ;
  LAYER V4 ;
    RECT -0.105 -0.105 -0.035 -0.035 ;
    RECT 0.035 -0.105 0.105 -0.035 ;
    RECT -0.105 0.035 -0.035 0.105 ;
    RECT 0.035 0.035 0.105 0.105 ;
END V4_5_X4H_HX

VIA V4_5_X4E_HX
  LAYER M4 ;
    RECT -0.055 -0.185 0.195 0.045 ;
  LAYER M5 ;
    RECT -0.05 -0.19 0.19 0.05 ;
  LAYER V4 ;
    RECT -0.035 -0.175 0.035 -0.105 ;
    RECT 0.105 -0.175 0.175 -0.105 ;
    RECT -0.035 -0.035 0.035 0.035 ;
    RECT 0.105 -0.035 0.175 0.035 ;
END V4_5_X4E_HX

VIA V4_5_X4W_HX
  LAYER M4 ;
    RECT -0.195 -0.045 0.055 0.185 ;
  LAYER M5 ;
    RECT -0.19 -0.05 0.05 0.19 ;
  LAYER V4 ;
    RECT -0.175 -0.035 -0.105 0.035 ;
    RECT -0.035 -0.035 0.035 0.035 ;
    RECT -0.175 0.105 -0.105 0.175 ;
    RECT -0.035 0.105 0.035 0.175 ;
END V4_5_X4W_HX

VIA V4_5_X4N_HX
  LAYER M4 ;
    RECT -0.055 -0.045 0.195 0.185 ;
  LAYER M5 ;
    RECT -0.05 -0.05 0.19 0.19 ;
  LAYER V4 ;
    RECT -0.035 -0.035 0.035 0.035 ;
    RECT 0.105 -0.035 0.175 0.035 ;
    RECT -0.035 0.105 0.035 0.175 ;
    RECT 0.105 0.105 0.175 0.175 ;
END V4_5_X4N_HX

VIA V4_5_X4S_HX
  LAYER M4 ;
    RECT -0.195 -0.185 0.055 0.045 ;
  LAYER M5 ;
    RECT -0.19 -0.19 0.05 0.05 ;
  LAYER V4 ;
    RECT -0.175 -0.175 -0.105 -0.105 ;
    RECT -0.035 -0.175 0.035 -0.105 ;
    RECT -0.175 -0.035 -0.105 0.035 ;
    RECT -0.035 -0.035 0.035 0.035 ;
END V4_5_X4S_HX

VIA V4_7_X2H_XV
  LAYER M4 ;
    RECT -0.12 -0.05 0.12 0.05 ;
  LAYER M5 ;
    RECT -0.115 -0.055 0.115 0.055 ;
  LAYER V4 ;
    RECT -0.105 -0.035 -0.035 0.035 ;
    RECT 0.035 -0.035 0.105 0.035 ;
END V4_7_X2H_XV

VIA V4_7_X2E_XV
  LAYER M4 ;
    RECT -0.05 -0.05 0.19 0.05 ;
  LAYER M5 ;
    RECT -0.045 -0.055 0.185 0.055 ;
  LAYER V4 ;
    RECT -0.035 -0.035 0.035 0.035 ;
    RECT 0.105 -0.035 0.175 0.035 ;
END V4_7_X2E_XV

VIA V4_7_X2W_XV
  LAYER M4 ;
    RECT -0.19 -0.05 0.05 0.05 ;
  LAYER M5 ;
    RECT -0.185 -0.055 0.045 0.055 ;
  LAYER V4 ;
    RECT -0.035 -0.035 0.035 0.035 ;
    RECT -0.175 -0.035 -0.105 0.035 ;
END V4_7_X2W_XV

VIA V4_7_X2V_XV
  LAYER M4 ;
    RECT -0.05 -0.12 0.05 0.12 ;
  LAYER M5 ;
    RECT -0.045 -0.125 0.045 0.125 ;
  LAYER V4 ;
    RECT -0.035 -0.105 0.035 -0.035 ;
    RECT -0.035 0.035 0.035 0.105 ;
END V4_7_X2V_XV

VIA V4_7_X2N_XV
  LAYER M4 ;
    RECT -0.05 -0.05 0.05 0.19 ;
  LAYER M5 ;
    RECT -0.045 -0.055 0.045 0.195 ;
  LAYER V4 ;
    RECT -0.035 -0.035 0.035 0.035 ;
    RECT -0.035 0.105 0.035 0.175 ;
END V4_7_X2N_XV

VIA V4_7_X2S_XV
  LAYER M4 ;
    RECT -0.05 -0.19 0.05 0.05 ;
  LAYER M5 ;
    RECT -0.045 -0.195 0.045 0.055 ;
  LAYER V4 ;
    RECT -0.035 -0.035 0.035 0.035 ;
    RECT -0.035 -0.175 0.035 -0.105 ;
END V4_7_X2S_XV

VIA V4_7_X3H_XV
  LAYER M4 ;
    RECT -0.19 -0.05 0.19 0.05 ;
  LAYER M5 ;
    RECT -0.185 -0.055 0.185 0.055 ;
  LAYER V4 ;
    RECT -0.175 -0.035 -0.105 0.035 ;
    RECT -0.035 -0.035 0.035 0.035 ;
    RECT 0.105 -0.035 0.175 0.035 ;
END V4_7_X3H_XV

VIA V4_7_X3E_XV
  LAYER M4 ;
    RECT -0.05 -0.05 0.33 0.05 ;
  LAYER M5 ;
    RECT -0.045 -0.055 0.325 0.055 ;
  LAYER V4 ;
    RECT -0.035 -0.035 0.035 0.035 ;
    RECT 0.105 -0.035 0.175 0.035 ;
    RECT 0.245 -0.035 0.315 0.035 ;
END V4_7_X3E_XV

VIA V4_7_X3W_XV
  LAYER M4 ;
    RECT -0.33 -0.05 0.05 0.05 ;
  LAYER M5 ;
    RECT -0.325 -0.055 0.045 0.055 ;
  LAYER V4 ;
    RECT -0.035 -0.035 0.035 0.035 ;
    RECT -0.175 -0.035 -0.105 0.035 ;
    RECT -0.315 -0.035 -0.245 0.035 ;
END V4_7_X3W_XV

VIA V4_7_X3V_XV
  LAYER M4 ;
    RECT -0.05 -0.19 0.05 0.19 ;
  LAYER M5 ;
    RECT -0.045 -0.195 0.045 0.195 ;
  LAYER V4 ;
    RECT -0.035 -0.175 0.035 -0.105 ;
    RECT -0.035 -0.035 0.035 0.035 ;
    RECT -0.035 0.105 0.035 0.175 ;
END V4_7_X3V_XV

VIA V4_7_X3N_XV
  LAYER M4 ;
    RECT -0.05 -0.05 0.05 0.33 ;
  LAYER M5 ;
    RECT -0.045 -0.055 0.045 0.335 ;
  LAYER V4 ;
    RECT -0.035 -0.035 0.035 0.035 ;
    RECT -0.035 0.105 0.035 0.175 ;
    RECT -0.035 0.245 0.035 0.315 ;
END V4_7_X3N_XV

VIA V4_7_X3S_XV
  LAYER M4 ;
    RECT -0.05 -0.33 0.05 0.05 ;
  LAYER M5 ;
    RECT -0.045 -0.335 0.045 0.055 ;
  LAYER V4 ;
    RECT -0.035 -0.035 0.035 0.035 ;
    RECT -0.035 -0.175 0.035 -0.105 ;
    RECT -0.035 -0.315 0.035 -0.245 ;
END V4_7_X3S_XV

VIA V4_7_X4H_XV
  LAYER M4 ;
    RECT -0.12 -0.12 0.12 0.12 ;
  LAYER M5 ;
    RECT -0.115 -0.125 0.115 0.125 ;
  LAYER V4 ;
    RECT -0.105 -0.105 -0.035 -0.035 ;
    RECT 0.035 -0.105 0.105 -0.035 ;
    RECT -0.105 0.035 -0.035 0.105 ;
    RECT 0.035 0.035 0.105 0.105 ;
END V4_7_X4H_XV

VIA V4_7_X4E_XV
  LAYER M4 ;
    RECT -0.05 -0.19 0.19 0.05 ;
  LAYER M5 ;
    RECT -0.045 -0.195 0.185 0.055 ;
  LAYER V4 ;
    RECT -0.035 -0.175 0.035 -0.105 ;
    RECT 0.105 -0.175 0.175 -0.105 ;
    RECT -0.035 -0.035 0.035 0.035 ;
    RECT 0.105 -0.035 0.175 0.035 ;
END V4_7_X4E_XV

VIA V4_7_X4W_XV
  LAYER M4 ;
    RECT -0.19 -0.05 0.05 0.19 ;
  LAYER M5 ;
    RECT -0.185 -0.055 0.045 0.195 ;
  LAYER V4 ;
    RECT -0.175 -0.035 -0.105 0.035 ;
    RECT -0.035 -0.035 0.035 0.035 ;
    RECT -0.175 0.105 -0.105 0.175 ;
    RECT -0.035 0.105 0.035 0.175 ;
END V4_7_X4W_XV

VIA V4_7_X4N_XV
  LAYER M4 ;
    RECT -0.05 -0.05 0.19 0.19 ;
  LAYER M5 ;
    RECT -0.045 -0.055 0.185 0.195 ;
  LAYER V4 ;
    RECT -0.035 -0.035 0.035 0.035 ;
    RECT 0.105 -0.035 0.175 0.035 ;
    RECT -0.035 0.105 0.035 0.175 ;
    RECT 0.105 0.105 0.175 0.175 ;
END V4_7_X4N_XV

VIA V4_7_X4S_XV
  LAYER M4 ;
    RECT -0.19 -0.19 0.05 0.05 ;
  LAYER M5 ;
    RECT -0.185 -0.195 0.045 0.055 ;
  LAYER V4 ;
    RECT -0.175 -0.175 -0.105 -0.105 ;
    RECT -0.035 -0.175 0.035 -0.105 ;
    RECT -0.175 -0.035 -0.105 0.035 ;
    RECT -0.035 -0.035 0.035 0.035 ;
END V4_7_X4S_XV

VIA V4_8_X2H_XX
  LAYER M4 ;
    RECT -0.12 -0.05 0.12 0.05 ;
  LAYER M5 ;
    RECT -0.12 -0.05 0.12 0.05 ;
  LAYER V4 ;
    RECT -0.105 -0.035 -0.035 0.035 ;
    RECT 0.035 -0.035 0.105 0.035 ;
END V4_8_X2H_XX

VIA V4_8_X2E_XX
  LAYER M4 ;
    RECT -0.05 -0.05 0.19 0.05 ;
  LAYER M5 ;
    RECT -0.05 -0.05 0.19 0.05 ;
  LAYER V4 ;
    RECT -0.035 -0.035 0.035 0.035 ;
    RECT 0.105 -0.035 0.175 0.035 ;
END V4_8_X2E_XX

VIA V4_8_X2W_XX
  LAYER M4 ;
    RECT -0.19 -0.05 0.05 0.05 ;
  LAYER M5 ;
    RECT -0.19 -0.05 0.05 0.05 ;
  LAYER V4 ;
    RECT -0.035 -0.035 0.035 0.035 ;
    RECT -0.175 -0.035 -0.105 0.035 ;
END V4_8_X2W_XX

VIA V4_8_X2V_XX
  LAYER M4 ;
    RECT -0.05 -0.12 0.05 0.12 ;
  LAYER M5 ;
    RECT -0.05 -0.12 0.05 0.12 ;
  LAYER V4 ;
    RECT -0.035 -0.105 0.035 -0.035 ;
    RECT -0.035 0.035 0.035 0.105 ;
END V4_8_X2V_XX

VIA V4_8_X2N_XX
  LAYER M4 ;
    RECT -0.05 -0.05 0.05 0.19 ;
  LAYER M5 ;
    RECT -0.05 -0.05 0.05 0.19 ;
  LAYER V4 ;
    RECT -0.035 -0.035 0.035 0.035 ;
    RECT -0.035 0.105 0.035 0.175 ;
END V4_8_X2N_XX

VIA V4_8_X2S_XX
  LAYER M4 ;
    RECT -0.05 -0.19 0.05 0.05 ;
  LAYER M5 ;
    RECT -0.05 -0.19 0.05 0.05 ;
  LAYER V4 ;
    RECT -0.035 -0.035 0.035 0.035 ;
    RECT -0.035 -0.175 0.035 -0.105 ;
END V4_8_X2S_XX

VIA V4_8_X3H_XX
  LAYER M4 ;
    RECT -0.19 -0.05 0.19 0.05 ;
  LAYER M5 ;
    RECT -0.19 -0.05 0.19 0.05 ;
  LAYER V4 ;
    RECT -0.175 -0.035 -0.105 0.035 ;
    RECT -0.035 -0.035 0.035 0.035 ;
    RECT 0.105 -0.035 0.175 0.035 ;
END V4_8_X3H_XX

VIA V4_8_X3E_XX
  LAYER M4 ;
    RECT -0.05 -0.05 0.33 0.05 ;
  LAYER M5 ;
    RECT -0.05 -0.05 0.33 0.05 ;
  LAYER V4 ;
    RECT -0.035 -0.035 0.035 0.035 ;
    RECT 0.105 -0.035 0.175 0.035 ;
    RECT 0.245 -0.035 0.315 0.035 ;
END V4_8_X3E_XX

VIA V4_8_X3W_XX
  LAYER M4 ;
    RECT -0.33 -0.05 0.05 0.05 ;
  LAYER M5 ;
    RECT -0.33 -0.05 0.05 0.05 ;
  LAYER V4 ;
    RECT -0.035 -0.035 0.035 0.035 ;
    RECT -0.175 -0.035 -0.105 0.035 ;
    RECT -0.315 -0.035 -0.245 0.035 ;
END V4_8_X3W_XX

VIA V4_8_X3V_XX
  LAYER M4 ;
    RECT -0.05 -0.19 0.05 0.19 ;
  LAYER M5 ;
    RECT -0.05 -0.19 0.05 0.19 ;
  LAYER V4 ;
    RECT -0.035 -0.175 0.035 -0.105 ;
    RECT -0.035 -0.035 0.035 0.035 ;
    RECT -0.035 0.105 0.035 0.175 ;
END V4_8_X3V_XX

VIA V4_8_X3N_XX
  LAYER M4 ;
    RECT -0.05 -0.05 0.05 0.33 ;
  LAYER M5 ;
    RECT -0.05 -0.05 0.05 0.33 ;
  LAYER V4 ;
    RECT -0.035 -0.035 0.035 0.035 ;
    RECT -0.035 0.105 0.035 0.175 ;
    RECT -0.035 0.245 0.035 0.315 ;
END V4_8_X3N_XX

VIA V4_8_X3S_XX
  LAYER M4 ;
    RECT -0.05 -0.33 0.05 0.05 ;
  LAYER M5 ;
    RECT -0.05 -0.33 0.05 0.05 ;
  LAYER V4 ;
    RECT -0.035 -0.035 0.035 0.035 ;
    RECT -0.035 -0.175 0.035 -0.105 ;
    RECT -0.035 -0.315 0.035 -0.245 ;
END V4_8_X3S_XX

VIA V4_8_X4H_XX
  LAYER M4 ;
    RECT -0.12 -0.12 0.12 0.12 ;
  LAYER M5 ;
    RECT -0.12 -0.12 0.12 0.12 ;
  LAYER V4 ;
    RECT -0.105 -0.105 -0.035 -0.035 ;
    RECT 0.035 -0.105 0.105 -0.035 ;
    RECT -0.105 0.035 -0.035 0.105 ;
    RECT 0.035 0.035 0.105 0.105 ;
END V4_8_X4H_XX

VIA V4_8_X4E_XX
  LAYER M4 ;
    RECT -0.05 -0.19 0.19 0.05 ;
  LAYER M5 ;
    RECT -0.05 -0.19 0.19 0.05 ;
  LAYER V4 ;
    RECT -0.035 -0.175 0.035 -0.105 ;
    RECT 0.105 -0.175 0.175 -0.105 ;
    RECT -0.035 -0.035 0.035 0.035 ;
    RECT 0.105 -0.035 0.175 0.035 ;
END V4_8_X4E_XX

VIA V4_8_X4W_XX
  LAYER M4 ;
    RECT -0.19 -0.05 0.05 0.19 ;
  LAYER M5 ;
    RECT -0.19 -0.05 0.05 0.19 ;
  LAYER V4 ;
    RECT -0.175 -0.035 -0.105 0.035 ;
    RECT -0.035 -0.035 0.035 0.035 ;
    RECT -0.175 0.105 -0.105 0.175 ;
    RECT -0.035 0.105 0.035 0.175 ;
END V4_8_X4W_XX

VIA V4_8_X4N_XX
  LAYER M4 ;
    RECT -0.05 -0.05 0.19 0.19 ;
  LAYER M5 ;
    RECT -0.05 -0.05 0.19 0.19 ;
  LAYER V4 ;
    RECT -0.035 -0.035 0.035 0.035 ;
    RECT 0.105 -0.035 0.175 0.035 ;
    RECT -0.035 0.105 0.035 0.175 ;
    RECT 0.105 0.105 0.175 0.175 ;
END V4_8_X4N_XX

VIA V4_8_X4S_XX
  LAYER M4 ;
    RECT -0.19 -0.19 0.05 0.05 ;
  LAYER M5 ;
    RECT -0.19 -0.19 0.05 0.05 ;
  LAYER V4 ;
    RECT -0.175 -0.175 -0.105 -0.105 ;
    RECT -0.035 -0.175 0.035 -0.105 ;
    RECT -0.175 -0.035 -0.105 0.035 ;
    RECT -0.035 -0.035 0.035 0.035 ;
END V4_8_X4S_XX

VIA V5_0_VH DEFAULT
  LAYER M5 ;
    RECT -0.035 -0.065 0.035 0.065 ;
  LAYER M6 ;
    RECT -0.065 -0.035 0.065 0.035 ;
  LAYER V5 ;
    RECT -0.035 -0.035 0.035 0.035 ;
END V5_0_VH

VIA V5_0_VH_S1 DEFAULT
  LAYER M5 ;
    RECT -0.035 -0.065 0.035 0.215 ;
  LAYER M6 ;
    RECT -0.065 -0.035 0.065 0.035 ;
  LAYER V5 ;
    RECT -0.035 -0.035 0.035 0.035 ;
END V5_0_VH_S1

VIA V5_0_VH_S2 DEFAULT
  LAYER M5 ;
    RECT -0.035 -0.215 0.035 0.065 ;
  LAYER M6 ;
    RECT -0.065 -0.035 0.065 0.035 ;
  LAYER V5 ;
    RECT -0.035 -0.035 0.035 0.035 ;
END V5_0_VH_S2

VIA V5_0_HH DEFAULT
  LAYER M5 ;
    RECT -0.065 -0.035 0.065 0.035 ;
  LAYER M6 ;
    RECT -0.065 -0.035 0.065 0.035 ;
  LAYER V5 ;
    RECT -0.035 -0.035 0.035 0.035 ;
END V5_0_HH

VIA V5_0_VV DEFAULT
  LAYER M5 ;
    RECT -0.035 -0.065 0.035 0.065 ;
  LAYER M6 ;
    RECT -0.035 -0.065 0.035 0.065 ;
  LAYER V5 ;
    RECT -0.035 -0.035 0.035 0.035 ;
END V5_0_VV

VIA V5_0_HV DEFAULT
  LAYER M5 ;
    RECT -0.065 -0.035 0.065 0.035 ;
  LAYER M6 ;
    RECT -0.035 -0.065 0.035 0.065 ;
  LAYER V5 ;
    RECT -0.035 -0.035 0.035 0.035 ;
END V5_0_HV

VIA V5_1_VH DEFAULT
  LAYER M5 ;
    RECT -0.035 -0.065 0.035 0.065 ;
  LAYER M6 ;
    RECT -0.055 -0.045 0.055 0.045 ;
  LAYER V5 ;
    RECT -0.035 -0.035 0.035 0.035 ;
END V5_1_VH

VIA V5_1_VH_S1 DEFAULT
  LAYER M5 ;
    RECT -0.035 -0.065 0.035 0.215 ;
  LAYER M6 ;
    RECT -0.055 -0.045 0.055 0.045 ;
  LAYER V5 ;
    RECT -0.035 -0.035 0.035 0.035 ;
END V5_1_VH_S1

VIA V5_1_VH_S2 DEFAULT
  LAYER M5 ;
    RECT -0.035 -0.215 0.035 0.065 ;
  LAYER M6 ;
    RECT -0.055 -0.045 0.055 0.045 ;
  LAYER V5 ;
    RECT -0.035 -0.035 0.035 0.035 ;
END V5_1_VH_S2

VIA V5_1_HH DEFAULT
  LAYER M5 ;
    RECT -0.065 -0.035 0.065 0.035 ;
  LAYER M6 ;
    RECT -0.055 -0.045 0.055 0.045 ;
  LAYER V5 ;
    RECT -0.035 -0.035 0.035 0.035 ;
END V5_1_HH

VIA V5_1_VV DEFAULT
  LAYER M5 ;
    RECT -0.035 -0.065 0.035 0.065 ;
  LAYER M6 ;
    RECT -0.045 -0.055 0.045 0.055 ;
  LAYER V5 ;
    RECT -0.035 -0.035 0.035 0.035 ;
END V5_1_VV

VIA V5_1_HV DEFAULT
  LAYER M5 ;
    RECT -0.065 -0.035 0.065 0.035 ;
  LAYER M6 ;
    RECT -0.045 -0.055 0.045 0.055 ;
  LAYER V5 ;
    RECT -0.035 -0.035 0.035 0.035 ;
END V5_1_HV

VIA V5_2_VX DEFAULT
  LAYER M5 ;
    RECT -0.035 -0.065 0.035 0.065 ;
  LAYER M6 ;
    RECT -0.05 -0.05 0.05 0.05 ;
  LAYER V5 ;
    RECT -0.035 -0.035 0.035 0.035 ;
END V5_2_VX

VIA V5_2_VX_S1 DEFAULT
  LAYER M5 ;
    RECT -0.035 -0.065 0.035 0.215 ;
  LAYER M6 ;
    RECT -0.05 -0.05 0.05 0.05 ;
  LAYER V5 ;
    RECT -0.035 -0.035 0.035 0.035 ;
END V5_2_VX_S1

VIA V5_2_VX_S2 DEFAULT
  LAYER M5 ;
    RECT -0.035 -0.215 0.035 0.065 ;
  LAYER M6 ;
    RECT -0.05 -0.05 0.05 0.05 ;
  LAYER V5 ;
    RECT -0.035 -0.035 0.035 0.035 ;
END V5_2_VX_S2

VIA V5_2_HX DEFAULT
  LAYER M5 ;
    RECT -0.065 -0.035 0.065 0.035 ;
  LAYER M6 ;
    RECT -0.05 -0.05 0.05 0.05 ;
  LAYER V5 ;
    RECT -0.035 -0.035 0.035 0.035 ;
END V5_2_HX

VIA V5_3_VH DEFAULT
  LAYER M5 ;
    RECT -0.045 -0.055 0.045 0.055 ;
  LAYER M6 ;
    RECT -0.065 -0.035 0.065 0.035 ;
  LAYER V5 ;
    RECT -0.035 -0.035 0.035 0.035 ;
END V5_3_VH

VIA V5_3_VH_S1 DEFAULT
  LAYER M5 ;
    RECT -0.045 -0.055 0.045 0.163 ;
  LAYER M6 ;
    RECT -0.065 -0.035 0.065 0.035 ;
  LAYER V5 ;
    RECT -0.035 -0.035 0.035 0.035 ;
END V5_3_VH_S1

VIA V5_3_VH_S2 DEFAULT
  LAYER M5 ;
    RECT -0.045 -0.163 0.045 0.055 ;
  LAYER M6 ;
    RECT -0.065 -0.035 0.065 0.035 ;
  LAYER V5 ;
    RECT -0.035 -0.035 0.035 0.035 ;
END V5_3_VH_S2

VIA V5_3_HH DEFAULT
  LAYER M5 ;
    RECT -0.055 -0.045 0.055 0.045 ;
  LAYER M6 ;
    RECT -0.065 -0.035 0.065 0.035 ;
  LAYER V5 ;
    RECT -0.035 -0.035 0.035 0.035 ;
END V5_3_HH

VIA V5_3_VV DEFAULT
  LAYER M5 ;
    RECT -0.045 -0.055 0.045 0.055 ;
  LAYER M6 ;
    RECT -0.035 -0.065 0.035 0.065 ;
  LAYER V5 ;
    RECT -0.035 -0.035 0.035 0.035 ;
END V5_3_VV

VIA V5_3_HV DEFAULT
  LAYER M5 ;
    RECT -0.055 -0.045 0.055 0.045 ;
  LAYER M6 ;
    RECT -0.035 -0.065 0.035 0.065 ;
  LAYER V5 ;
    RECT -0.035 -0.035 0.035 0.035 ;
END V5_3_HV

VIA V5_4_VH DEFAULT
  LAYER M5 ;
    RECT -0.045 -0.055 0.045 0.055 ;
  LAYER M6 ;
    RECT -0.055 -0.045 0.055 0.045 ;
  LAYER V5 ;
    RECT -0.035 -0.035 0.035 0.035 ;
END V5_4_VH

VIA V5_4_VH_S1 DEFAULT
  LAYER M5 ;
    RECT -0.045 -0.055 0.045 0.163 ;
  LAYER M6 ;
    RECT -0.055 -0.045 0.055 0.045 ;
  LAYER V5 ;
    RECT -0.035 -0.035 0.035 0.035 ;
END V5_4_VH_S1

VIA V5_4_VH_S2 DEFAULT
  LAYER M5 ;
    RECT -0.045 -0.163 0.045 0.055 ;
  LAYER M6 ;
    RECT -0.055 -0.045 0.055 0.045 ;
  LAYER V5 ;
    RECT -0.035 -0.035 0.035 0.035 ;
END V5_4_VH_S2

VIA V5_4_HH DEFAULT
  LAYER M5 ;
    RECT -0.055 -0.045 0.055 0.045 ;
  LAYER M6 ;
    RECT -0.055 -0.045 0.055 0.045 ;
  LAYER V5 ;
    RECT -0.035 -0.035 0.035 0.035 ;
END V5_4_HH

VIA V5_4_VV DEFAULT
  LAYER M5 ;
    RECT -0.045 -0.055 0.045 0.055 ;
  LAYER M6 ;
    RECT -0.045 -0.055 0.045 0.055 ;
  LAYER V5 ;
    RECT -0.035 -0.035 0.035 0.035 ;
END V5_4_VV

VIA V5_4_HV DEFAULT
  LAYER M5 ;
    RECT -0.055 -0.045 0.055 0.045 ;
  LAYER M6 ;
    RECT -0.045 -0.055 0.045 0.055 ;
  LAYER V5 ;
    RECT -0.035 -0.035 0.035 0.035 ;
END V5_4_HV

VIA V5_5_VX DEFAULT
  LAYER M5 ;
    RECT -0.045 -0.055 0.045 0.055 ;
  LAYER M6 ;
    RECT -0.05 -0.05 0.05 0.05 ;
  LAYER V5 ;
    RECT -0.035 -0.035 0.035 0.035 ;
END V5_5_VX

VIA V5_5_VX_S1 DEFAULT
  LAYER M5 ;
    RECT -0.045 -0.055 0.045 0.163 ;
  LAYER M6 ;
    RECT -0.05 -0.05 0.05 0.05 ;
  LAYER V5 ;
    RECT -0.035 -0.035 0.035 0.035 ;
END V5_5_VX_S1

VIA V5_5_VX_S2 DEFAULT
  LAYER M5 ;
    RECT -0.045 -0.163 0.045 0.055 ;
  LAYER M6 ;
    RECT -0.05 -0.05 0.05 0.05 ;
  LAYER V5 ;
    RECT -0.035 -0.035 0.035 0.035 ;
END V5_5_VX_S2

VIA V5_5_HX DEFAULT
  LAYER M5 ;
    RECT -0.055 -0.045 0.055 0.045 ;
  LAYER M6 ;
    RECT -0.05 -0.05 0.05 0.05 ;
  LAYER V5 ;
    RECT -0.035 -0.035 0.035 0.035 ;
END V5_5_HX

VIA V5_6_XH DEFAULT
  LAYER M5 ;
    RECT -0.05 -0.05 0.05 0.05 ;
  LAYER M6 ;
    RECT -0.065 -0.035 0.065 0.035 ;
  LAYER V5 ;
    RECT -0.035 -0.035 0.035 0.035 ;
END V5_6_XH

VIA V5_6_XH_S1 DEFAULT
  LAYER M5 ;
    RECT -0.05 -0.05 0.05 0.146 ;
  LAYER M6 ;
    RECT -0.065 -0.035 0.065 0.035 ;
  LAYER V5 ;
    RECT -0.035 -0.035 0.035 0.035 ;
END V5_6_XH_S1

VIA V5_6_XH_S2 DEFAULT
  LAYER M5 ;
    RECT -0.05 -0.146 0.05 0.05 ;
  LAYER M6 ;
    RECT -0.065 -0.035 0.065 0.035 ;
  LAYER V5 ;
    RECT -0.035 -0.035 0.035 0.035 ;
END V5_6_XH_S2

VIA V5_6_XV DEFAULT
  LAYER M5 ;
    RECT -0.05 -0.05 0.05 0.05 ;
  LAYER M6 ;
    RECT -0.035 -0.065 0.035 0.065 ;
  LAYER V5 ;
    RECT -0.035 -0.035 0.035 0.035 ;
END V5_6_XV

VIA V5_7_XH DEFAULT
  LAYER M5 ;
    RECT -0.05 -0.05 0.05 0.05 ;
  LAYER M6 ;
    RECT -0.055 -0.045 0.055 0.045 ;
  LAYER V5 ;
    RECT -0.035 -0.035 0.035 0.035 ;
END V5_7_XH

VIA V5_7_XH_S1 DEFAULT
  LAYER M5 ;
    RECT -0.05 -0.05 0.05 0.146 ;
  LAYER M6 ;
    RECT -0.055 -0.045 0.055 0.045 ;
  LAYER V5 ;
    RECT -0.035 -0.035 0.035 0.035 ;
END V5_7_XH_S1

VIA V5_7_XH_S2 DEFAULT
  LAYER M5 ;
    RECT -0.05 -0.146 0.05 0.05 ;
  LAYER M6 ;
    RECT -0.055 -0.045 0.055 0.045 ;
  LAYER V5 ;
    RECT -0.035 -0.035 0.035 0.035 ;
END V5_7_XH_S2

VIA V5_7_XV DEFAULT
  LAYER M5 ;
    RECT -0.05 -0.05 0.05 0.05 ;
  LAYER M6 ;
    RECT -0.045 -0.055 0.045 0.055 ;
  LAYER V5 ;
    RECT -0.035 -0.035 0.035 0.035 ;
END V5_7_XV

VIA V5_8_XX DEFAULT
  LAYER M5 ;
    RECT -0.05 -0.05 0.05 0.05 ;
  LAYER M6 ;
    RECT -0.05 -0.05 0.05 0.05 ;
  LAYER V5 ;
    RECT -0.035 -0.035 0.035 0.035 ;
END V5_8_XX

VIA V5_8_XX_S1 DEFAULT
  LAYER M5 ;
    RECT -0.05 -0.05 0.05 0.146 ;
  LAYER M6 ;
    RECT -0.05 -0.05 0.05 0.05 ;
  LAYER V5 ;
    RECT -0.035 -0.035 0.035 0.035 ;
END V5_8_XX_S1

VIA V5_8_XX_S2 DEFAULT
  LAYER M5 ;
    RECT -0.05 -0.146 0.05 0.05 ;
  LAYER M6 ;
    RECT -0.05 -0.05 0.05 0.05 ;
  LAYER V5 ;
    RECT -0.035 -0.035 0.035 0.035 ;
END V5_8_XX_S2

VIA V5_4_X2H_VH DEFAULT
  LAYER M5 ;
    RECT -0.115 -0.055 0.115 0.055 ;
  LAYER M6 ;
    RECT -0.125 -0.045 0.125 0.045 ;
  LAYER V5 ;
    RECT -0.105 -0.035 -0.035 0.035 ;
    RECT 0.035 -0.035 0.105 0.035 ;
END V5_4_X2H_VH

VIA V5_4_X2E_VH DEFAULT
  LAYER M5 ;
    RECT -0.045 -0.055 0.185 0.055 ;
  LAYER M6 ;
    RECT -0.055 -0.045 0.195 0.045 ;
  LAYER V5 ;
    RECT -0.035 -0.035 0.035 0.035 ;
    RECT 0.105 -0.035 0.175 0.035 ;
END V5_4_X2E_VH

VIA V5_4_X2W_VH DEFAULT
  LAYER M5 ;
    RECT -0.185 -0.055 0.045 0.055 ;
  LAYER M6 ;
    RECT -0.195 -0.045 0.055 0.045 ;
  LAYER V5 ;
    RECT -0.035 -0.035 0.035 0.035 ;
    RECT -0.175 -0.035 -0.105 0.035 ;
END V5_4_X2W_VH

VIA V5_4_X2V_VH DEFAULT
  LAYER M5 ;
    RECT -0.045 -0.125 0.045 0.125 ;
  LAYER M6 ;
    RECT -0.055 -0.115 0.055 0.115 ;
  LAYER V5 ;
    RECT -0.035 -0.105 0.035 -0.035 ;
    RECT -0.035 0.035 0.035 0.105 ;
END V5_4_X2V_VH

VIA V5_4_X2N_VH DEFAULT
  LAYER M5 ;
    RECT -0.045 -0.055 0.045 0.195 ;
  LAYER M6 ;
    RECT -0.055 -0.045 0.055 0.185 ;
  LAYER V5 ;
    RECT -0.035 -0.035 0.035 0.035 ;
    RECT -0.035 0.105 0.035 0.175 ;
END V5_4_X2N_VH

VIA V5_4_X2S_VH DEFAULT
  LAYER M5 ;
    RECT -0.045 -0.195 0.045 0.055 ;
  LAYER M6 ;
    RECT -0.055 -0.185 0.055 0.045 ;
  LAYER V5 ;
    RECT -0.035 -0.035 0.035 0.035 ;
    RECT -0.035 -0.175 0.035 -0.105 ;
END V5_4_X2S_VH

VIA V5_4_X3H_VH DEFAULT
  LAYER M5 ;
    RECT -0.185 -0.055 0.185 0.055 ;
  LAYER M6 ;
    RECT -0.195 -0.045 0.195 0.045 ;
  LAYER V5 ;
    RECT -0.175 -0.035 -0.105 0.035 ;
    RECT -0.035 -0.035 0.035 0.035 ;
    RECT 0.105 -0.035 0.175 0.035 ;
END V5_4_X3H_VH

VIA V5_4_X3E_VH DEFAULT
  LAYER M5 ;
    RECT -0.045 -0.055 0.325 0.055 ;
  LAYER M6 ;
    RECT -0.055 -0.045 0.335 0.045 ;
  LAYER V5 ;
    RECT -0.035 -0.035 0.035 0.035 ;
    RECT 0.105 -0.035 0.175 0.035 ;
    RECT 0.245 -0.035 0.315 0.035 ;
END V5_4_X3E_VH

VIA V5_4_X3W_VH DEFAULT
  LAYER M5 ;
    RECT -0.325 -0.055 0.045 0.055 ;
  LAYER M6 ;
    RECT -0.335 -0.045 0.055 0.045 ;
  LAYER V5 ;
    RECT -0.035 -0.035 0.035 0.035 ;
    RECT -0.175 -0.035 -0.105 0.035 ;
    RECT -0.315 -0.035 -0.245 0.035 ;
END V5_4_X3W_VH

VIA V5_4_X3V_VH DEFAULT
  LAYER M5 ;
    RECT -0.045 -0.195 0.045 0.195 ;
  LAYER M6 ;
    RECT -0.055 -0.185 0.055 0.185 ;
  LAYER V5 ;
    RECT -0.035 -0.175 0.035 -0.105 ;
    RECT -0.035 -0.035 0.035 0.035 ;
    RECT -0.035 0.105 0.035 0.175 ;
END V5_4_X3V_VH

VIA V5_4_X3N_VH DEFAULT
  LAYER M5 ;
    RECT -0.045 -0.055 0.045 0.335 ;
  LAYER M6 ;
    RECT -0.055 -0.045 0.055 0.325 ;
  LAYER V5 ;
    RECT -0.035 -0.035 0.035 0.035 ;
    RECT -0.035 0.105 0.035 0.175 ;
    RECT -0.035 0.245 0.035 0.315 ;
END V5_4_X3N_VH

VIA V5_4_X3S_VH DEFAULT
  LAYER M5 ;
    RECT -0.045 -0.335 0.045 0.055 ;
  LAYER M6 ;
    RECT -0.055 -0.325 0.055 0.045 ;
  LAYER V5 ;
    RECT -0.035 -0.035 0.035 0.035 ;
    RECT -0.035 -0.175 0.035 -0.105 ;
    RECT -0.035 -0.315 0.035 -0.245 ;
END V5_4_X3S_VH

VIA V5_4_X4H_VH DEFAULT
  LAYER M5 ;
    RECT -0.115 -0.125 0.115 0.125 ;
  LAYER M6 ;
    RECT -0.125 -0.115 0.125 0.115 ;
  LAYER V5 ;
    RECT -0.105 -0.105 -0.035 -0.035 ;
    RECT 0.035 -0.105 0.105 -0.035 ;
    RECT -0.105 0.035 -0.035 0.105 ;
    RECT 0.035 0.035 0.105 0.105 ;
END V5_4_X4H_VH

VIA V5_4_X4E_VH DEFAULT
  LAYER M5 ;
    RECT -0.045 -0.195 0.185 0.055 ;
  LAYER M6 ;
    RECT -0.055 -0.185 0.195 0.045 ;
  LAYER V5 ;
    RECT -0.035 -0.175 0.035 -0.105 ;
    RECT 0.105 -0.175 0.175 -0.105 ;
    RECT -0.035 -0.035 0.035 0.035 ;
    RECT 0.105 -0.035 0.175 0.035 ;
END V5_4_X4E_VH

VIA V5_4_X4W_VH DEFAULT
  LAYER M5 ;
    RECT -0.185 -0.055 0.045 0.195 ;
  LAYER M6 ;
    RECT -0.195 -0.045 0.055 0.185 ;
  LAYER V5 ;
    RECT -0.175 -0.035 -0.105 0.035 ;
    RECT -0.035 -0.035 0.035 0.035 ;
    RECT -0.175 0.105 -0.105 0.175 ;
    RECT -0.035 0.105 0.035 0.175 ;
END V5_4_X4W_VH

VIA V5_4_X4N_VH DEFAULT
  LAYER M5 ;
    RECT -0.045 -0.055 0.185 0.195 ;
  LAYER M6 ;
    RECT -0.055 -0.045 0.195 0.185 ;
  LAYER V5 ;
    RECT -0.035 -0.035 0.035 0.035 ;
    RECT 0.105 -0.035 0.175 0.035 ;
    RECT -0.035 0.105 0.035 0.175 ;
    RECT 0.105 0.105 0.175 0.175 ;
END V5_4_X4N_VH

VIA V5_4_X4S_VH DEFAULT
  LAYER M5 ;
    RECT -0.185 -0.195 0.045 0.055 ;
  LAYER M6 ;
    RECT -0.195 -0.185 0.055 0.045 ;
  LAYER V5 ;
    RECT -0.175 -0.175 -0.105 -0.105 ;
    RECT -0.035 -0.175 0.035 -0.105 ;
    RECT -0.175 -0.035 -0.105 0.035 ;
    RECT -0.035 -0.035 0.035 0.035 ;
END V5_4_X4S_VH

VIA V5_5_X2H_VX DEFAULT
  LAYER M5 ;
    RECT -0.115 -0.055 0.115 0.055 ;
  LAYER M6 ;
    RECT -0.12 -0.05 0.12 0.05 ;
  LAYER V5 ;
    RECT -0.105 -0.035 -0.035 0.035 ;
    RECT 0.035 -0.035 0.105 0.035 ;
END V5_5_X2H_VX

VIA V5_5_X2E_VX DEFAULT
  LAYER M5 ;
    RECT -0.045 -0.055 0.185 0.055 ;
  LAYER M6 ;
    RECT -0.05 -0.05 0.19 0.05 ;
  LAYER V5 ;
    RECT -0.035 -0.035 0.035 0.035 ;
    RECT 0.105 -0.035 0.175 0.035 ;
END V5_5_X2E_VX

VIA V5_5_X2W_VX DEFAULT
  LAYER M5 ;
    RECT -0.185 -0.055 0.045 0.055 ;
  LAYER M6 ;
    RECT -0.19 -0.05 0.05 0.05 ;
  LAYER V5 ;
    RECT -0.035 -0.035 0.035 0.035 ;
    RECT -0.175 -0.035 -0.105 0.035 ;
END V5_5_X2W_VX

VIA V5_5_X2V_VX DEFAULT
  LAYER M5 ;
    RECT -0.045 -0.125 0.045 0.125 ;
  LAYER M6 ;
    RECT -0.05 -0.12 0.05 0.12 ;
  LAYER V5 ;
    RECT -0.035 -0.105 0.035 -0.035 ;
    RECT -0.035 0.035 0.035 0.105 ;
END V5_5_X2V_VX

VIA V5_5_X2N_VX
  LAYER M5 ;
    RECT -0.045 -0.055 0.045 0.195 ;
  LAYER M6 ;
    RECT -0.05 -0.05 0.05 0.19 ;
  LAYER V5 ;
    RECT -0.035 -0.035 0.035 0.035 ;
    RECT -0.035 0.105 0.035 0.175 ;
END V5_5_X2N_VX

VIA V5_5_X2S_VX
  LAYER M5 ;
    RECT -0.045 -0.195 0.045 0.055 ;
  LAYER M6 ;
    RECT -0.05 -0.19 0.05 0.05 ;
  LAYER V5 ;
    RECT -0.035 -0.035 0.035 0.035 ;
    RECT -0.035 -0.175 0.035 -0.105 ;
END V5_5_X2S_VX

VIA V5_5_X3H_VX
  LAYER M5 ;
    RECT -0.185 -0.055 0.185 0.055 ;
  LAYER M6 ;
    RECT -0.19 -0.05 0.19 0.05 ;
  LAYER V5 ;
    RECT -0.175 -0.035 -0.105 0.035 ;
    RECT -0.035 -0.035 0.035 0.035 ;
    RECT 0.105 -0.035 0.175 0.035 ;
END V5_5_X3H_VX

VIA V5_5_X3E_VX
  LAYER M5 ;
    RECT -0.045 -0.055 0.325 0.055 ;
  LAYER M6 ;
    RECT -0.05 -0.05 0.33 0.05 ;
  LAYER V5 ;
    RECT -0.035 -0.035 0.035 0.035 ;
    RECT 0.105 -0.035 0.175 0.035 ;
    RECT 0.245 -0.035 0.315 0.035 ;
END V5_5_X3E_VX

VIA V5_5_X3W_VX
  LAYER M5 ;
    RECT -0.325 -0.055 0.045 0.055 ;
  LAYER M6 ;
    RECT -0.33 -0.05 0.05 0.05 ;
  LAYER V5 ;
    RECT -0.035 -0.035 0.035 0.035 ;
    RECT -0.175 -0.035 -0.105 0.035 ;
    RECT -0.315 -0.035 -0.245 0.035 ;
END V5_5_X3W_VX

VIA V5_5_X3V_VX
  LAYER M5 ;
    RECT -0.045 -0.195 0.045 0.195 ;
  LAYER M6 ;
    RECT -0.05 -0.19 0.05 0.19 ;
  LAYER V5 ;
    RECT -0.035 -0.175 0.035 -0.105 ;
    RECT -0.035 -0.035 0.035 0.035 ;
    RECT -0.035 0.105 0.035 0.175 ;
END V5_5_X3V_VX

VIA V5_5_X3N_VX
  LAYER M5 ;
    RECT -0.045 -0.055 0.045 0.335 ;
  LAYER M6 ;
    RECT -0.05 -0.05 0.05 0.33 ;
  LAYER V5 ;
    RECT -0.035 -0.035 0.035 0.035 ;
    RECT -0.035 0.105 0.035 0.175 ;
    RECT -0.035 0.245 0.035 0.315 ;
END V5_5_X3N_VX

VIA V5_5_X3S_VX
  LAYER M5 ;
    RECT -0.045 -0.335 0.045 0.055 ;
  LAYER M6 ;
    RECT -0.05 -0.33 0.05 0.05 ;
  LAYER V5 ;
    RECT -0.035 -0.035 0.035 0.035 ;
    RECT -0.035 -0.175 0.035 -0.105 ;
    RECT -0.035 -0.315 0.035 -0.245 ;
END V5_5_X3S_VX

VIA V5_5_X4H_VX
  LAYER M5 ;
    RECT -0.115 -0.125 0.115 0.125 ;
  LAYER M6 ;
    RECT -0.12 -0.12 0.12 0.12 ;
  LAYER V5 ;
    RECT -0.105 -0.105 -0.035 -0.035 ;
    RECT 0.035 -0.105 0.105 -0.035 ;
    RECT -0.105 0.035 -0.035 0.105 ;
    RECT 0.035 0.035 0.105 0.105 ;
END V5_5_X4H_VX

VIA V5_5_X4E_VX
  LAYER M5 ;
    RECT -0.045 -0.195 0.185 0.055 ;
  LAYER M6 ;
    RECT -0.05 -0.19 0.19 0.05 ;
  LAYER V5 ;
    RECT -0.035 -0.175 0.035 -0.105 ;
    RECT 0.105 -0.175 0.175 -0.105 ;
    RECT -0.035 -0.035 0.035 0.035 ;
    RECT 0.105 -0.035 0.175 0.035 ;
END V5_5_X4E_VX

VIA V5_5_X4W_VX
  LAYER M5 ;
    RECT -0.185 -0.055 0.045 0.195 ;
  LAYER M6 ;
    RECT -0.19 -0.05 0.05 0.19 ;
  LAYER V5 ;
    RECT -0.175 -0.035 -0.105 0.035 ;
    RECT -0.035 -0.035 0.035 0.035 ;
    RECT -0.175 0.105 -0.105 0.175 ;
    RECT -0.035 0.105 0.035 0.175 ;
END V5_5_X4W_VX

VIA V5_5_X4N_VX
  LAYER M5 ;
    RECT -0.045 -0.055 0.185 0.195 ;
  LAYER M6 ;
    RECT -0.05 -0.05 0.19 0.19 ;
  LAYER V5 ;
    RECT -0.035 -0.035 0.035 0.035 ;
    RECT 0.105 -0.035 0.175 0.035 ;
    RECT -0.035 0.105 0.035 0.175 ;
    RECT 0.105 0.105 0.175 0.175 ;
END V5_5_X4N_VX

VIA V5_5_X4S_VX
  LAYER M5 ;
    RECT -0.185 -0.195 0.045 0.055 ;
  LAYER M6 ;
    RECT -0.19 -0.19 0.05 0.05 ;
  LAYER V5 ;
    RECT -0.175 -0.175 -0.105 -0.105 ;
    RECT -0.035 -0.175 0.035 -0.105 ;
    RECT -0.175 -0.035 -0.105 0.035 ;
    RECT -0.035 -0.035 0.035 0.035 ;
END V5_5_X4S_VX

VIA V5_7_X2H_XH
  LAYER M5 ;
    RECT -0.12 -0.05 0.12 0.05 ;
  LAYER M6 ;
    RECT -0.125 -0.045 0.125 0.045 ;
  LAYER V5 ;
    RECT -0.105 -0.035 -0.035 0.035 ;
    RECT 0.035 -0.035 0.105 0.035 ;
END V5_7_X2H_XH

VIA V5_7_X2E_XH
  LAYER M5 ;
    RECT -0.05 -0.05 0.19 0.05 ;
  LAYER M6 ;
    RECT -0.055 -0.045 0.195 0.045 ;
  LAYER V5 ;
    RECT -0.035 -0.035 0.035 0.035 ;
    RECT 0.105 -0.035 0.175 0.035 ;
END V5_7_X2E_XH

VIA V5_7_X2W_XH
  LAYER M5 ;
    RECT -0.19 -0.05 0.05 0.05 ;
  LAYER M6 ;
    RECT -0.195 -0.045 0.055 0.045 ;
  LAYER V5 ;
    RECT -0.035 -0.035 0.035 0.035 ;
    RECT -0.175 -0.035 -0.105 0.035 ;
END V5_7_X2W_XH

VIA V5_7_X2V_XH
  LAYER M5 ;
    RECT -0.05 -0.12 0.05 0.12 ;
  LAYER M6 ;
    RECT -0.055 -0.115 0.055 0.115 ;
  LAYER V5 ;
    RECT -0.035 -0.105 0.035 -0.035 ;
    RECT -0.035 0.035 0.035 0.105 ;
END V5_7_X2V_XH

VIA V5_7_X2N_XH
  LAYER M5 ;
    RECT -0.05 -0.05 0.05 0.19 ;
  LAYER M6 ;
    RECT -0.055 -0.045 0.055 0.185 ;
  LAYER V5 ;
    RECT -0.035 -0.035 0.035 0.035 ;
    RECT -0.035 0.105 0.035 0.175 ;
END V5_7_X2N_XH

VIA V5_7_X2S_XH
  LAYER M5 ;
    RECT -0.05 -0.19 0.05 0.05 ;
  LAYER M6 ;
    RECT -0.055 -0.185 0.055 0.045 ;
  LAYER V5 ;
    RECT -0.035 -0.035 0.035 0.035 ;
    RECT -0.035 -0.175 0.035 -0.105 ;
END V5_7_X2S_XH

VIA V5_7_X3H_XH
  LAYER M5 ;
    RECT -0.19 -0.05 0.19 0.05 ;
  LAYER M6 ;
    RECT -0.195 -0.045 0.195 0.045 ;
  LAYER V5 ;
    RECT -0.175 -0.035 -0.105 0.035 ;
    RECT -0.035 -0.035 0.035 0.035 ;
    RECT 0.105 -0.035 0.175 0.035 ;
END V5_7_X3H_XH

VIA V5_7_X3E_XH
  LAYER M5 ;
    RECT -0.05 -0.05 0.33 0.05 ;
  LAYER M6 ;
    RECT -0.055 -0.045 0.335 0.045 ;
  LAYER V5 ;
    RECT -0.035 -0.035 0.035 0.035 ;
    RECT 0.105 -0.035 0.175 0.035 ;
    RECT 0.245 -0.035 0.315 0.035 ;
END V5_7_X3E_XH

VIA V5_7_X3W_XH
  LAYER M5 ;
    RECT -0.33 -0.05 0.05 0.05 ;
  LAYER M6 ;
    RECT -0.335 -0.045 0.055 0.045 ;
  LAYER V5 ;
    RECT -0.035 -0.035 0.035 0.035 ;
    RECT -0.175 -0.035 -0.105 0.035 ;
    RECT -0.315 -0.035 -0.245 0.035 ;
END V5_7_X3W_XH

VIA V5_7_X3V_XH
  LAYER M5 ;
    RECT -0.05 -0.19 0.05 0.19 ;
  LAYER M6 ;
    RECT -0.055 -0.185 0.055 0.185 ;
  LAYER V5 ;
    RECT -0.035 -0.175 0.035 -0.105 ;
    RECT -0.035 -0.035 0.035 0.035 ;
    RECT -0.035 0.105 0.035 0.175 ;
END V5_7_X3V_XH

VIA V5_7_X3N_XH
  LAYER M5 ;
    RECT -0.05 -0.05 0.05 0.33 ;
  LAYER M6 ;
    RECT -0.055 -0.045 0.055 0.325 ;
  LAYER V5 ;
    RECT -0.035 -0.035 0.035 0.035 ;
    RECT -0.035 0.105 0.035 0.175 ;
    RECT -0.035 0.245 0.035 0.315 ;
END V5_7_X3N_XH

VIA V5_7_X3S_XH
  LAYER M5 ;
    RECT -0.05 -0.33 0.05 0.05 ;
  LAYER M6 ;
    RECT -0.055 -0.325 0.055 0.045 ;
  LAYER V5 ;
    RECT -0.035 -0.035 0.035 0.035 ;
    RECT -0.035 -0.175 0.035 -0.105 ;
    RECT -0.035 -0.315 0.035 -0.245 ;
END V5_7_X3S_XH

VIA V5_7_X4H_XH
  LAYER M5 ;
    RECT -0.12 -0.12 0.12 0.12 ;
  LAYER M6 ;
    RECT -0.125 -0.115 0.125 0.115 ;
  LAYER V5 ;
    RECT -0.105 -0.105 -0.035 -0.035 ;
    RECT 0.035 -0.105 0.105 -0.035 ;
    RECT -0.105 0.035 -0.035 0.105 ;
    RECT 0.035 0.035 0.105 0.105 ;
END V5_7_X4H_XH

VIA V5_7_X4E_XH
  LAYER M5 ;
    RECT -0.05 -0.19 0.19 0.05 ;
  LAYER M6 ;
    RECT -0.055 -0.185 0.195 0.045 ;
  LAYER V5 ;
    RECT -0.035 -0.175 0.035 -0.105 ;
    RECT 0.105 -0.175 0.175 -0.105 ;
    RECT -0.035 -0.035 0.035 0.035 ;
    RECT 0.105 -0.035 0.175 0.035 ;
END V5_7_X4E_XH

VIA V5_7_X4W_XH
  LAYER M5 ;
    RECT -0.19 -0.05 0.05 0.19 ;
  LAYER M6 ;
    RECT -0.195 -0.045 0.055 0.185 ;
  LAYER V5 ;
    RECT -0.175 -0.035 -0.105 0.035 ;
    RECT -0.035 -0.035 0.035 0.035 ;
    RECT -0.175 0.105 -0.105 0.175 ;
    RECT -0.035 0.105 0.035 0.175 ;
END V5_7_X4W_XH

VIA V5_7_X4N_XH
  LAYER M5 ;
    RECT -0.05 -0.05 0.19 0.19 ;
  LAYER M6 ;
    RECT -0.055 -0.045 0.195 0.185 ;
  LAYER V5 ;
    RECT -0.035 -0.035 0.035 0.035 ;
    RECT 0.105 -0.035 0.175 0.035 ;
    RECT -0.035 0.105 0.035 0.175 ;
    RECT 0.105 0.105 0.175 0.175 ;
END V5_7_X4N_XH

VIA V5_7_X4S_XH
  LAYER M5 ;
    RECT -0.19 -0.19 0.05 0.05 ;
  LAYER M6 ;
    RECT -0.195 -0.185 0.055 0.045 ;
  LAYER V5 ;
    RECT -0.175 -0.175 -0.105 -0.105 ;
    RECT -0.035 -0.175 0.035 -0.105 ;
    RECT -0.175 -0.035 -0.105 0.035 ;
    RECT -0.035 -0.035 0.035 0.035 ;
END V5_7_X4S_XH

VIA V5_8_X2H_XX
  LAYER M5 ;
    RECT -0.12 -0.05 0.12 0.05 ;
  LAYER M6 ;
    RECT -0.12 -0.05 0.12 0.05 ;
  LAYER V5 ;
    RECT -0.105 -0.035 -0.035 0.035 ;
    RECT 0.035 -0.035 0.105 0.035 ;
END V5_8_X2H_XX

VIA V5_8_X2E_XX
  LAYER M5 ;
    RECT -0.05 -0.05 0.19 0.05 ;
  LAYER M6 ;
    RECT -0.05 -0.05 0.19 0.05 ;
  LAYER V5 ;
    RECT -0.035 -0.035 0.035 0.035 ;
    RECT 0.105 -0.035 0.175 0.035 ;
END V5_8_X2E_XX

VIA V5_8_X2W_XX
  LAYER M5 ;
    RECT -0.19 -0.05 0.05 0.05 ;
  LAYER M6 ;
    RECT -0.19 -0.05 0.05 0.05 ;
  LAYER V5 ;
    RECT -0.035 -0.035 0.035 0.035 ;
    RECT -0.175 -0.035 -0.105 0.035 ;
END V5_8_X2W_XX

VIA V5_8_X2V_XX
  LAYER M5 ;
    RECT -0.05 -0.12 0.05 0.12 ;
  LAYER M6 ;
    RECT -0.05 -0.12 0.05 0.12 ;
  LAYER V5 ;
    RECT -0.035 -0.105 0.035 -0.035 ;
    RECT -0.035 0.035 0.035 0.105 ;
END V5_8_X2V_XX

VIA V5_8_X2N_XX
  LAYER M5 ;
    RECT -0.05 -0.05 0.05 0.19 ;
  LAYER M6 ;
    RECT -0.05 -0.05 0.05 0.19 ;
  LAYER V5 ;
    RECT -0.035 -0.035 0.035 0.035 ;
    RECT -0.035 0.105 0.035 0.175 ;
END V5_8_X2N_XX

VIA V5_8_X2S_XX
  LAYER M5 ;
    RECT -0.05 -0.19 0.05 0.05 ;
  LAYER M6 ;
    RECT -0.05 -0.19 0.05 0.05 ;
  LAYER V5 ;
    RECT -0.035 -0.035 0.035 0.035 ;
    RECT -0.035 -0.175 0.035 -0.105 ;
END V5_8_X2S_XX

VIA V5_8_X3H_XX
  LAYER M5 ;
    RECT -0.19 -0.05 0.19 0.05 ;
  LAYER M6 ;
    RECT -0.19 -0.05 0.19 0.05 ;
  LAYER V5 ;
    RECT -0.175 -0.035 -0.105 0.035 ;
    RECT -0.035 -0.035 0.035 0.035 ;
    RECT 0.105 -0.035 0.175 0.035 ;
END V5_8_X3H_XX

VIA V5_8_X3E_XX
  LAYER M5 ;
    RECT -0.05 -0.05 0.33 0.05 ;
  LAYER M6 ;
    RECT -0.05 -0.05 0.33 0.05 ;
  LAYER V5 ;
    RECT -0.035 -0.035 0.035 0.035 ;
    RECT 0.105 -0.035 0.175 0.035 ;
    RECT 0.245 -0.035 0.315 0.035 ;
END V5_8_X3E_XX

VIA V5_8_X3W_XX
  LAYER M5 ;
    RECT -0.33 -0.05 0.05 0.05 ;
  LAYER M6 ;
    RECT -0.33 -0.05 0.05 0.05 ;
  LAYER V5 ;
    RECT -0.035 -0.035 0.035 0.035 ;
    RECT -0.175 -0.035 -0.105 0.035 ;
    RECT -0.315 -0.035 -0.245 0.035 ;
END V5_8_X3W_XX

VIA V5_8_X3V_XX
  LAYER M5 ;
    RECT -0.05 -0.19 0.05 0.19 ;
  LAYER M6 ;
    RECT -0.05 -0.19 0.05 0.19 ;
  LAYER V5 ;
    RECT -0.035 -0.175 0.035 -0.105 ;
    RECT -0.035 -0.035 0.035 0.035 ;
    RECT -0.035 0.105 0.035 0.175 ;
END V5_8_X3V_XX

VIA V5_8_X3N_XX
  LAYER M5 ;
    RECT -0.05 -0.05 0.05 0.33 ;
  LAYER M6 ;
    RECT -0.05 -0.05 0.05 0.33 ;
  LAYER V5 ;
    RECT -0.035 -0.035 0.035 0.035 ;
    RECT -0.035 0.105 0.035 0.175 ;
    RECT -0.035 0.245 0.035 0.315 ;
END V5_8_X3N_XX

VIA V5_8_X3S_XX
  LAYER M5 ;
    RECT -0.05 -0.33 0.05 0.05 ;
  LAYER M6 ;
    RECT -0.05 -0.33 0.05 0.05 ;
  LAYER V5 ;
    RECT -0.035 -0.035 0.035 0.035 ;
    RECT -0.035 -0.175 0.035 -0.105 ;
    RECT -0.035 -0.315 0.035 -0.245 ;
END V5_8_X3S_XX

VIA V5_8_X4H_XX
  LAYER M5 ;
    RECT -0.12 -0.12 0.12 0.12 ;
  LAYER M6 ;
    RECT -0.12 -0.12 0.12 0.12 ;
  LAYER V5 ;
    RECT -0.105 -0.105 -0.035 -0.035 ;
    RECT 0.035 -0.105 0.105 -0.035 ;
    RECT -0.105 0.035 -0.035 0.105 ;
    RECT 0.035 0.035 0.105 0.105 ;
END V5_8_X4H_XX

VIA V5_8_X4E_XX
  LAYER M5 ;
    RECT -0.05 -0.19 0.19 0.05 ;
  LAYER M6 ;
    RECT -0.05 -0.19 0.19 0.05 ;
  LAYER V5 ;
    RECT -0.035 -0.175 0.035 -0.105 ;
    RECT 0.105 -0.175 0.175 -0.105 ;
    RECT -0.035 -0.035 0.035 0.035 ;
    RECT 0.105 -0.035 0.175 0.035 ;
END V5_8_X4E_XX

VIA V5_8_X4W_XX
  LAYER M5 ;
    RECT -0.19 -0.05 0.05 0.19 ;
  LAYER M6 ;
    RECT -0.19 -0.05 0.05 0.19 ;
  LAYER V5 ;
    RECT -0.175 -0.035 -0.105 0.035 ;
    RECT -0.035 -0.035 0.035 0.035 ;
    RECT -0.175 0.105 -0.105 0.175 ;
    RECT -0.035 0.105 0.035 0.175 ;
END V5_8_X4W_XX

VIA V5_8_X4N_XX
  LAYER M5 ;
    RECT -0.05 -0.05 0.19 0.19 ;
  LAYER M6 ;
    RECT -0.05 -0.05 0.19 0.19 ;
  LAYER V5 ;
    RECT -0.035 -0.035 0.035 0.035 ;
    RECT 0.105 -0.035 0.175 0.035 ;
    RECT -0.035 0.105 0.035 0.175 ;
    RECT 0.105 0.105 0.175 0.175 ;
END V5_8_X4N_XX

VIA V5_8_X4S_XX
  LAYER M5 ;
    RECT -0.19 -0.19 0.05 0.05 ;
  LAYER M6 ;
    RECT -0.19 -0.19 0.05 0.05 ;
  LAYER V5 ;
    RECT -0.175 -0.175 -0.105 -0.105 ;
    RECT -0.035 -0.175 0.035 -0.105 ;
    RECT -0.175 -0.035 -0.105 0.035 ;
    RECT -0.035 -0.035 0.035 0.035 ;
END V5_8_X4S_XX

VIA TV1_0_HV DEFAULT
  LAYER M6 ;
    RECT -0.23 -0.19 0.23 0.19 ;
  LAYER TM1 ;
    RECT -0.2 -0.21 0.2 0.21 ;
  LAYER TV1 ;
    RECT -0.18 -0.18 0.18 0.18 ;
END TV1_0_HV

VIA TV1_0_VV DEFAULT
  LAYER M6 ;
    RECT -0.19 -0.23 0.19 0.23 ;
  LAYER TM1 ;
    RECT -0.2 -0.21 0.2 0.21 ;
  LAYER TV1 ;
    RECT -0.18 -0.18 0.18 0.18 ;
END TV1_0_VV

VIA TV1_0_HH DEFAULT
  LAYER M6 ;
    RECT -0.23 -0.19 0.23 0.19 ;
  LAYER TM1 ;
    RECT -0.21 -0.2 0.21 0.2 ;
  LAYER TV1 ;
    RECT -0.18 -0.18 0.18 0.18 ;
END TV1_0_HH

VIA TV1_0_VH DEFAULT
  LAYER M6 ;
    RECT -0.19 -0.23 0.19 0.23 ;
  LAYER TM1 ;
    RECT -0.21 -0.2 0.21 0.2 ;
  LAYER TV1 ;
    RECT -0.18 -0.18 0.18 0.18 ;
END TV1_0_VH

VIA TV2_0_VH DEFAULT
  LAYER TM1 ;
    RECT -0.2 -0.23 0.2 0.23 ;
  LAYER TM2 ;
    RECT -0.23 -0.2 0.23 0.2 ;
  LAYER TV2 ;
    RECT -0.18 -0.18 0.18 0.18 ;
END TV2_0_VH

VIA TV2_0_VH_S1 DEFAULT
  LAYER TM1 ;
    RECT -0.2 -0.23 0.2 1.17 ;
  LAYER TM2 ;
    RECT -0.23 -0.2 0.23 0.2 ;
  LAYER TV2 ;
    RECT -0.18 -0.18 0.18 0.18 ;
END TV2_0_VH_S1

VIA TV2_0_VH_S2 DEFAULT
  LAYER TM1 ;
    RECT -0.2 -1.17 0.2 0.23 ;
  LAYER TM2 ;
    RECT -0.23 -0.2 0.23 0.2 ;
  LAYER TV2 ;
    RECT -0.18 -0.18 0.18 0.18 ;
END TV2_0_VH_S2

VIA TV2_0_HH DEFAULT
  LAYER TM1 ;
    RECT -0.23 -0.2 0.23 0.2 ;
  LAYER TM2 ;
    RECT -0.23 -0.2 0.23 0.2 ;
  LAYER TV2 ;
    RECT -0.18 -0.18 0.18 0.18 ;
END TV2_0_HH

VIA TV2_0_VV DEFAULT
  LAYER TM1 ;
    RECT -0.2 -0.23 0.2 0.23 ;
  LAYER TM2 ;
    RECT -0.2 -0.23 0.2 0.23 ;
  LAYER TV2 ;
    RECT -0.18 -0.18 0.18 0.18 ;
END TV2_0_VV

VIA TV2_0_HV DEFAULT
  LAYER TM1 ;
    RECT -0.23 -0.2 0.23 0.2 ;
  LAYER TM2 ;
    RECT -0.2 -0.23 0.2 0.23 ;
  LAYER TV2 ;
    RECT -0.18 -0.18 0.18 0.18 ;
END TV2_0_HV

VIA TV2_0_X2H_VH DEFAULT
  LAYER TM1 ;
    RECT -0.55 -0.23 0.55 0.23 ;
  LAYER TM2 ;
    RECT -0.58 -0.2 0.58 0.2 ;
  LAYER TV2 ;
    RECT -0.53 -0.18 -0.17 0.18 ;
    RECT 0.17 -0.18 0.53 0.18 ;
END TV2_0_X2H_VH

VIA TV2_0_X2E_VH DEFAULT
  LAYER TM1 ;
    RECT -0.2 -0.23 0.9 0.23 ;
  LAYER TM2 ;
    RECT -0.23 -0.2 0.93 0.2 ;
  LAYER TV2 ;
    RECT -0.18 -0.18 0.18 0.18 ;
    RECT 0.52 -0.18 0.88 0.18 ;
END TV2_0_X2E_VH

VIA TV2_0_X2W_VH DEFAULT
  LAYER TM1 ;
    RECT -0.9 -0.23 0.2 0.23 ;
  LAYER TM2 ;
    RECT -0.93 -0.2 0.23 0.2 ;
  LAYER TV2 ;
    RECT -0.18 -0.18 0.18 0.18 ;
    RECT -0.88 -0.18 -0.52 0.18 ;
END TV2_0_X2W_VH

VIA TV2_0_X2V_VH DEFAULT
  LAYER TM1 ;
    RECT -0.2 -0.58 0.2 0.58 ;
  LAYER TM2 ;
    RECT -0.23 -0.55 0.23 0.55 ;
  LAYER TV2 ;
    RECT -0.18 -0.53 0.18 -0.17 ;
    RECT -0.18 0.17 0.18 0.53 ;
END TV2_0_X2V_VH

VIA TV2_0_X2N_VH DEFAULT
  LAYER TM1 ;
    RECT -0.2 -0.23 0.2 0.93 ;
  LAYER TM2 ;
    RECT -0.23 -0.2 0.23 0.9 ;
  LAYER TV2 ;
    RECT -0.18 -0.18 0.18 0.18 ;
    RECT -0.18 0.52 0.18 0.88 ;
END TV2_0_X2N_VH

VIA TV2_0_X2S_VH DEFAULT
  LAYER TM1 ;
    RECT -0.2 -0.93 0.2 0.23 ;
  LAYER TM2 ;
    RECT -0.23 -0.9 0.23 0.2 ;
  LAYER TV2 ;
    RECT -0.18 -0.18 0.18 0.18 ;
    RECT -0.18 -0.88 0.18 -0.52 ;
END TV2_0_X2S_VH

VIA TV2_0_X3H_VH DEFAULT
  LAYER TM1 ;
    RECT -0.9 -0.23 0.9 0.23 ;
  LAYER TM2 ;
    RECT -0.93 -0.2 0.93 0.2 ;
  LAYER TV2 ;
    RECT -0.88 -0.18 -0.52 0.18 ;
    RECT -0.18 -0.18 0.18 0.18 ;
    RECT 0.52 -0.18 0.88 0.18 ;
END TV2_0_X3H_VH

VIA TV2_0_X3E_VH DEFAULT
  LAYER TM1 ;
    RECT -0.2 -0.23 1.6 0.23 ;
  LAYER TM2 ;
    RECT -0.23 -0.2 1.63 0.2 ;
  LAYER TV2 ;
    RECT -0.18 -0.18 0.18 0.18 ;
    RECT 0.52 -0.18 0.88 0.18 ;
    RECT 1.22 -0.18 1.58 0.18 ;
END TV2_0_X3E_VH

VIA TV2_0_X3W_VH DEFAULT
  LAYER TM1 ;
    RECT -1.6 -0.23 0.2 0.23 ;
  LAYER TM2 ;
    RECT -1.63 -0.2 0.23 0.2 ;
  LAYER TV2 ;
    RECT -0.18 -0.18 0.18 0.18 ;
    RECT -0.88 -0.18 -0.52 0.18 ;
    RECT -1.58 -0.18 -1.22 0.18 ;
END TV2_0_X3W_VH

VIA TV2_0_X3V_VH DEFAULT
  LAYER TM1 ;
    RECT -0.2 -0.93 0.2 0.93 ;
  LAYER TM2 ;
    RECT -0.23 -0.9 0.23 0.9 ;
  LAYER TV2 ;
    RECT -0.18 -0.88 0.18 -0.52 ;
    RECT -0.18 -0.18 0.18 0.18 ;
    RECT -0.18 0.52 0.18 0.88 ;
END TV2_0_X3V_VH

VIA TV2_0_X3N_VH DEFAULT
  LAYER TM1 ;
    RECT -0.2 -0.23 0.2 1.63 ;
  LAYER TM2 ;
    RECT -0.23 -0.2 0.23 1.6 ;
  LAYER TV2 ;
    RECT -0.18 -0.18 0.18 0.18 ;
    RECT -0.18 0.52 0.18 0.88 ;
    RECT -0.18 1.22 0.18 1.58 ;
END TV2_0_X3N_VH

VIA TV2_0_X3S_VH DEFAULT
  LAYER TM1 ;
    RECT -0.2 -1.63 0.2 0.23 ;
  LAYER TM2 ;
    RECT -0.23 -1.6 0.23 0.2 ;
  LAYER TV2 ;
    RECT -0.18 -0.18 0.18 0.18 ;
    RECT -0.18 -0.88 0.18 -0.52 ;
    RECT -0.18 -1.58 0.18 -1.22 ;
END TV2_0_X3S_VH

VIA TV2_0_X4H_VH DEFAULT
  LAYER TM1 ;
    RECT -0.63 -0.66 0.63 0.66 ;
  LAYER TM2 ;
    RECT -0.66 -0.63 0.66 0.63 ;
  LAYER TV2 ;
    RECT -0.61 -0.61 -0.25 -0.25 ;
    RECT 0.25 -0.61 0.61 -0.25 ;
    RECT -0.61 0.25 -0.25 0.61 ;
    RECT 0.25 0.25 0.61 0.61 ;
END TV2_0_X4H_VH

VIA TV2_0_X4E_VH DEFAULT
  LAYER TM1 ;
    RECT -0.2 -1.09 1.06 0.23 ;
  LAYER TM2 ;
    RECT -0.23 -1.06 1.09 0.2 ;
  LAYER TV2 ;
    RECT -0.18 -1.04 0.18 -0.68 ;
    RECT 0.68 -1.04 1.04 -0.68 ;
    RECT -0.18 -0.18 0.18 0.18 ;
    RECT 0.68 -0.18 1.04 0.18 ;
END TV2_0_X4E_VH

VIA TV2_0_X4W_VH DEFAULT
  LAYER TM1 ;
    RECT -1.06 -0.23 0.2 1.09 ;
  LAYER TM2 ;
    RECT -1.09 -0.2 0.23 1.06 ;
  LAYER TV2 ;
    RECT -1.04 -0.18 -0.68 0.18 ;
    RECT -0.18 -0.18 0.18 0.18 ;
    RECT -1.04 0.68 -0.68 1.04 ;
    RECT -0.18 0.68 0.18 1.04 ;
END TV2_0_X4W_VH

VIA TV2_0_X4N_VH DEFAULT
  LAYER TM1 ;
    RECT -0.2 -0.23 1.06 1.09 ;
  LAYER TM2 ;
    RECT -0.23 -0.2 1.09 1.06 ;
  LAYER TV2 ;
    RECT -0.18 -0.18 0.18 0.18 ;
    RECT 0.68 -0.18 1.04 0.18 ;
    RECT -0.18 0.68 0.18 1.04 ;
    RECT 0.68 0.68 1.04 1.04 ;
END TV2_0_X4N_VH

VIA TV2_0_X4S_VH DEFAULT
  LAYER TM1 ;
    RECT -1.06 -1.09 0.2 0.23 ;
  LAYER TM2 ;
    RECT -1.09 -1.06 0.23 0.2 ;
  LAYER TV2 ;
    RECT -1.04 -1.04 -0.68 -0.68 ;
    RECT -0.18 -1.04 0.18 -0.68 ;
    RECT -1.04 -0.18 -0.68 0.18 ;
    RECT -0.18 -0.18 0.18 0.18 ;
END TV2_0_X4S_VH

VIA PA_0_XX DEFAULT
  LAYER TM2 ;
    RECT -1.5 -1.5 1.5 1.5 ;
  LAYER ALPA ;
    RECT -1.5 -1.5 1.5 1.5 ;
  LAYER PA ;
    RECT -1.0 -1.0 1.0 1.0 ;
END PA_0_XX

VIA PA_0_X2H_XX DEFAULT
  LAYER TM2 ;
    RECT -3.5 -1.5 3.5 1.5 ;
  LAYER ALPA ;
    RECT -3.5 -1.5 3.5 1.5 ;
  LAYER PA ;
    RECT -3.0 -1.0 -1.0 1.0 ;
    RECT 1.0 -1.0 3.0 1.0 ;
END PA_0_X2H_XX

VIA PA_0_X2E_XX DEFAULT
  LAYER TM2 ;
    RECT -1.5 -1.5 5.5 1.5 ;
  LAYER ALPA ;
    RECT -1.5 -1.5 5.5 1.5 ;
  LAYER PA ;
    RECT -1.0 -1.0 1.0 1.0 ;
    RECT 3.0 -1.0 5.0 1.0 ;
END PA_0_X2E_XX

VIA PA_0_X2W_XX DEFAULT
  LAYER TM2 ;
    RECT -5.5 -1.5 1.5 1.5 ;
  LAYER ALPA ;
    RECT -5.5 -1.5 1.5 1.5 ;
  LAYER PA ;
    RECT -1.0 -1.0 1.0 1.0 ;
    RECT -5.0 -1.0 -3.0 1.0 ;
END PA_0_X2W_XX

VIA PA_0_X2V_XX DEFAULT
  LAYER TM2 ;
    RECT -1.5 -3.5 1.5 3.5 ;
  LAYER ALPA ;
    RECT -1.5 -3.5 1.5 3.5 ;
  LAYER PA ;
    RECT -1.0 -3.0 1.0 -1.0 ;
    RECT -1.0 1.0 1.0 3.0 ;
END PA_0_X2V_XX

VIA PA_0_X2N_XX DEFAULT
  LAYER TM2 ;
    RECT -1.5 -1.5 1.5 5.5 ;
  LAYER ALPA ;
    RECT -1.5 -1.5 1.5 5.5 ;
  LAYER PA ;
    RECT -1.0 -1.0 1.0 1.0 ;
    RECT -1.0 3.0 1.0 5.0 ;
END PA_0_X2N_XX

VIA PA_0_X2S_XX DEFAULT
  LAYER TM2 ;
    RECT -1.5 -5.5 1.5 1.5 ;
  LAYER ALPA ;
    RECT -1.5 -5.5 1.5 1.5 ;
  LAYER PA ;
    RECT -1.0 -1.0 1.0 1.0 ;
    RECT -1.0 -5.0 1.0 -3.0 ;
END PA_0_X2S_XX

VIA PA_0_X3H_XX DEFAULT
  LAYER TM2 ;
    RECT -5.5 -1.5 5.5 1.5 ;
  LAYER ALPA ;
    RECT -5.5 -1.5 5.5 1.5 ;
  LAYER PA ;
    RECT -5.0 -1.0 -3.0 1.0 ;
    RECT -1.0 -1.0 1.0 1.0 ;
    RECT 3.0 -1.0 5.0 1.0 ;
END PA_0_X3H_XX

VIA PA_0_X3E_XX DEFAULT
  LAYER TM2 ;
    RECT -1.5 -1.5 9.5 1.5 ;
  LAYER ALPA ;
    RECT -1.5 -1.5 9.5 1.5 ;
  LAYER PA ;
    RECT -1.0 -1.0 1.0 1.0 ;
    RECT 3.0 -1.0 5.0 1.0 ;
    RECT 7.0 -1.0 9.0 1.0 ;
END PA_0_X3E_XX

VIA PA_0_X3W_XX DEFAULT
  LAYER TM2 ;
    RECT -9.5 -1.5 1.5 1.5 ;
  LAYER ALPA ;
    RECT -9.5 -1.5 1.5 1.5 ;
  LAYER PA ;
    RECT -1.0 -1.0 1.0 1.0 ;
    RECT -5.0 -1.0 -3.0 1.0 ;
    RECT -9.0 -1.0 -7.0 1.0 ;
END PA_0_X3W_XX

VIA PA_0_X3V_XX DEFAULT
  LAYER TM2 ;
    RECT -1.5 -5.5 1.5 5.5 ;
  LAYER ALPA ;
    RECT -1.5 -5.5 1.5 5.5 ;
  LAYER PA ;
    RECT -1.0 -5.0 1.0 -3.0 ;
    RECT -1.0 -1.0 1.0 1.0 ;
    RECT -1.0 3.0 1.0 5.0 ;
END PA_0_X3V_XX

VIA PA_0_X3N_XX DEFAULT
  LAYER TM2 ;
    RECT -1.5 -1.5 1.5 9.5 ;
  LAYER ALPA ;
    RECT -1.5 -1.5 1.5 9.5 ;
  LAYER PA ;
    RECT -1.0 -1.0 1.0 1.0 ;
    RECT -1.0 3.0 1.0 5.0 ;
    RECT -1.0 7.0 1.0 9.0 ;
END PA_0_X3N_XX

VIA PA_0_X3S_XX DEFAULT
  LAYER TM2 ;
    RECT -1.5 -9.5 1.5 1.5 ;
  LAYER ALPA ;
    RECT -1.5 -9.5 1.5 1.5 ;
  LAYER PA ;
    RECT -1.0 -1.0 1.0 1.0 ;
    RECT -1.0 -5.0 1.0 -3.0 ;
    RECT -1.0 -9.0 1.0 -7.0 ;
END PA_0_X3S_XX

VIA PA_0_X4H_XX DEFAULT
  LAYER TM2 ;
    RECT -3.5 -3.5 3.5 3.5 ;
  LAYER ALPA ;
    RECT -3.5 -3.5 3.5 3.5 ;
  LAYER PA ;
    RECT -3.0 -3.0 -1.0 -1.0 ;
    RECT 1.0 -3.0 3.0 -1.0 ;
    RECT -3.0 1.0 -1.0 3.0 ;
    RECT 1.0 1.0 3.0 3.0 ;
END PA_0_X4H_XX

VIA PA_0_X4E_XX DEFAULT
  LAYER TM2 ;
    RECT -1.5 -5.5 5.5 1.5 ;
  LAYER ALPA ;
    RECT -1.5 -5.5 5.5 1.5 ;
  LAYER PA ;
    RECT -1.0 -5.0 1.0 -3.0 ;
    RECT 3.0 -5.0 5.0 -3.0 ;
    RECT -1.0 -1.0 1.0 1.0 ;
    RECT 3.0 -1.0 5.0 1.0 ;
END PA_0_X4E_XX

VIA PA_0_X4W_XX DEFAULT
  LAYER TM2 ;
    RECT -5.5 -1.5 1.5 5.5 ;
  LAYER ALPA ;
    RECT -5.5 -1.5 1.5 5.5 ;
  LAYER PA ;
    RECT -5.0 -1.0 -3.0 1.0 ;
    RECT -1.0 -1.0 1.0 1.0 ;
    RECT -5.0 3.0 -3.0 5.0 ;
    RECT -1.0 3.0 1.0 5.0 ;
END PA_0_X4W_XX

VIA PA_0_X4N_XX DEFAULT
  LAYER TM2 ;
    RECT -1.5 -1.5 5.5 5.5 ;
  LAYER ALPA ;
    RECT -1.5 -1.5 5.5 5.5 ;
  LAYER PA ;
    RECT -1.0 -1.0 1.0 1.0 ;
    RECT 3.0 -1.0 5.0 1.0 ;
    RECT -1.0 3.0 1.0 5.0 ;
    RECT 3.0 3.0 5.0 5.0 ;
END PA_0_X4N_XX

VIA PA_0_X4S_XX DEFAULT
  LAYER TM2 ;
    RECT -5.5 -5.5 1.5 1.5 ;
  LAYER ALPA ;
    RECT -5.5 -5.5 1.5 1.5 ;
  LAYER PA ;
    RECT -5.0 -5.0 -3.0 -3.0 ;
    RECT -1.0 -5.0 1.0 -3.0 ;
    RECT -5.0 -1.0 -3.0 1.0 ;
    RECT -1.0 -1.0 1.0 1.0 ;
END PA_0_X4S_XX

VIARULE V1_RULE GENERATE
  LAYER M1 ;
    ENCLOSURE 0.03 0.0 ;
  LAYER M2 ;
    ENCLOSURE 0.03 0.0 ;
  LAYER V1 ;
    RECT -0.035 -0.035 0.035 0.035 ;
    SPACING 0.16 BY 0.16 ;
END V1_RULE

VIARULE V2_RULE GENERATE
  LAYER M2 ;
    ENCLOSURE 0.03 0.0 ;
  LAYER M3 ;
    ENCLOSURE 0.03 0.0 ;
  LAYER V2 ;
    RECT -0.035 -0.035 0.035 0.035 ;
    SPACING 0.16 BY 0.16 ;
END V2_RULE

VIARULE V3_RULE GENERATE
  LAYER M3 ;
    ENCLOSURE 0.03 0.0 ;
  LAYER M4 ;
    ENCLOSURE 0.03 0.0 ;
  LAYER V3 ;
    RECT -0.035 -0.035 0.035 0.035 ;
    SPACING 0.16 BY 0.16 ;
END V3_RULE

VIARULE V4_RULE GENERATE
  LAYER M4 ;
    ENCLOSURE 0.03 0.0 ;
  LAYER M5 ;
    ENCLOSURE 0.03 0.0 ;
  LAYER V4 ;
    RECT -0.035 -0.035 0.035 0.035 ;
    SPACING 0.16 BY 0.16 ;
END V4_RULE

VIARULE V5_RULE GENERATE
  LAYER M5 ;
    ENCLOSURE 0.03 0.0 ;
  LAYER M6 ;
    ENCLOSURE 0.03 0.0 ;
  LAYER V5 ;
    RECT -0.035 -0.035 0.035 0.035 ;
    SPACING 0.16 BY 0.16 ;
END V5_RULE

VIARULE TV1_RULE GENERATE
  LAYER M6 ;
    ENCLOSURE 0.05 0.01 ;
  LAYER TM1 ;
    ENCLOSURE 0.03 0.02 ;
  LAYER TV1 ;
    RECT -0.18 -0.18 0.18 0.18 ;
    SPACING 0.7 BY 0.7 ;
END TV1_RULE

VIARULE TV2_RULE GENERATE
  LAYER TM1 ;
    ENCLOSURE 0.05 0.02 ;
  LAYER TM2 ;
    ENCLOSURE 0.05 0.02 ;
  LAYER TV2 ;
    RECT -0.18 -0.18 0.18 0.18 ;
    SPACING 0.7 BY 0.7 ;
END TV2_RULE

VIARULE PA_RULE GENERATE
  LAYER TM2 ;
    ENCLOSURE 0.5 0.5 ;
  LAYER ALPA ;
    ENCLOSURE 0.5 0.5 ;
  LAYER PA ;
    RECT -1.0 -1.0 1.0 1.0 ;
    SPACING 4.0 BY 4.0 ;
END PA_RULE




END LIBRARY
